VERSION 5.8 ;
BUSBITCHARS "[]" ;
DIVIDERCHAR "/" ;
UNITS
    DATABASE MICRONS 1000 ;
END UNITS

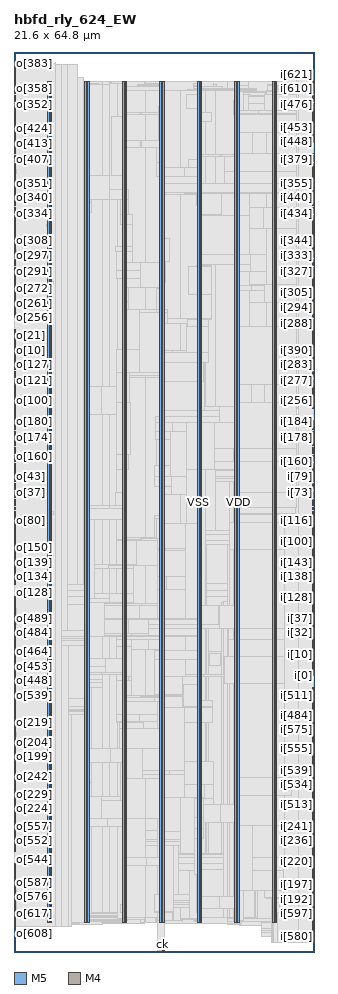
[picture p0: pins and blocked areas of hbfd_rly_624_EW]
MACRO hbfd_rly_624_EW
  FOREIGN hbfd_rly_624_EW 0 0 ;
  CLASS BLOCK ;
  SIZE 21.6 BY 64.8 ;
  PIN ck
    DIRECTION INPUT ;
    USE SIGNAL ;
    PORT
      LAYER M5 ;
        RECT  10.704 0 10.728 0.084 ;
    END
  END ck
  PIN i[0]
    DIRECTION INPUT ;
    USE SIGNAL ;
    PORT
      LAYER M4 ;
        RECT  21.516 19.92 21.6 19.944 ;
    END
  END i[0]
  PIN i[100]
    DIRECTION INPUT ;
    USE SIGNAL ;
    PORT
      LAYER M4 ;
        RECT  21.516 29.52 21.6 29.544 ;
    END
  END i[100]
  PIN i[101]
    DIRECTION INPUT ;
    USE SIGNAL ;
    PORT
      LAYER M4 ;
        RECT  21.516 29.616 21.6 29.64 ;
    END
  END i[101]
  PIN i[102]
    DIRECTION INPUT ;
    USE SIGNAL ;
    PORT
      LAYER M4 ;
        RECT  21.516 29.712 21.6 29.736 ;
    END
  END i[102]
  PIN i[103]
    DIRECTION INPUT ;
    USE SIGNAL ;
    PORT
      LAYER M4 ;
        RECT  21.516 29.808 21.6 29.832 ;
    END
  END i[103]
  PIN i[104]
    DIRECTION INPUT ;
    USE SIGNAL ;
    PORT
      LAYER M4 ;
        RECT  21.516 29.904 21.6 29.928 ;
    END
  END i[104]
  PIN i[105]
    DIRECTION INPUT ;
    USE SIGNAL ;
    PORT
      LAYER M4 ;
        RECT  21.516 30 21.6 30.024 ;
    END
  END i[105]
  PIN i[106]
    DIRECTION INPUT ;
    USE SIGNAL ;
    PORT
      LAYER M4 ;
        RECT  21.516 30.096 21.6 30.12 ;
    END
  END i[106]
  PIN i[107]
    DIRECTION INPUT ;
    USE SIGNAL ;
    PORT
      LAYER M4 ;
        RECT  21.516 30.192 21.6 30.216 ;
    END
  END i[107]
  PIN i[108]
    DIRECTION INPUT ;
    USE SIGNAL ;
    PORT
      LAYER M4 ;
        RECT  21.516 30.288 21.6 30.312 ;
    END
  END i[108]
  PIN i[109]
    DIRECTION INPUT ;
    USE SIGNAL ;
    PORT
      LAYER M4 ;
        RECT  21.516 30.384 21.6 30.408 ;
    END
  END i[109]
  PIN i[10]
    DIRECTION INPUT ;
    USE SIGNAL ;
    PORT
      LAYER M4 ;
        RECT  21.516 20.88 21.6 20.904 ;
    END
  END i[10]
  PIN i[110]
    DIRECTION INPUT ;
    USE SIGNAL ;
    PORT
      LAYER M4 ;
        RECT  21.516 30.48 21.6 30.504 ;
    END
  END i[110]
  PIN i[111]
    DIRECTION INPUT ;
    USE SIGNAL ;
    PORT
      LAYER M4 ;
        RECT  21.516 30.576 21.6 30.6 ;
    END
  END i[111]
  PIN i[112]
    DIRECTION INPUT ;
    USE SIGNAL ;
    PORT
      LAYER M4 ;
        RECT  21.516 30.672 21.6 30.696 ;
    END
  END i[112]
  PIN i[113]
    DIRECTION INPUT ;
    USE SIGNAL ;
    PORT
      LAYER M4 ;
        RECT  21.516 30.768 21.6 30.792 ;
    END
  END i[113]
  PIN i[114]
    DIRECTION INPUT ;
    USE SIGNAL ;
    PORT
      LAYER M4 ;
        RECT  21.516 30.864 21.6 30.888 ;
    END
  END i[114]
  PIN i[115]
    DIRECTION INPUT ;
    USE SIGNAL ;
    PORT
      LAYER M4 ;
        RECT  21.516 30.96 21.6 30.984 ;
    END
  END i[115]
  PIN i[116]
    DIRECTION INPUT ;
    USE SIGNAL ;
    PORT
      LAYER M4 ;
        RECT  21.516 31.056 21.6 31.08 ;
    END
  END i[116]
  PIN i[117]
    DIRECTION INPUT ;
    USE SIGNAL ;
    PORT
      LAYER M4 ;
        RECT  21.516 31.152 21.6 31.176 ;
    END
  END i[117]
  PIN i[118]
    DIRECTION INPUT ;
    USE SIGNAL ;
    PORT
      LAYER M4 ;
        RECT  21.516 31.248 21.6 31.272 ;
    END
  END i[118]
  PIN i[119]
    DIRECTION INPUT ;
    USE SIGNAL ;
    PORT
      LAYER M4 ;
        RECT  21.516 31.344 21.6 31.368 ;
    END
  END i[119]
  PIN i[11]
    DIRECTION INPUT ;
    USE SIGNAL ;
    PORT
      LAYER M4 ;
        RECT  21.516 20.976 21.6 21 ;
    END
  END i[11]
  PIN i[120]
    DIRECTION INPUT ;
    USE SIGNAL ;
    PORT
      LAYER M4 ;
        RECT  21.516 31.44 21.6 31.464 ;
    END
  END i[120]
  PIN i[121]
    DIRECTION INPUT ;
    USE SIGNAL ;
    PORT
      LAYER M4 ;
        RECT  21.516 31.536 21.6 31.56 ;
    END
  END i[121]
  PIN i[122]
    DIRECTION INPUT ;
    USE SIGNAL ;
    PORT
      LAYER M4 ;
        RECT  21.516 31.632 21.6 31.656 ;
    END
  END i[122]
  PIN i[123]
    DIRECTION INPUT ;
    USE SIGNAL ;
    PORT
      LAYER M4 ;
        RECT  21.516 31.728 21.6 31.752 ;
    END
  END i[123]
  PIN i[124]
    DIRECTION INPUT ;
    USE SIGNAL ;
    PORT
      LAYER M4 ;
        RECT  21.516 31.824 21.6 31.848 ;
    END
  END i[124]
  PIN i[125]
    DIRECTION INPUT ;
    USE SIGNAL ;
    PORT
      LAYER M4 ;
        RECT  21.516 31.92 21.6 31.944 ;
    END
  END i[125]
  PIN i[126]
    DIRECTION INPUT ;
    USE SIGNAL ;
    PORT
      LAYER M4 ;
        RECT  21.516 32.016 21.6 32.04 ;
    END
  END i[126]
  PIN i[127]
    DIRECTION INPUT ;
    USE SIGNAL ;
    PORT
      LAYER M4 ;
        RECT  21.516 32.112 21.6 32.136 ;
    END
  END i[127]
  PIN i[128]
    DIRECTION INPUT ;
    USE SIGNAL ;
    PORT
      LAYER M4 ;
        RECT  21.516 26.064 21.6 26.088 ;
    END
  END i[128]
  PIN i[129]
    DIRECTION INPUT ;
    USE SIGNAL ;
    PORT
      LAYER M4 ;
        RECT  21.516 26.16 21.6 26.184 ;
    END
  END i[129]
  PIN i[12]
    DIRECTION INPUT ;
    USE SIGNAL ;
    PORT
      LAYER M4 ;
        RECT  21.516 21.072 21.6 21.096 ;
    END
  END i[12]
  PIN i[130]
    DIRECTION INPUT ;
    USE SIGNAL ;
    PORT
      LAYER M4 ;
        RECT  21.516 26.256 21.6 26.28 ;
    END
  END i[130]
  PIN i[131]
    DIRECTION INPUT ;
    USE SIGNAL ;
    PORT
      LAYER M4 ;
        RECT  21.516 26.352 21.6 26.376 ;
    END
  END i[131]
  PIN i[132]
    DIRECTION INPUT ;
    USE SIGNAL ;
    PORT
      LAYER M4 ;
        RECT  21.516 26.448 21.6 26.472 ;
    END
  END i[132]
  PIN i[133]
    DIRECTION INPUT ;
    USE SIGNAL ;
    PORT
      LAYER M4 ;
        RECT  21.516 26.544 21.6 26.568 ;
    END
  END i[133]
  PIN i[134]
    DIRECTION INPUT ;
    USE SIGNAL ;
    PORT
      LAYER M4 ;
        RECT  21.516 26.64 21.6 26.664 ;
    END
  END i[134]
  PIN i[135]
    DIRECTION INPUT ;
    USE SIGNAL ;
    PORT
      LAYER M4 ;
        RECT  21.516 26.736 21.6 26.76 ;
    END
  END i[135]
  PIN i[136]
    DIRECTION INPUT ;
    USE SIGNAL ;
    PORT
      LAYER M4 ;
        RECT  21.516 26.832 21.6 26.856 ;
    END
  END i[136]
  PIN i[137]
    DIRECTION INPUT ;
    USE SIGNAL ;
    PORT
      LAYER M4 ;
        RECT  21.516 26.928 21.6 26.952 ;
    END
  END i[137]
  PIN i[138]
    DIRECTION INPUT ;
    USE SIGNAL ;
    PORT
      LAYER M4 ;
        RECT  21.516 27.024 21.6 27.048 ;
    END
  END i[138]
  PIN i[139]
    DIRECTION INPUT ;
    USE SIGNAL ;
    PORT
      LAYER M4 ;
        RECT  21.516 27.12 21.6 27.144 ;
    END
  END i[139]
  PIN i[13]
    DIRECTION INPUT ;
    USE SIGNAL ;
    PORT
      LAYER M4 ;
        RECT  21.516 21.168 21.6 21.192 ;
    END
  END i[13]
  PIN i[140]
    DIRECTION INPUT ;
    USE SIGNAL ;
    PORT
      LAYER M4 ;
        RECT  21.516 27.216 21.6 27.24 ;
    END
  END i[140]
  PIN i[141]
    DIRECTION INPUT ;
    USE SIGNAL ;
    PORT
      LAYER M4 ;
        RECT  21.516 27.312 21.6 27.336 ;
    END
  END i[141]
  PIN i[142]
    DIRECTION INPUT ;
    USE SIGNAL ;
    PORT
      LAYER M4 ;
        RECT  21.516 27.408 21.6 27.432 ;
    END
  END i[142]
  PIN i[143]
    DIRECTION INPUT ;
    USE SIGNAL ;
    PORT
      LAYER M4 ;
        RECT  21.516 27.504 21.6 27.528 ;
    END
  END i[143]
  PIN i[144]
    DIRECTION INPUT ;
    USE SIGNAL ;
    PORT
      LAYER M4 ;
        RECT  21.516 27.6 21.6 27.624 ;
    END
  END i[144]
  PIN i[145]
    DIRECTION INPUT ;
    USE SIGNAL ;
    PORT
      LAYER M4 ;
        RECT  21.516 27.696 21.6 27.72 ;
    END
  END i[145]
  PIN i[146]
    DIRECTION INPUT ;
    USE SIGNAL ;
    PORT
      LAYER M4 ;
        RECT  21.516 27.792 21.6 27.816 ;
    END
  END i[146]
  PIN i[147]
    DIRECTION INPUT ;
    USE SIGNAL ;
    PORT
      LAYER M4 ;
        RECT  21.516 27.888 21.6 27.912 ;
    END
  END i[147]
  PIN i[148]
    DIRECTION INPUT ;
    USE SIGNAL ;
    PORT
      LAYER M4 ;
        RECT  21.516 27.984 21.6 28.008 ;
    END
  END i[148]
  PIN i[149]
    DIRECTION INPUT ;
    USE SIGNAL ;
    PORT
      LAYER M4 ;
        RECT  21.516 28.08 21.6 28.104 ;
    END
  END i[149]
  PIN i[14]
    DIRECTION INPUT ;
    USE SIGNAL ;
    PORT
      LAYER M4 ;
        RECT  21.516 21.264 21.6 21.288 ;
    END
  END i[14]
  PIN i[150]
    DIRECTION INPUT ;
    USE SIGNAL ;
    PORT
      LAYER M4 ;
        RECT  21.516 28.176 21.6 28.2 ;
    END
  END i[150]
  PIN i[151]
    DIRECTION INPUT ;
    USE SIGNAL ;
    PORT
      LAYER M4 ;
        RECT  21.516 28.272 21.6 28.296 ;
    END
  END i[151]
  PIN i[152]
    DIRECTION INPUT ;
    USE SIGNAL ;
    PORT
      LAYER M4 ;
        RECT  21.516 28.368 21.6 28.392 ;
    END
  END i[152]
  PIN i[153]
    DIRECTION INPUT ;
    USE SIGNAL ;
    PORT
      LAYER M4 ;
        RECT  21.516 28.464 21.6 28.488 ;
    END
  END i[153]
  PIN i[154]
    DIRECTION INPUT ;
    USE SIGNAL ;
    PORT
      LAYER M4 ;
        RECT  21.516 28.56 21.6 28.584 ;
    END
  END i[154]
  PIN i[155]
    DIRECTION INPUT ;
    USE SIGNAL ;
    PORT
      LAYER M4 ;
        RECT  21.516 28.656 21.6 28.68 ;
    END
  END i[155]
  PIN i[156]
    DIRECTION INPUT ;
    USE SIGNAL ;
    PORT
      LAYER M4 ;
        RECT  21.516 28.752 21.6 28.776 ;
    END
  END i[156]
  PIN i[157]
    DIRECTION INPUT ;
    USE SIGNAL ;
    PORT
      LAYER M4 ;
        RECT  21.516 28.848 21.6 28.872 ;
    END
  END i[157]
  PIN i[158]
    DIRECTION INPUT ;
    USE SIGNAL ;
    PORT
      LAYER M4 ;
        RECT  21.516 28.944 21.6 28.968 ;
    END
  END i[158]
  PIN i[159]
    DIRECTION INPUT ;
    USE SIGNAL ;
    PORT
      LAYER M4 ;
        RECT  21.516 29.04 21.6 29.064 ;
    END
  END i[159]
  PIN i[15]
    DIRECTION INPUT ;
    USE SIGNAL ;
    PORT
      LAYER M4 ;
        RECT  21.516 21.36 21.6 21.384 ;
    END
  END i[15]
  PIN i[160]
    DIRECTION INPUT ;
    USE SIGNAL ;
    PORT
      LAYER M4 ;
        RECT  21.516 35.28 21.6 35.304 ;
    END
  END i[160]
  PIN i[161]
    DIRECTION INPUT ;
    USE SIGNAL ;
    PORT
      LAYER M4 ;
        RECT  21.516 35.376 21.6 35.4 ;
    END
  END i[161]
  PIN i[162]
    DIRECTION INPUT ;
    USE SIGNAL ;
    PORT
      LAYER M4 ;
        RECT  21.516 35.472 21.6 35.496 ;
    END
  END i[162]
  PIN i[163]
    DIRECTION INPUT ;
    USE SIGNAL ;
    PORT
      LAYER M4 ;
        RECT  21.516 35.568 21.6 35.592 ;
    END
  END i[163]
  PIN i[164]
    DIRECTION INPUT ;
    USE SIGNAL ;
    PORT
      LAYER M4 ;
        RECT  21.516 35.664 21.6 35.688 ;
    END
  END i[164]
  PIN i[165]
    DIRECTION INPUT ;
    USE SIGNAL ;
    PORT
      LAYER M4 ;
        RECT  21.516 35.76 21.6 35.784 ;
    END
  END i[165]
  PIN i[166]
    DIRECTION INPUT ;
    USE SIGNAL ;
    PORT
      LAYER M4 ;
        RECT  21.516 35.856 21.6 35.88 ;
    END
  END i[166]
  PIN i[167]
    DIRECTION INPUT ;
    USE SIGNAL ;
    PORT
      LAYER M4 ;
        RECT  21.516 35.952 21.6 35.976 ;
    END
  END i[167]
  PIN i[168]
    DIRECTION INPUT ;
    USE SIGNAL ;
    PORT
      LAYER M4 ;
        RECT  21.516 36.048 21.6 36.072 ;
    END
  END i[168]
  PIN i[169]
    DIRECTION INPUT ;
    USE SIGNAL ;
    PORT
      LAYER M4 ;
        RECT  21.516 36.144 21.6 36.168 ;
    END
  END i[169]
  PIN i[16]
    DIRECTION INPUT ;
    USE SIGNAL ;
    PORT
      LAYER M4 ;
        RECT  21.516 21.456 21.6 21.48 ;
    END
  END i[16]
  PIN i[170]
    DIRECTION INPUT ;
    USE SIGNAL ;
    PORT
      LAYER M4 ;
        RECT  21.516 36.24 21.6 36.264 ;
    END
  END i[170]
  PIN i[171]
    DIRECTION INPUT ;
    USE SIGNAL ;
    PORT
      LAYER M4 ;
        RECT  21.516 36.336 21.6 36.36 ;
    END
  END i[171]
  PIN i[172]
    DIRECTION INPUT ;
    USE SIGNAL ;
    PORT
      LAYER M4 ;
        RECT  21.516 36.432 21.6 36.456 ;
    END
  END i[172]
  PIN i[173]
    DIRECTION INPUT ;
    USE SIGNAL ;
    PORT
      LAYER M4 ;
        RECT  21.516 36.528 21.6 36.552 ;
    END
  END i[173]
  PIN i[174]
    DIRECTION INPUT ;
    USE SIGNAL ;
    PORT
      LAYER M4 ;
        RECT  21.516 36.624 21.6 36.648 ;
    END
  END i[174]
  PIN i[175]
    DIRECTION INPUT ;
    USE SIGNAL ;
    PORT
      LAYER M4 ;
        RECT  21.516 36.72 21.6 36.744 ;
    END
  END i[175]
  PIN i[176]
    DIRECTION INPUT ;
    USE SIGNAL ;
    PORT
      LAYER M4 ;
        RECT  21.516 36.816 21.6 36.84 ;
    END
  END i[176]
  PIN i[177]
    DIRECTION INPUT ;
    USE SIGNAL ;
    PORT
      LAYER M4 ;
        RECT  21.516 36.912 21.6 36.936 ;
    END
  END i[177]
  PIN i[178]
    DIRECTION INPUT ;
    USE SIGNAL ;
    PORT
      LAYER M4 ;
        RECT  21.516 37.008 21.6 37.032 ;
    END
  END i[178]
  PIN i[179]
    DIRECTION INPUT ;
    USE SIGNAL ;
    PORT
      LAYER M4 ;
        RECT  21.516 37.104 21.6 37.128 ;
    END
  END i[179]
  PIN i[17]
    DIRECTION INPUT ;
    USE SIGNAL ;
    PORT
      LAYER M4 ;
        RECT  21.516 21.552 21.6 21.576 ;
    END
  END i[17]
  PIN i[180]
    DIRECTION INPUT ;
    USE SIGNAL ;
    PORT
      LAYER M4 ;
        RECT  21.516 37.2 21.6 37.224 ;
    END
  END i[180]
  PIN i[181]
    DIRECTION INPUT ;
    USE SIGNAL ;
    PORT
      LAYER M4 ;
        RECT  21.516 37.296 21.6 37.32 ;
    END
  END i[181]
  PIN i[182]
    DIRECTION INPUT ;
    USE SIGNAL ;
    PORT
      LAYER M4 ;
        RECT  21.516 37.392 21.6 37.416 ;
    END
  END i[182]
  PIN i[183]
    DIRECTION INPUT ;
    USE SIGNAL ;
    PORT
      LAYER M4 ;
        RECT  21.516 37.488 21.6 37.512 ;
    END
  END i[183]
  PIN i[184]
    DIRECTION INPUT ;
    USE SIGNAL ;
    PORT
      LAYER M4 ;
        RECT  21.516 37.584 21.6 37.608 ;
    END
  END i[184]
  PIN i[185]
    DIRECTION INPUT ;
    USE SIGNAL ;
    PORT
      LAYER M4 ;
        RECT  21.516 37.68 21.6 37.704 ;
    END
  END i[185]
  PIN i[186]
    DIRECTION INPUT ;
    USE SIGNAL ;
    PORT
      LAYER M4 ;
        RECT  21.516 37.776 21.6 37.8 ;
    END
  END i[186]
  PIN i[187]
    DIRECTION INPUT ;
    USE SIGNAL ;
    PORT
      LAYER M4 ;
        RECT  21.516 37.872 21.6 37.896 ;
    END
  END i[187]
  PIN i[188]
    DIRECTION INPUT ;
    USE SIGNAL ;
    PORT
      LAYER M4 ;
        RECT  21.516 37.968 21.6 37.992 ;
    END
  END i[188]
  PIN i[189]
    DIRECTION INPUT ;
    USE SIGNAL ;
    PORT
      LAYER M4 ;
        RECT  21.516 38.064 21.6 38.088 ;
    END
  END i[189]
  PIN i[18]
    DIRECTION INPUT ;
    USE SIGNAL ;
    PORT
      LAYER M4 ;
        RECT  21.516 21.648 21.6 21.672 ;
    END
  END i[18]
  PIN i[190]
    DIRECTION INPUT ;
    USE SIGNAL ;
    PORT
      LAYER M4 ;
        RECT  21.516 38.16 21.6 38.184 ;
    END
  END i[190]
  PIN i[191]
    DIRECTION INPUT ;
    USE SIGNAL ;
    PORT
      LAYER M4 ;
        RECT  21.516 38.256 21.6 38.28 ;
    END
  END i[191]
  PIN i[192]
    DIRECTION INPUT ;
    USE SIGNAL ;
    PORT
      LAYER M4 ;
        RECT  21.516 3.792 21.6 3.816 ;
    END
  END i[192]
  PIN i[193]
    DIRECTION INPUT ;
    USE SIGNAL ;
    PORT
      LAYER M4 ;
        RECT  21.516 3.888 21.6 3.912 ;
    END
  END i[193]
  PIN i[194]
    DIRECTION INPUT ;
    USE SIGNAL ;
    PORT
      LAYER M4 ;
        RECT  21.516 3.984 21.6 4.008 ;
    END
  END i[194]
  PIN i[195]
    DIRECTION INPUT ;
    USE SIGNAL ;
    PORT
      LAYER M4 ;
        RECT  21.516 4.08 21.6 4.104 ;
    END
  END i[195]
  PIN i[196]
    DIRECTION INPUT ;
    USE SIGNAL ;
    PORT
      LAYER M4 ;
        RECT  21.516 4.176 21.6 4.2 ;
    END
  END i[196]
  PIN i[197]
    DIRECTION INPUT ;
    USE SIGNAL ;
    PORT
      LAYER M4 ;
        RECT  21.516 4.272 21.6 4.296 ;
    END
  END i[197]
  PIN i[198]
    DIRECTION INPUT ;
    USE SIGNAL ;
    PORT
      LAYER M4 ;
        RECT  21.516 4.368 21.6 4.392 ;
    END
  END i[198]
  PIN i[199]
    DIRECTION INPUT ;
    USE SIGNAL ;
    PORT
      LAYER M4 ;
        RECT  21.516 4.464 21.6 4.488 ;
    END
  END i[199]
  PIN i[19]
    DIRECTION INPUT ;
    USE SIGNAL ;
    PORT
      LAYER M4 ;
        RECT  21.516 21.744 21.6 21.768 ;
    END
  END i[19]
  PIN i[1]
    DIRECTION INPUT ;
    USE SIGNAL ;
    PORT
      LAYER M4 ;
        RECT  21.516 20.016 21.6 20.04 ;
    END
  END i[1]
  PIN i[200]
    DIRECTION INPUT ;
    USE SIGNAL ;
    PORT
      LAYER M4 ;
        RECT  21.516 4.56 21.6 4.584 ;
    END
  END i[200]
  PIN i[201]
    DIRECTION INPUT ;
    USE SIGNAL ;
    PORT
      LAYER M4 ;
        RECT  21.516 4.656 21.6 4.68 ;
    END
  END i[201]
  PIN i[202]
    DIRECTION INPUT ;
    USE SIGNAL ;
    PORT
      LAYER M4 ;
        RECT  21.516 4.752 21.6 4.776 ;
    END
  END i[202]
  PIN i[203]
    DIRECTION INPUT ;
    USE SIGNAL ;
    PORT
      LAYER M4 ;
        RECT  21.516 4.848 21.6 4.872 ;
    END
  END i[203]
  PIN i[204]
    DIRECTION INPUT ;
    USE SIGNAL ;
    PORT
      LAYER M4 ;
        RECT  21.516 4.944 21.6 4.968 ;
    END
  END i[204]
  PIN i[205]
    DIRECTION INPUT ;
    USE SIGNAL ;
    PORT
      LAYER M4 ;
        RECT  21.516 5.04 21.6 5.064 ;
    END
  END i[205]
  PIN i[206]
    DIRECTION INPUT ;
    USE SIGNAL ;
    PORT
      LAYER M4 ;
        RECT  21.516 5.136 21.6 5.16 ;
    END
  END i[206]
  PIN i[207]
    DIRECTION INPUT ;
    USE SIGNAL ;
    PORT
      LAYER M4 ;
        RECT  21.516 5.232 21.6 5.256 ;
    END
  END i[207]
  PIN i[208]
    DIRECTION INPUT ;
    USE SIGNAL ;
    PORT
      LAYER M4 ;
        RECT  21.516 5.328 21.6 5.352 ;
    END
  END i[208]
  PIN i[209]
    DIRECTION INPUT ;
    USE SIGNAL ;
    PORT
      LAYER M4 ;
        RECT  21.516 5.424 21.6 5.448 ;
    END
  END i[209]
  PIN i[20]
    DIRECTION INPUT ;
    USE SIGNAL ;
    PORT
      LAYER M4 ;
        RECT  21.516 21.84 21.6 21.864 ;
    END
  END i[20]
  PIN i[210]
    DIRECTION INPUT ;
    USE SIGNAL ;
    PORT
      LAYER M4 ;
        RECT  21.516 5.52 21.6 5.544 ;
    END
  END i[210]
  PIN i[211]
    DIRECTION INPUT ;
    USE SIGNAL ;
    PORT
      LAYER M4 ;
        RECT  21.516 5.616 21.6 5.64 ;
    END
  END i[211]
  PIN i[212]
    DIRECTION INPUT ;
    USE SIGNAL ;
    PORT
      LAYER M4 ;
        RECT  21.516 5.712 21.6 5.736 ;
    END
  END i[212]
  PIN i[213]
    DIRECTION INPUT ;
    USE SIGNAL ;
    PORT
      LAYER M4 ;
        RECT  21.516 5.808 21.6 5.832 ;
    END
  END i[213]
  PIN i[214]
    DIRECTION INPUT ;
    USE SIGNAL ;
    PORT
      LAYER M4 ;
        RECT  21.516 5.904 21.6 5.928 ;
    END
  END i[214]
  PIN i[215]
    DIRECTION INPUT ;
    USE SIGNAL ;
    PORT
      LAYER M4 ;
        RECT  21.516 6 21.6 6.024 ;
    END
  END i[215]
  PIN i[216]
    DIRECTION INPUT ;
    USE SIGNAL ;
    PORT
      LAYER M4 ;
        RECT  21.516 6.096 21.6 6.12 ;
    END
  END i[216]
  PIN i[217]
    DIRECTION INPUT ;
    USE SIGNAL ;
    PORT
      LAYER M4 ;
        RECT  21.516 6.192 21.6 6.216 ;
    END
  END i[217]
  PIN i[218]
    DIRECTION INPUT ;
    USE SIGNAL ;
    PORT
      LAYER M4 ;
        RECT  21.516 6.288 21.6 6.312 ;
    END
  END i[218]
  PIN i[219]
    DIRECTION INPUT ;
    USE SIGNAL ;
    PORT
      LAYER M4 ;
        RECT  21.516 6.384 21.6 6.408 ;
    END
  END i[219]
  PIN i[21]
    DIRECTION INPUT ;
    USE SIGNAL ;
    PORT
      LAYER M4 ;
        RECT  21.516 21.936 21.6 21.96 ;
    END
  END i[21]
  PIN i[220]
    DIRECTION INPUT ;
    USE SIGNAL ;
    PORT
      LAYER M4 ;
        RECT  21.516 6.48 21.6 6.504 ;
    END
  END i[220]
  PIN i[221]
    DIRECTION INPUT ;
    USE SIGNAL ;
    PORT
      LAYER M4 ;
        RECT  21.516 6.576 21.6 6.6 ;
    END
  END i[221]
  PIN i[222]
    DIRECTION INPUT ;
    USE SIGNAL ;
    PORT
      LAYER M4 ;
        RECT  21.516 6.672 21.6 6.696 ;
    END
  END i[222]
  PIN i[223]
    DIRECTION INPUT ;
    USE SIGNAL ;
    PORT
      LAYER M4 ;
        RECT  21.516 6.768 21.6 6.792 ;
    END
  END i[223]
  PIN i[224]
    DIRECTION INPUT ;
    USE SIGNAL ;
    PORT
      LAYER M4 ;
        RECT  21.516 6.864 21.6 6.888 ;
    END
  END i[224]
  PIN i[225]
    DIRECTION INPUT ;
    USE SIGNAL ;
    PORT
      LAYER M4 ;
        RECT  21.516 6.96 21.6 6.984 ;
    END
  END i[225]
  PIN i[226]
    DIRECTION INPUT ;
    USE SIGNAL ;
    PORT
      LAYER M4 ;
        RECT  21.516 7.056 21.6 7.08 ;
    END
  END i[226]
  PIN i[227]
    DIRECTION INPUT ;
    USE SIGNAL ;
    PORT
      LAYER M4 ;
        RECT  21.516 7.152 21.6 7.176 ;
    END
  END i[227]
  PIN i[228]
    DIRECTION INPUT ;
    USE SIGNAL ;
    PORT
      LAYER M4 ;
        RECT  21.516 7.248 21.6 7.272 ;
    END
  END i[228]
  PIN i[229]
    DIRECTION INPUT ;
    USE SIGNAL ;
    PORT
      LAYER M4 ;
        RECT  21.516 7.344 21.6 7.368 ;
    END
  END i[229]
  PIN i[22]
    DIRECTION INPUT ;
    USE SIGNAL ;
    PORT
      LAYER M4 ;
        RECT  21.516 22.032 21.6 22.056 ;
    END
  END i[22]
  PIN i[230]
    DIRECTION INPUT ;
    USE SIGNAL ;
    PORT
      LAYER M4 ;
        RECT  21.516 7.44 21.6 7.464 ;
    END
  END i[230]
  PIN i[231]
    DIRECTION INPUT ;
    USE SIGNAL ;
    PORT
      LAYER M4 ;
        RECT  21.516 7.536 21.6 7.56 ;
    END
  END i[231]
  PIN i[232]
    DIRECTION INPUT ;
    USE SIGNAL ;
    PORT
      LAYER M4 ;
        RECT  21.516 7.632 21.6 7.656 ;
    END
  END i[232]
  PIN i[233]
    DIRECTION INPUT ;
    USE SIGNAL ;
    PORT
      LAYER M4 ;
        RECT  21.516 7.728 21.6 7.752 ;
    END
  END i[233]
  PIN i[234]
    DIRECTION INPUT ;
    USE SIGNAL ;
    PORT
      LAYER M4 ;
        RECT  21.516 7.824 21.6 7.848 ;
    END
  END i[234]
  PIN i[235]
    DIRECTION INPUT ;
    USE SIGNAL ;
    PORT
      LAYER M4 ;
        RECT  21.516 7.92 21.6 7.944 ;
    END
  END i[235]
  PIN i[236]
    DIRECTION INPUT ;
    USE SIGNAL ;
    PORT
      LAYER M4 ;
        RECT  21.516 8.016 21.6 8.04 ;
    END
  END i[236]
  PIN i[237]
    DIRECTION INPUT ;
    USE SIGNAL ;
    PORT
      LAYER M4 ;
        RECT  21.516 8.112 21.6 8.136 ;
    END
  END i[237]
  PIN i[238]
    DIRECTION INPUT ;
    USE SIGNAL ;
    PORT
      LAYER M4 ;
        RECT  21.516 8.208 21.6 8.232 ;
    END
  END i[238]
  PIN i[239]
    DIRECTION INPUT ;
    USE SIGNAL ;
    PORT
      LAYER M4 ;
        RECT  21.516 8.304 21.6 8.328 ;
    END
  END i[239]
  PIN i[23]
    DIRECTION INPUT ;
    USE SIGNAL ;
    PORT
      LAYER M4 ;
        RECT  21.516 22.128 21.6 22.152 ;
    END
  END i[23]
  PIN i[240]
    DIRECTION INPUT ;
    USE SIGNAL ;
    PORT
      LAYER M4 ;
        RECT  21.516 8.4 21.6 8.424 ;
    END
  END i[240]
  PIN i[241]
    DIRECTION INPUT ;
    USE SIGNAL ;
    PORT
      LAYER M4 ;
        RECT  21.516 8.496 21.6 8.52 ;
    END
  END i[241]
  PIN i[242]
    DIRECTION INPUT ;
    USE SIGNAL ;
    PORT
      LAYER M4 ;
        RECT  21.516 8.592 21.6 8.616 ;
    END
  END i[242]
  PIN i[243]
    DIRECTION INPUT ;
    USE SIGNAL ;
    PORT
      LAYER M4 ;
        RECT  21.516 8.688 21.6 8.712 ;
    END
  END i[243]
  PIN i[244]
    DIRECTION INPUT ;
    USE SIGNAL ;
    PORT
      LAYER M4 ;
        RECT  21.516 8.784 21.6 8.808 ;
    END
  END i[244]
  PIN i[245]
    DIRECTION INPUT ;
    USE SIGNAL ;
    PORT
      LAYER M4 ;
        RECT  21.516 8.88 21.6 8.904 ;
    END
  END i[245]
  PIN i[246]
    DIRECTION INPUT ;
    USE SIGNAL ;
    PORT
      LAYER M4 ;
        RECT  21.516 8.976 21.6 9 ;
    END
  END i[246]
  PIN i[247]
    DIRECTION INPUT ;
    USE SIGNAL ;
    PORT
      LAYER M4 ;
        RECT  21.516 9.072 21.6 9.096 ;
    END
  END i[247]
  PIN i[248]
    DIRECTION INPUT ;
    USE SIGNAL ;
    PORT
      LAYER M4 ;
        RECT  21.516 9.168 21.6 9.192 ;
    END
  END i[248]
  PIN i[249]
    DIRECTION INPUT ;
    USE SIGNAL ;
    PORT
      LAYER M4 ;
        RECT  21.516 9.264 21.6 9.288 ;
    END
  END i[249]
  PIN i[24]
    DIRECTION INPUT ;
    USE SIGNAL ;
    PORT
      LAYER M4 ;
        RECT  21.516 22.224 21.6 22.248 ;
    END
  END i[24]
  PIN i[250]
    DIRECTION INPUT ;
    USE SIGNAL ;
    PORT
      LAYER M4 ;
        RECT  21.516 9.36 21.6 9.384 ;
    END
  END i[250]
  PIN i[251]
    DIRECTION INPUT ;
    USE SIGNAL ;
    PORT
      LAYER M4 ;
        RECT  21.516 9.456 21.6 9.48 ;
    END
  END i[251]
  PIN i[252]
    DIRECTION INPUT ;
    USE SIGNAL ;
    PORT
      LAYER M4 ;
        RECT  21.516 9.552 21.6 9.576 ;
    END
  END i[252]
  PIN i[253]
    DIRECTION INPUT ;
    USE SIGNAL ;
    PORT
      LAYER M4 ;
        RECT  21.516 9.648 21.6 9.672 ;
    END
  END i[253]
  PIN i[254]
    DIRECTION INPUT ;
    USE SIGNAL ;
    PORT
      LAYER M4 ;
        RECT  21.516 9.744 21.6 9.768 ;
    END
  END i[254]
  PIN i[255]
    DIRECTION INPUT ;
    USE SIGNAL ;
    PORT
      LAYER M4 ;
        RECT  21.516 9.84 21.6 9.864 ;
    END
  END i[255]
  PIN i[256]
    DIRECTION INPUT ;
    USE SIGNAL ;
    PORT
      LAYER M4 ;
        RECT  21.516 39.12 21.6 39.144 ;
    END
  END i[256]
  PIN i[257]
    DIRECTION INPUT ;
    USE SIGNAL ;
    PORT
      LAYER M4 ;
        RECT  21.516 39.216 21.6 39.24 ;
    END
  END i[257]
  PIN i[258]
    DIRECTION INPUT ;
    USE SIGNAL ;
    PORT
      LAYER M4 ;
        RECT  21.516 39.312 21.6 39.336 ;
    END
  END i[258]
  PIN i[259]
    DIRECTION INPUT ;
    USE SIGNAL ;
    PORT
      LAYER M4 ;
        RECT  21.516 39.408 21.6 39.432 ;
    END
  END i[259]
  PIN i[25]
    DIRECTION INPUT ;
    USE SIGNAL ;
    PORT
      LAYER M4 ;
        RECT  21.516 22.32 21.6 22.344 ;
    END
  END i[25]
  PIN i[260]
    DIRECTION INPUT ;
    USE SIGNAL ;
    PORT
      LAYER M4 ;
        RECT  21.516 39.504 21.6 39.528 ;
    END
  END i[260]
  PIN i[261]
    DIRECTION INPUT ;
    USE SIGNAL ;
    PORT
      LAYER M4 ;
        RECT  21.516 39.6 21.6 39.624 ;
    END
  END i[261]
  PIN i[262]
    DIRECTION INPUT ;
    USE SIGNAL ;
    PORT
      LAYER M4 ;
        RECT  21.516 39.696 21.6 39.72 ;
    END
  END i[262]
  PIN i[263]
    DIRECTION INPUT ;
    USE SIGNAL ;
    PORT
      LAYER M4 ;
        RECT  21.516 39.792 21.6 39.816 ;
    END
  END i[263]
  PIN i[264]
    DIRECTION INPUT ;
    USE SIGNAL ;
    PORT
      LAYER M4 ;
        RECT  21.516 39.888 21.6 39.912 ;
    END
  END i[264]
  PIN i[265]
    DIRECTION INPUT ;
    USE SIGNAL ;
    PORT
      LAYER M4 ;
        RECT  21.516 39.984 21.6 40.008 ;
    END
  END i[265]
  PIN i[266]
    DIRECTION INPUT ;
    USE SIGNAL ;
    PORT
      LAYER M4 ;
        RECT  21.516 40.08 21.6 40.104 ;
    END
  END i[266]
  PIN i[267]
    DIRECTION INPUT ;
    USE SIGNAL ;
    PORT
      LAYER M4 ;
        RECT  21.516 40.176 21.6 40.2 ;
    END
  END i[267]
  PIN i[268]
    DIRECTION INPUT ;
    USE SIGNAL ;
    PORT
      LAYER M4 ;
        RECT  21.516 40.272 21.6 40.296 ;
    END
  END i[268]
  PIN i[269]
    DIRECTION INPUT ;
    USE SIGNAL ;
    PORT
      LAYER M4 ;
        RECT  21.516 40.368 21.6 40.392 ;
    END
  END i[269]
  PIN i[26]
    DIRECTION INPUT ;
    USE SIGNAL ;
    PORT
      LAYER M4 ;
        RECT  21.516 22.416 21.6 22.44 ;
    END
  END i[26]
  PIN i[270]
    DIRECTION INPUT ;
    USE SIGNAL ;
    PORT
      LAYER M4 ;
        RECT  21.516 40.464 21.6 40.488 ;
    END
  END i[270]
  PIN i[271]
    DIRECTION INPUT ;
    USE SIGNAL ;
    PORT
      LAYER M4 ;
        RECT  21.516 40.56 21.6 40.584 ;
    END
  END i[271]
  PIN i[272]
    DIRECTION INPUT ;
    USE SIGNAL ;
    PORT
      LAYER M4 ;
        RECT  21.516 40.656 21.6 40.68 ;
    END
  END i[272]
  PIN i[273]
    DIRECTION INPUT ;
    USE SIGNAL ;
    PORT
      LAYER M4 ;
        RECT  21.516 40.752 21.6 40.776 ;
    END
  END i[273]
  PIN i[274]
    DIRECTION INPUT ;
    USE SIGNAL ;
    PORT
      LAYER M4 ;
        RECT  21.516 40.848 21.6 40.872 ;
    END
  END i[274]
  PIN i[275]
    DIRECTION INPUT ;
    USE SIGNAL ;
    PORT
      LAYER M4 ;
        RECT  21.516 40.944 21.6 40.968 ;
    END
  END i[275]
  PIN i[276]
    DIRECTION INPUT ;
    USE SIGNAL ;
    PORT
      LAYER M4 ;
        RECT  21.516 41.04 21.6 41.064 ;
    END
  END i[276]
  PIN i[277]
    DIRECTION INPUT ;
    USE SIGNAL ;
    PORT
      LAYER M4 ;
        RECT  21.516 41.136 21.6 41.16 ;
    END
  END i[277]
  PIN i[278]
    DIRECTION INPUT ;
    USE SIGNAL ;
    PORT
      LAYER M4 ;
        RECT  21.516 41.232 21.6 41.256 ;
    END
  END i[278]
  PIN i[279]
    DIRECTION INPUT ;
    USE SIGNAL ;
    PORT
      LAYER M4 ;
        RECT  21.516 41.328 21.6 41.352 ;
    END
  END i[279]
  PIN i[27]
    DIRECTION INPUT ;
    USE SIGNAL ;
    PORT
      LAYER M4 ;
        RECT  21.516 22.512 21.6 22.536 ;
    END
  END i[27]
  PIN i[280]
    DIRECTION INPUT ;
    USE SIGNAL ;
    PORT
      LAYER M4 ;
        RECT  21.516 41.424 21.6 41.448 ;
    END
  END i[280]
  PIN i[281]
    DIRECTION INPUT ;
    USE SIGNAL ;
    PORT
      LAYER M4 ;
        RECT  21.516 41.52 21.6 41.544 ;
    END
  END i[281]
  PIN i[282]
    DIRECTION INPUT ;
    USE SIGNAL ;
    PORT
      LAYER M4 ;
        RECT  21.516 41.616 21.6 41.64 ;
    END
  END i[282]
  PIN i[283]
    DIRECTION INPUT ;
    USE SIGNAL ;
    PORT
      LAYER M4 ;
        RECT  21.516 41.712 21.6 41.736 ;
    END
  END i[283]
  PIN i[284]
    DIRECTION INPUT ;
    USE SIGNAL ;
    PORT
      LAYER M4 ;
        RECT  21.516 41.808 21.6 41.832 ;
    END
  END i[284]
  PIN i[285]
    DIRECTION INPUT ;
    USE SIGNAL ;
    PORT
      LAYER M4 ;
        RECT  21.516 41.904 21.6 41.928 ;
    END
  END i[285]
  PIN i[286]
    DIRECTION INPUT ;
    USE SIGNAL ;
    PORT
      LAYER M4 ;
        RECT  21.516 42 21.6 42.024 ;
    END
  END i[286]
  PIN i[287]
    DIRECTION INPUT ;
    USE SIGNAL ;
    PORT
      LAYER M4 ;
        RECT  21.516 42.096 21.6 42.12 ;
    END
  END i[287]
  PIN i[288]
    DIRECTION INPUT ;
    USE SIGNAL ;
    PORT
      LAYER M4 ;
        RECT  21.516 45.264 21.6 45.288 ;
    END
  END i[288]
  PIN i[289]
    DIRECTION INPUT ;
    USE SIGNAL ;
    PORT
      LAYER M4 ;
        RECT  21.516 45.36 21.6 45.384 ;
    END
  END i[289]
  PIN i[28]
    DIRECTION INPUT ;
    USE SIGNAL ;
    PORT
      LAYER M4 ;
        RECT  21.516 22.608 21.6 22.632 ;
    END
  END i[28]
  PIN i[290]
    DIRECTION INPUT ;
    USE SIGNAL ;
    PORT
      LAYER M4 ;
        RECT  21.516 45.456 21.6 45.48 ;
    END
  END i[290]
  PIN i[291]
    DIRECTION INPUT ;
    USE SIGNAL ;
    PORT
      LAYER M4 ;
        RECT  21.516 45.552 21.6 45.576 ;
    END
  END i[291]
  PIN i[292]
    DIRECTION INPUT ;
    USE SIGNAL ;
    PORT
      LAYER M4 ;
        RECT  21.516 45.648 21.6 45.672 ;
    END
  END i[292]
  PIN i[293]
    DIRECTION INPUT ;
    USE SIGNAL ;
    PORT
      LAYER M4 ;
        RECT  21.516 45.744 21.6 45.768 ;
    END
  END i[293]
  PIN i[294]
    DIRECTION INPUT ;
    USE SIGNAL ;
    PORT
      LAYER M4 ;
        RECT  21.516 45.84 21.6 45.864 ;
    END
  END i[294]
  PIN i[295]
    DIRECTION INPUT ;
    USE SIGNAL ;
    PORT
      LAYER M4 ;
        RECT  21.516 45.936 21.6 45.96 ;
    END
  END i[295]
  PIN i[296]
    DIRECTION INPUT ;
    USE SIGNAL ;
    PORT
      LAYER M4 ;
        RECT  21.516 46.032 21.6 46.056 ;
    END
  END i[296]
  PIN i[297]
    DIRECTION INPUT ;
    USE SIGNAL ;
    PORT
      LAYER M4 ;
        RECT  21.516 46.128 21.6 46.152 ;
    END
  END i[297]
  PIN i[298]
    DIRECTION INPUT ;
    USE SIGNAL ;
    PORT
      LAYER M4 ;
        RECT  21.516 46.224 21.6 46.248 ;
    END
  END i[298]
  PIN i[299]
    DIRECTION INPUT ;
    USE SIGNAL ;
    PORT
      LAYER M4 ;
        RECT  21.516 46.32 21.6 46.344 ;
    END
  END i[299]
  PIN i[29]
    DIRECTION INPUT ;
    USE SIGNAL ;
    PORT
      LAYER M4 ;
        RECT  21.516 22.704 21.6 22.728 ;
    END
  END i[29]
  PIN i[2]
    DIRECTION INPUT ;
    USE SIGNAL ;
    PORT
      LAYER M4 ;
        RECT  21.516 20.112 21.6 20.136 ;
    END
  END i[2]
  PIN i[300]
    DIRECTION INPUT ;
    USE SIGNAL ;
    PORT
      LAYER M4 ;
        RECT  21.516 46.416 21.6 46.44 ;
    END
  END i[300]
  PIN i[301]
    DIRECTION INPUT ;
    USE SIGNAL ;
    PORT
      LAYER M4 ;
        RECT  21.516 46.512 21.6 46.536 ;
    END
  END i[301]
  PIN i[302]
    DIRECTION INPUT ;
    USE SIGNAL ;
    PORT
      LAYER M4 ;
        RECT  21.516 46.608 21.6 46.632 ;
    END
  END i[302]
  PIN i[303]
    DIRECTION INPUT ;
    USE SIGNAL ;
    PORT
      LAYER M4 ;
        RECT  21.516 46.704 21.6 46.728 ;
    END
  END i[303]
  PIN i[304]
    DIRECTION INPUT ;
    USE SIGNAL ;
    PORT
      LAYER M4 ;
        RECT  21.516 46.8 21.6 46.824 ;
    END
  END i[304]
  PIN i[305]
    DIRECTION INPUT ;
    USE SIGNAL ;
    PORT
      LAYER M4 ;
        RECT  21.516 46.896 21.6 46.92 ;
    END
  END i[305]
  PIN i[306]
    DIRECTION INPUT ;
    USE SIGNAL ;
    PORT
      LAYER M4 ;
        RECT  21.516 46.992 21.6 47.016 ;
    END
  END i[306]
  PIN i[307]
    DIRECTION INPUT ;
    USE SIGNAL ;
    PORT
      LAYER M4 ;
        RECT  21.516 47.088 21.6 47.112 ;
    END
  END i[307]
  PIN i[308]
    DIRECTION INPUT ;
    USE SIGNAL ;
    PORT
      LAYER M4 ;
        RECT  21.516 47.184 21.6 47.208 ;
    END
  END i[308]
  PIN i[309]
    DIRECTION INPUT ;
    USE SIGNAL ;
    PORT
      LAYER M4 ;
        RECT  21.516 47.28 21.6 47.304 ;
    END
  END i[309]
  PIN i[30]
    DIRECTION INPUT ;
    USE SIGNAL ;
    PORT
      LAYER M4 ;
        RECT  21.516 22.8 21.6 22.824 ;
    END
  END i[30]
  PIN i[310]
    DIRECTION INPUT ;
    USE SIGNAL ;
    PORT
      LAYER M4 ;
        RECT  21.516 47.376 21.6 47.4 ;
    END
  END i[310]
  PIN i[311]
    DIRECTION INPUT ;
    USE SIGNAL ;
    PORT
      LAYER M4 ;
        RECT  21.516 47.472 21.6 47.496 ;
    END
  END i[311]
  PIN i[312]
    DIRECTION INPUT ;
    USE SIGNAL ;
    PORT
      LAYER M4 ;
        RECT  21.516 47.568 21.6 47.592 ;
    END
  END i[312]
  PIN i[313]
    DIRECTION INPUT ;
    USE SIGNAL ;
    PORT
      LAYER M4 ;
        RECT  21.516 47.664 21.6 47.688 ;
    END
  END i[313]
  PIN i[314]
    DIRECTION INPUT ;
    USE SIGNAL ;
    PORT
      LAYER M4 ;
        RECT  21.516 47.76 21.6 47.784 ;
    END
  END i[314]
  PIN i[315]
    DIRECTION INPUT ;
    USE SIGNAL ;
    PORT
      LAYER M4 ;
        RECT  21.516 47.856 21.6 47.88 ;
    END
  END i[315]
  PIN i[316]
    DIRECTION INPUT ;
    USE SIGNAL ;
    PORT
      LAYER M4 ;
        RECT  21.516 47.952 21.6 47.976 ;
    END
  END i[316]
  PIN i[317]
    DIRECTION INPUT ;
    USE SIGNAL ;
    PORT
      LAYER M4 ;
        RECT  21.516 48.048 21.6 48.072 ;
    END
  END i[317]
  PIN i[318]
    DIRECTION INPUT ;
    USE SIGNAL ;
    PORT
      LAYER M4 ;
        RECT  21.516 48.144 21.6 48.168 ;
    END
  END i[318]
  PIN i[319]
    DIRECTION INPUT ;
    USE SIGNAL ;
    PORT
      LAYER M4 ;
        RECT  21.516 48.24 21.6 48.264 ;
    END
  END i[319]
  PIN i[31]
    DIRECTION INPUT ;
    USE SIGNAL ;
    PORT
      LAYER M4 ;
        RECT  21.516 22.896 21.6 22.92 ;
    END
  END i[31]
  PIN i[320]
    DIRECTION INPUT ;
    USE SIGNAL ;
    PORT
      LAYER M4 ;
        RECT  21.516 48.336 21.6 48.36 ;
    END
  END i[320]
  PIN i[321]
    DIRECTION INPUT ;
    USE SIGNAL ;
    PORT
      LAYER M4 ;
        RECT  21.516 48.432 21.6 48.456 ;
    END
  END i[321]
  PIN i[322]
    DIRECTION INPUT ;
    USE SIGNAL ;
    PORT
      LAYER M4 ;
        RECT  21.516 48.528 21.6 48.552 ;
    END
  END i[322]
  PIN i[323]
    DIRECTION INPUT ;
    USE SIGNAL ;
    PORT
      LAYER M4 ;
        RECT  21.516 48.624 21.6 48.648 ;
    END
  END i[323]
  PIN i[324]
    DIRECTION INPUT ;
    USE SIGNAL ;
    PORT
      LAYER M4 ;
        RECT  21.516 48.72 21.6 48.744 ;
    END
  END i[324]
  PIN i[325]
    DIRECTION INPUT ;
    USE SIGNAL ;
    PORT
      LAYER M4 ;
        RECT  21.516 48.816 21.6 48.84 ;
    END
  END i[325]
  PIN i[326]
    DIRECTION INPUT ;
    USE SIGNAL ;
    PORT
      LAYER M4 ;
        RECT  21.516 48.912 21.6 48.936 ;
    END
  END i[326]
  PIN i[327]
    DIRECTION INPUT ;
    USE SIGNAL ;
    PORT
      LAYER M4 ;
        RECT  21.516 49.008 21.6 49.032 ;
    END
  END i[327]
  PIN i[328]
    DIRECTION INPUT ;
    USE SIGNAL ;
    PORT
      LAYER M4 ;
        RECT  21.516 49.104 21.6 49.128 ;
    END
  END i[328]
  PIN i[329]
    DIRECTION INPUT ;
    USE SIGNAL ;
    PORT
      LAYER M4 ;
        RECT  21.516 49.2 21.6 49.224 ;
    END
  END i[329]
  PIN i[32]
    DIRECTION INPUT ;
    USE SIGNAL ;
    PORT
      LAYER M4 ;
        RECT  21.516 22.992 21.6 23.016 ;
    END
  END i[32]
  PIN i[330]
    DIRECTION INPUT ;
    USE SIGNAL ;
    PORT
      LAYER M4 ;
        RECT  21.516 49.296 21.6 49.32 ;
    END
  END i[330]
  PIN i[331]
    DIRECTION INPUT ;
    USE SIGNAL ;
    PORT
      LAYER M4 ;
        RECT  21.516 49.392 21.6 49.416 ;
    END
  END i[331]
  PIN i[332]
    DIRECTION INPUT ;
    USE SIGNAL ;
    PORT
      LAYER M4 ;
        RECT  21.516 49.488 21.6 49.512 ;
    END
  END i[332]
  PIN i[333]
    DIRECTION INPUT ;
    USE SIGNAL ;
    PORT
      LAYER M4 ;
        RECT  21.516 49.584 21.6 49.608 ;
    END
  END i[333]
  PIN i[334]
    DIRECTION INPUT ;
    USE SIGNAL ;
    PORT
      LAYER M4 ;
        RECT  21.516 49.68 21.6 49.704 ;
    END
  END i[334]
  PIN i[335]
    DIRECTION INPUT ;
    USE SIGNAL ;
    PORT
      LAYER M4 ;
        RECT  21.516 49.776 21.6 49.8 ;
    END
  END i[335]
  PIN i[336]
    DIRECTION INPUT ;
    USE SIGNAL ;
    PORT
      LAYER M4 ;
        RECT  21.516 49.872 21.6 49.896 ;
    END
  END i[336]
  PIN i[337]
    DIRECTION INPUT ;
    USE SIGNAL ;
    PORT
      LAYER M4 ;
        RECT  21.516 49.968 21.6 49.992 ;
    END
  END i[337]
  PIN i[338]
    DIRECTION INPUT ;
    USE SIGNAL ;
    PORT
      LAYER M4 ;
        RECT  21.516 50.064 21.6 50.088 ;
    END
  END i[338]
  PIN i[339]
    DIRECTION INPUT ;
    USE SIGNAL ;
    PORT
      LAYER M4 ;
        RECT  21.516 50.16 21.6 50.184 ;
    END
  END i[339]
  PIN i[33]
    DIRECTION INPUT ;
    USE SIGNAL ;
    PORT
      LAYER M4 ;
        RECT  21.516 23.088 21.6 23.112 ;
    END
  END i[33]
  PIN i[340]
    DIRECTION INPUT ;
    USE SIGNAL ;
    PORT
      LAYER M4 ;
        RECT  21.516 50.256 21.6 50.28 ;
    END
  END i[340]
  PIN i[341]
    DIRECTION INPUT ;
    USE SIGNAL ;
    PORT
      LAYER M4 ;
        RECT  21.516 50.352 21.6 50.376 ;
    END
  END i[341]
  PIN i[342]
    DIRECTION INPUT ;
    USE SIGNAL ;
    PORT
      LAYER M4 ;
        RECT  21.516 50.448 21.6 50.472 ;
    END
  END i[342]
  PIN i[343]
    DIRECTION INPUT ;
    USE SIGNAL ;
    PORT
      LAYER M4 ;
        RECT  21.516 50.544 21.6 50.568 ;
    END
  END i[343]
  PIN i[344]
    DIRECTION INPUT ;
    USE SIGNAL ;
    PORT
      LAYER M4 ;
        RECT  21.516 50.64 21.6 50.664 ;
    END
  END i[344]
  PIN i[345]
    DIRECTION INPUT ;
    USE SIGNAL ;
    PORT
      LAYER M4 ;
        RECT  21.516 50.736 21.6 50.76 ;
    END
  END i[345]
  PIN i[346]
    DIRECTION INPUT ;
    USE SIGNAL ;
    PORT
      LAYER M4 ;
        RECT  21.516 50.832 21.6 50.856 ;
    END
  END i[346]
  PIN i[347]
    DIRECTION INPUT ;
    USE SIGNAL ;
    PORT
      LAYER M4 ;
        RECT  21.516 50.928 21.6 50.952 ;
    END
  END i[347]
  PIN i[348]
    DIRECTION INPUT ;
    USE SIGNAL ;
    PORT
      LAYER M4 ;
        RECT  21.516 51.024 21.6 51.048 ;
    END
  END i[348]
  PIN i[349]
    DIRECTION INPUT ;
    USE SIGNAL ;
    PORT
      LAYER M4 ;
        RECT  21.516 51.12 21.6 51.144 ;
    END
  END i[349]
  PIN i[34]
    DIRECTION INPUT ;
    USE SIGNAL ;
    PORT
      LAYER M4 ;
        RECT  21.516 23.184 21.6 23.208 ;
    END
  END i[34]
  PIN i[350]
    DIRECTION INPUT ;
    USE SIGNAL ;
    PORT
      LAYER M4 ;
        RECT  21.516 51.216 21.6 51.24 ;
    END
  END i[350]
  PIN i[351]
    DIRECTION INPUT ;
    USE SIGNAL ;
    PORT
      LAYER M4 ;
        RECT  21.516 51.312 21.6 51.336 ;
    END
  END i[351]
  PIN i[352]
    DIRECTION INPUT ;
    USE SIGNAL ;
    PORT
      LAYER M4 ;
        RECT  21.516 54.48 21.6 54.504 ;
    END
  END i[352]
  PIN i[353]
    DIRECTION INPUT ;
    USE SIGNAL ;
    PORT
      LAYER M4 ;
        RECT  21.516 54.576 21.6 54.6 ;
    END
  END i[353]
  PIN i[354]
    DIRECTION INPUT ;
    USE SIGNAL ;
    PORT
      LAYER M4 ;
        RECT  21.516 54.672 21.6 54.696 ;
    END
  END i[354]
  PIN i[355]
    DIRECTION INPUT ;
    USE SIGNAL ;
    PORT
      LAYER M4 ;
        RECT  21.516 54.768 21.6 54.792 ;
    END
  END i[355]
  PIN i[356]
    DIRECTION INPUT ;
    USE SIGNAL ;
    PORT
      LAYER M4 ;
        RECT  21.516 54.864 21.6 54.888 ;
    END
  END i[356]
  PIN i[357]
    DIRECTION INPUT ;
    USE SIGNAL ;
    PORT
      LAYER M4 ;
        RECT  21.516 54.96 21.6 54.984 ;
    END
  END i[357]
  PIN i[358]
    DIRECTION INPUT ;
    USE SIGNAL ;
    PORT
      LAYER M4 ;
        RECT  21.516 55.056 21.6 55.08 ;
    END
  END i[358]
  PIN i[359]
    DIRECTION INPUT ;
    USE SIGNAL ;
    PORT
      LAYER M4 ;
        RECT  21.516 55.152 21.6 55.176 ;
    END
  END i[359]
  PIN i[35]
    DIRECTION INPUT ;
    USE SIGNAL ;
    PORT
      LAYER M4 ;
        RECT  21.516 23.28 21.6 23.304 ;
    END
  END i[35]
  PIN i[360]
    DIRECTION INPUT ;
    USE SIGNAL ;
    PORT
      LAYER M4 ;
        RECT  21.516 55.248 21.6 55.272 ;
    END
  END i[360]
  PIN i[361]
    DIRECTION INPUT ;
    USE SIGNAL ;
    PORT
      LAYER M4 ;
        RECT  21.516 55.344 21.6 55.368 ;
    END
  END i[361]
  PIN i[362]
    DIRECTION INPUT ;
    USE SIGNAL ;
    PORT
      LAYER M4 ;
        RECT  21.516 55.44 21.6 55.464 ;
    END
  END i[362]
  PIN i[363]
    DIRECTION INPUT ;
    USE SIGNAL ;
    PORT
      LAYER M4 ;
        RECT  21.516 55.536 21.6 55.56 ;
    END
  END i[363]
  PIN i[364]
    DIRECTION INPUT ;
    USE SIGNAL ;
    PORT
      LAYER M4 ;
        RECT  21.516 55.632 21.6 55.656 ;
    END
  END i[364]
  PIN i[365]
    DIRECTION INPUT ;
    USE SIGNAL ;
    PORT
      LAYER M4 ;
        RECT  21.516 55.728 21.6 55.752 ;
    END
  END i[365]
  PIN i[366]
    DIRECTION INPUT ;
    USE SIGNAL ;
    PORT
      LAYER M4 ;
        RECT  21.516 55.824 21.6 55.848 ;
    END
  END i[366]
  PIN i[367]
    DIRECTION INPUT ;
    USE SIGNAL ;
    PORT
      LAYER M4 ;
        RECT  21.516 55.92 21.6 55.944 ;
    END
  END i[367]
  PIN i[368]
    DIRECTION INPUT ;
    USE SIGNAL ;
    PORT
      LAYER M4 ;
        RECT  21.516 56.016 21.6 56.04 ;
    END
  END i[368]
  PIN i[369]
    DIRECTION INPUT ;
    USE SIGNAL ;
    PORT
      LAYER M4 ;
        RECT  21.516 56.112 21.6 56.136 ;
    END
  END i[369]
  PIN i[36]
    DIRECTION INPUT ;
    USE SIGNAL ;
    PORT
      LAYER M4 ;
        RECT  21.516 23.376 21.6 23.4 ;
    END
  END i[36]
  PIN i[370]
    DIRECTION INPUT ;
    USE SIGNAL ;
    PORT
      LAYER M4 ;
        RECT  21.516 56.208 21.6 56.232 ;
    END
  END i[370]
  PIN i[371]
    DIRECTION INPUT ;
    USE SIGNAL ;
    PORT
      LAYER M4 ;
        RECT  21.516 56.304 21.6 56.328 ;
    END
  END i[371]
  PIN i[372]
    DIRECTION INPUT ;
    USE SIGNAL ;
    PORT
      LAYER M4 ;
        RECT  21.516 56.4 21.6 56.424 ;
    END
  END i[372]
  PIN i[373]
    DIRECTION INPUT ;
    USE SIGNAL ;
    PORT
      LAYER M4 ;
        RECT  21.516 56.496 21.6 56.52 ;
    END
  END i[373]
  PIN i[374]
    DIRECTION INPUT ;
    USE SIGNAL ;
    PORT
      LAYER M4 ;
        RECT  21.516 56.592 21.6 56.616 ;
    END
  END i[374]
  PIN i[375]
    DIRECTION INPUT ;
    USE SIGNAL ;
    PORT
      LAYER M4 ;
        RECT  21.516 56.688 21.6 56.712 ;
    END
  END i[375]
  PIN i[376]
    DIRECTION INPUT ;
    USE SIGNAL ;
    PORT
      LAYER M4 ;
        RECT  21.516 56.784 21.6 56.808 ;
    END
  END i[376]
  PIN i[377]
    DIRECTION INPUT ;
    USE SIGNAL ;
    PORT
      LAYER M4 ;
        RECT  21.516 56.88 21.6 56.904 ;
    END
  END i[377]
  PIN i[378]
    DIRECTION INPUT ;
    USE SIGNAL ;
    PORT
      LAYER M4 ;
        RECT  21.516 56.976 21.6 57 ;
    END
  END i[378]
  PIN i[379]
    DIRECTION INPUT ;
    USE SIGNAL ;
    PORT
      LAYER M4 ;
        RECT  21.516 57.072 21.6 57.096 ;
    END
  END i[379]
  PIN i[37]
    DIRECTION INPUT ;
    USE SIGNAL ;
    PORT
      LAYER M4 ;
        RECT  21.516 23.472 21.6 23.496 ;
    END
  END i[37]
  PIN i[380]
    DIRECTION INPUT ;
    USE SIGNAL ;
    PORT
      LAYER M4 ;
        RECT  21.516 57.168 21.6 57.192 ;
    END
  END i[380]
  PIN i[381]
    DIRECTION INPUT ;
    USE SIGNAL ;
    PORT
      LAYER M4 ;
        RECT  21.516 57.264 21.6 57.288 ;
    END
  END i[381]
  PIN i[382]
    DIRECTION INPUT ;
    USE SIGNAL ;
    PORT
      LAYER M4 ;
        RECT  21.516 57.36 21.6 57.384 ;
    END
  END i[382]
  PIN i[383]
    DIRECTION INPUT ;
    USE SIGNAL ;
    PORT
      LAYER M4 ;
        RECT  21.516 57.456 21.6 57.48 ;
    END
  END i[383]
  PIN i[384]
    DIRECTION INPUT ;
    USE SIGNAL ;
    PORT
      LAYER M4 ;
        RECT  21.516 42.192 21.6 42.216 ;
    END
  END i[384]
  PIN i[385]
    DIRECTION INPUT ;
    USE SIGNAL ;
    PORT
      LAYER M4 ;
        RECT  21.516 42.288 21.6 42.312 ;
    END
  END i[385]
  PIN i[386]
    DIRECTION INPUT ;
    USE SIGNAL ;
    PORT
      LAYER M4 ;
        RECT  21.516 42.384 21.6 42.408 ;
    END
  END i[386]
  PIN i[387]
    DIRECTION INPUT ;
    USE SIGNAL ;
    PORT
      LAYER M4 ;
        RECT  21.516 42.48 21.6 42.504 ;
    END
  END i[387]
  PIN i[388]
    DIRECTION INPUT ;
    USE SIGNAL ;
    PORT
      LAYER M4 ;
        RECT  21.516 42.576 21.6 42.6 ;
    END
  END i[388]
  PIN i[389]
    DIRECTION INPUT ;
    USE SIGNAL ;
    PORT
      LAYER M4 ;
        RECT  21.516 42.672 21.6 42.696 ;
    END
  END i[389]
  PIN i[38]
    DIRECTION INPUT ;
    USE SIGNAL ;
    PORT
      LAYER M4 ;
        RECT  21.516 23.568 21.6 23.592 ;
    END
  END i[38]
  PIN i[390]
    DIRECTION INPUT ;
    USE SIGNAL ;
    PORT
      LAYER M4 ;
        RECT  21.516 42.768 21.6 42.792 ;
    END
  END i[390]
  PIN i[391]
    DIRECTION INPUT ;
    USE SIGNAL ;
    PORT
      LAYER M4 ;
        RECT  21.516 42.864 21.6 42.888 ;
    END
  END i[391]
  PIN i[392]
    DIRECTION INPUT ;
    USE SIGNAL ;
    PORT
      LAYER M4 ;
        RECT  21.516 42.96 21.6 42.984 ;
    END
  END i[392]
  PIN i[393]
    DIRECTION INPUT ;
    USE SIGNAL ;
    PORT
      LAYER M4 ;
        RECT  21.516 43.056 21.6 43.08 ;
    END
  END i[393]
  PIN i[394]
    DIRECTION INPUT ;
    USE SIGNAL ;
    PORT
      LAYER M4 ;
        RECT  21.516 43.152 21.6 43.176 ;
    END
  END i[394]
  PIN i[395]
    DIRECTION INPUT ;
    USE SIGNAL ;
    PORT
      LAYER M4 ;
        RECT  21.516 43.248 21.6 43.272 ;
    END
  END i[395]
  PIN i[396]
    DIRECTION INPUT ;
    USE SIGNAL ;
    PORT
      LAYER M4 ;
        RECT  21.516 43.344 21.6 43.368 ;
    END
  END i[396]
  PIN i[397]
    DIRECTION INPUT ;
    USE SIGNAL ;
    PORT
      LAYER M4 ;
        RECT  21.516 43.44 21.6 43.464 ;
    END
  END i[397]
  PIN i[398]
    DIRECTION INPUT ;
    USE SIGNAL ;
    PORT
      LAYER M4 ;
        RECT  21.516 43.536 21.6 43.56 ;
    END
  END i[398]
  PIN i[399]
    DIRECTION INPUT ;
    USE SIGNAL ;
    PORT
      LAYER M4 ;
        RECT  21.516 43.632 21.6 43.656 ;
    END
  END i[399]
  PIN i[39]
    DIRECTION INPUT ;
    USE SIGNAL ;
    PORT
      LAYER M4 ;
        RECT  21.516 23.664 21.6 23.688 ;
    END
  END i[39]
  PIN i[3]
    DIRECTION INPUT ;
    USE SIGNAL ;
    PORT
      LAYER M4 ;
        RECT  21.516 20.208 21.6 20.232 ;
    END
  END i[3]
  PIN i[400]
    DIRECTION INPUT ;
    USE SIGNAL ;
    PORT
      LAYER M4 ;
        RECT  21.516 43.728 21.6 43.752 ;
    END
  END i[400]
  PIN i[401]
    DIRECTION INPUT ;
    USE SIGNAL ;
    PORT
      LAYER M4 ;
        RECT  21.516 43.824 21.6 43.848 ;
    END
  END i[401]
  PIN i[402]
    DIRECTION INPUT ;
    USE SIGNAL ;
    PORT
      LAYER M4 ;
        RECT  21.516 43.92 21.6 43.944 ;
    END
  END i[402]
  PIN i[403]
    DIRECTION INPUT ;
    USE SIGNAL ;
    PORT
      LAYER M4 ;
        RECT  21.516 44.016 21.6 44.04 ;
    END
  END i[403]
  PIN i[404]
    DIRECTION INPUT ;
    USE SIGNAL ;
    PORT
      LAYER M4 ;
        RECT  21.516 44.112 21.6 44.136 ;
    END
  END i[404]
  PIN i[405]
    DIRECTION INPUT ;
    USE SIGNAL ;
    PORT
      LAYER M4 ;
        RECT  21.516 44.208 21.6 44.232 ;
    END
  END i[405]
  PIN i[406]
    DIRECTION INPUT ;
    USE SIGNAL ;
    PORT
      LAYER M4 ;
        RECT  21.516 44.304 21.6 44.328 ;
    END
  END i[406]
  PIN i[407]
    DIRECTION INPUT ;
    USE SIGNAL ;
    PORT
      LAYER M4 ;
        RECT  21.516 44.4 21.6 44.424 ;
    END
  END i[407]
  PIN i[408]
    DIRECTION INPUT ;
    USE SIGNAL ;
    PORT
      LAYER M4 ;
        RECT  21.516 44.496 21.6 44.52 ;
    END
  END i[408]
  PIN i[409]
    DIRECTION INPUT ;
    USE SIGNAL ;
    PORT
      LAYER M4 ;
        RECT  21.516 44.592 21.6 44.616 ;
    END
  END i[409]
  PIN i[40]
    DIRECTION INPUT ;
    USE SIGNAL ;
    PORT
      LAYER M4 ;
        RECT  21.516 23.76 21.6 23.784 ;
    END
  END i[40]
  PIN i[410]
    DIRECTION INPUT ;
    USE SIGNAL ;
    PORT
      LAYER M4 ;
        RECT  21.516 44.688 21.6 44.712 ;
    END
  END i[410]
  PIN i[411]
    DIRECTION INPUT ;
    USE SIGNAL ;
    PORT
      LAYER M4 ;
        RECT  21.516 44.784 21.6 44.808 ;
    END
  END i[411]
  PIN i[412]
    DIRECTION INPUT ;
    USE SIGNAL ;
    PORT
      LAYER M4 ;
        RECT  21.516 44.88 21.6 44.904 ;
    END
  END i[412]
  PIN i[413]
    DIRECTION INPUT ;
    USE SIGNAL ;
    PORT
      LAYER M4 ;
        RECT  21.516 44.976 21.6 45 ;
    END
  END i[413]
  PIN i[414]
    DIRECTION INPUT ;
    USE SIGNAL ;
    PORT
      LAYER M4 ;
        RECT  21.516 45.072 21.6 45.096 ;
    END
  END i[414]
  PIN i[415]
    DIRECTION INPUT ;
    USE SIGNAL ;
    PORT
      LAYER M4 ;
        RECT  21.516 45.168 21.6 45.192 ;
    END
  END i[415]
  PIN i[416]
    DIRECTION INPUT ;
    USE SIGNAL ;
    PORT
      LAYER M4 ;
        RECT  21.516 51.408 21.6 51.432 ;
    END
  END i[416]
  PIN i[417]
    DIRECTION INPUT ;
    USE SIGNAL ;
    PORT
      LAYER M4 ;
        RECT  21.516 51.504 21.6 51.528 ;
    END
  END i[417]
  PIN i[418]
    DIRECTION INPUT ;
    USE SIGNAL ;
    PORT
      LAYER M4 ;
        RECT  21.516 51.6 21.6 51.624 ;
    END
  END i[418]
  PIN i[419]
    DIRECTION INPUT ;
    USE SIGNAL ;
    PORT
      LAYER M4 ;
        RECT  21.516 51.696 21.6 51.72 ;
    END
  END i[419]
  PIN i[41]
    DIRECTION INPUT ;
    USE SIGNAL ;
    PORT
      LAYER M4 ;
        RECT  21.516 23.856 21.6 23.88 ;
    END
  END i[41]
  PIN i[420]
    DIRECTION INPUT ;
    USE SIGNAL ;
    PORT
      LAYER M4 ;
        RECT  21.516 51.792 21.6 51.816 ;
    END
  END i[420]
  PIN i[421]
    DIRECTION INPUT ;
    USE SIGNAL ;
    PORT
      LAYER M4 ;
        RECT  21.516 51.888 21.6 51.912 ;
    END
  END i[421]
  PIN i[422]
    DIRECTION INPUT ;
    USE SIGNAL ;
    PORT
      LAYER M4 ;
        RECT  21.516 51.984 21.6 52.008 ;
    END
  END i[422]
  PIN i[423]
    DIRECTION INPUT ;
    USE SIGNAL ;
    PORT
      LAYER M4 ;
        RECT  21.516 52.08 21.6 52.104 ;
    END
  END i[423]
  PIN i[424]
    DIRECTION INPUT ;
    USE SIGNAL ;
    PORT
      LAYER M4 ;
        RECT  21.516 52.176 21.6 52.2 ;
    END
  END i[424]
  PIN i[425]
    DIRECTION INPUT ;
    USE SIGNAL ;
    PORT
      LAYER M4 ;
        RECT  21.516 52.272 21.6 52.296 ;
    END
  END i[425]
  PIN i[426]
    DIRECTION INPUT ;
    USE SIGNAL ;
    PORT
      LAYER M4 ;
        RECT  21.516 52.368 21.6 52.392 ;
    END
  END i[426]
  PIN i[427]
    DIRECTION INPUT ;
    USE SIGNAL ;
    PORT
      LAYER M4 ;
        RECT  21.516 52.464 21.6 52.488 ;
    END
  END i[427]
  PIN i[428]
    DIRECTION INPUT ;
    USE SIGNAL ;
    PORT
      LAYER M4 ;
        RECT  21.516 52.56 21.6 52.584 ;
    END
  END i[428]
  PIN i[429]
    DIRECTION INPUT ;
    USE SIGNAL ;
    PORT
      LAYER M4 ;
        RECT  21.516 52.656 21.6 52.68 ;
    END
  END i[429]
  PIN i[42]
    DIRECTION INPUT ;
    USE SIGNAL ;
    PORT
      LAYER M4 ;
        RECT  21.516 23.952 21.6 23.976 ;
    END
  END i[42]
  PIN i[430]
    DIRECTION INPUT ;
    USE SIGNAL ;
    PORT
      LAYER M4 ;
        RECT  21.516 52.752 21.6 52.776 ;
    END
  END i[430]
  PIN i[431]
    DIRECTION INPUT ;
    USE SIGNAL ;
    PORT
      LAYER M4 ;
        RECT  21.516 52.848 21.6 52.872 ;
    END
  END i[431]
  PIN i[432]
    DIRECTION INPUT ;
    USE SIGNAL ;
    PORT
      LAYER M4 ;
        RECT  21.516 52.944 21.6 52.968 ;
    END
  END i[432]
  PIN i[433]
    DIRECTION INPUT ;
    USE SIGNAL ;
    PORT
      LAYER M4 ;
        RECT  21.516 53.04 21.6 53.064 ;
    END
  END i[433]
  PIN i[434]
    DIRECTION INPUT ;
    USE SIGNAL ;
    PORT
      LAYER M4 ;
        RECT  21.516 53.136 21.6 53.16 ;
    END
  END i[434]
  PIN i[435]
    DIRECTION INPUT ;
    USE SIGNAL ;
    PORT
      LAYER M4 ;
        RECT  21.516 53.232 21.6 53.256 ;
    END
  END i[435]
  PIN i[436]
    DIRECTION INPUT ;
    USE SIGNAL ;
    PORT
      LAYER M4 ;
        RECT  21.516 53.328 21.6 53.352 ;
    END
  END i[436]
  PIN i[437]
    DIRECTION INPUT ;
    USE SIGNAL ;
    PORT
      LAYER M4 ;
        RECT  21.516 53.424 21.6 53.448 ;
    END
  END i[437]
  PIN i[438]
    DIRECTION INPUT ;
    USE SIGNAL ;
    PORT
      LAYER M4 ;
        RECT  21.516 53.52 21.6 53.544 ;
    END
  END i[438]
  PIN i[439]
    DIRECTION INPUT ;
    USE SIGNAL ;
    PORT
      LAYER M4 ;
        RECT  21.516 53.616 21.6 53.64 ;
    END
  END i[439]
  PIN i[43]
    DIRECTION INPUT ;
    USE SIGNAL ;
    PORT
      LAYER M4 ;
        RECT  21.516 24.048 21.6 24.072 ;
    END
  END i[43]
  PIN i[440]
    DIRECTION INPUT ;
    USE SIGNAL ;
    PORT
      LAYER M4 ;
        RECT  21.516 53.712 21.6 53.736 ;
    END
  END i[440]
  PIN i[441]
    DIRECTION INPUT ;
    USE SIGNAL ;
    PORT
      LAYER M4 ;
        RECT  21.516 53.808 21.6 53.832 ;
    END
  END i[441]
  PIN i[442]
    DIRECTION INPUT ;
    USE SIGNAL ;
    PORT
      LAYER M4 ;
        RECT  21.516 53.904 21.6 53.928 ;
    END
  END i[442]
  PIN i[443]
    DIRECTION INPUT ;
    USE SIGNAL ;
    PORT
      LAYER M4 ;
        RECT  21.516 54 21.6 54.024 ;
    END
  END i[443]
  PIN i[444]
    DIRECTION INPUT ;
    USE SIGNAL ;
    PORT
      LAYER M4 ;
        RECT  21.516 54.096 21.6 54.12 ;
    END
  END i[444]
  PIN i[445]
    DIRECTION INPUT ;
    USE SIGNAL ;
    PORT
      LAYER M4 ;
        RECT  21.516 54.192 21.6 54.216 ;
    END
  END i[445]
  PIN i[446]
    DIRECTION INPUT ;
    USE SIGNAL ;
    PORT
      LAYER M4 ;
        RECT  21.516 54.288 21.6 54.312 ;
    END
  END i[446]
  PIN i[447]
    DIRECTION INPUT ;
    USE SIGNAL ;
    PORT
      LAYER M4 ;
        RECT  21.516 54.384 21.6 54.408 ;
    END
  END i[447]
  PIN i[448]
    DIRECTION INPUT ;
    USE SIGNAL ;
    PORT
      LAYER M4 ;
        RECT  21.516 58.32 21.6 58.344 ;
    END
  END i[448]
  PIN i[449]
    DIRECTION INPUT ;
    USE SIGNAL ;
    PORT
      LAYER M4 ;
        RECT  21.516 58.416 21.6 58.44 ;
    END
  END i[449]
  PIN i[44]
    DIRECTION INPUT ;
    USE SIGNAL ;
    PORT
      LAYER M4 ;
        RECT  21.516 24.144 21.6 24.168 ;
    END
  END i[44]
  PIN i[450]
    DIRECTION INPUT ;
    USE SIGNAL ;
    PORT
      LAYER M4 ;
        RECT  21.516 58.512 21.6 58.536 ;
    END
  END i[450]
  PIN i[451]
    DIRECTION INPUT ;
    USE SIGNAL ;
    PORT
      LAYER M4 ;
        RECT  21.516 58.608 21.6 58.632 ;
    END
  END i[451]
  PIN i[452]
    DIRECTION INPUT ;
    USE SIGNAL ;
    PORT
      LAYER M4 ;
        RECT  21.516 58.704 21.6 58.728 ;
    END
  END i[452]
  PIN i[453]
    DIRECTION INPUT ;
    USE SIGNAL ;
    PORT
      LAYER M4 ;
        RECT  21.516 58.8 21.6 58.824 ;
    END
  END i[453]
  PIN i[454]
    DIRECTION INPUT ;
    USE SIGNAL ;
    PORT
      LAYER M4 ;
        RECT  21.516 58.896 21.6 58.92 ;
    END
  END i[454]
  PIN i[455]
    DIRECTION INPUT ;
    USE SIGNAL ;
    PORT
      LAYER M4 ;
        RECT  21.516 58.992 21.6 59.016 ;
    END
  END i[455]
  PIN i[456]
    DIRECTION INPUT ;
    USE SIGNAL ;
    PORT
      LAYER M4 ;
        RECT  21.516 59.088 21.6 59.112 ;
    END
  END i[456]
  PIN i[457]
    DIRECTION INPUT ;
    USE SIGNAL ;
    PORT
      LAYER M4 ;
        RECT  21.516 59.184 21.6 59.208 ;
    END
  END i[457]
  PIN i[458]
    DIRECTION INPUT ;
    USE SIGNAL ;
    PORT
      LAYER M4 ;
        RECT  21.516 59.28 21.6 59.304 ;
    END
  END i[458]
  PIN i[459]
    DIRECTION INPUT ;
    USE SIGNAL ;
    PORT
      LAYER M4 ;
        RECT  21.516 59.376 21.6 59.4 ;
    END
  END i[459]
  PIN i[45]
    DIRECTION INPUT ;
    USE SIGNAL ;
    PORT
      LAYER M4 ;
        RECT  21.516 24.24 21.6 24.264 ;
    END
  END i[45]
  PIN i[460]
    DIRECTION INPUT ;
    USE SIGNAL ;
    PORT
      LAYER M4 ;
        RECT  21.516 59.472 21.6 59.496 ;
    END
  END i[460]
  PIN i[461]
    DIRECTION INPUT ;
    USE SIGNAL ;
    PORT
      LAYER M4 ;
        RECT  21.516 59.568 21.6 59.592 ;
    END
  END i[461]
  PIN i[462]
    DIRECTION INPUT ;
    USE SIGNAL ;
    PORT
      LAYER M4 ;
        RECT  21.516 59.664 21.6 59.688 ;
    END
  END i[462]
  PIN i[463]
    DIRECTION INPUT ;
    USE SIGNAL ;
    PORT
      LAYER M4 ;
        RECT  21.516 59.76 21.6 59.784 ;
    END
  END i[463]
  PIN i[464]
    DIRECTION INPUT ;
    USE SIGNAL ;
    PORT
      LAYER M4 ;
        RECT  21.516 59.856 21.6 59.88 ;
    END
  END i[464]
  PIN i[465]
    DIRECTION INPUT ;
    USE SIGNAL ;
    PORT
      LAYER M4 ;
        RECT  21.516 59.952 21.6 59.976 ;
    END
  END i[465]
  PIN i[466]
    DIRECTION INPUT ;
    USE SIGNAL ;
    PORT
      LAYER M4 ;
        RECT  21.516 60.048 21.6 60.072 ;
    END
  END i[466]
  PIN i[467]
    DIRECTION INPUT ;
    USE SIGNAL ;
    PORT
      LAYER M4 ;
        RECT  21.516 60.144 21.6 60.168 ;
    END
  END i[467]
  PIN i[468]
    DIRECTION INPUT ;
    USE SIGNAL ;
    PORT
      LAYER M4 ;
        RECT  21.516 60.24 21.6 60.264 ;
    END
  END i[468]
  PIN i[469]
    DIRECTION INPUT ;
    USE SIGNAL ;
    PORT
      LAYER M4 ;
        RECT  21.516 60.336 21.6 60.36 ;
    END
  END i[469]
  PIN i[46]
    DIRECTION INPUT ;
    USE SIGNAL ;
    PORT
      LAYER M4 ;
        RECT  21.516 24.336 21.6 24.36 ;
    END
  END i[46]
  PIN i[470]
    DIRECTION INPUT ;
    USE SIGNAL ;
    PORT
      LAYER M4 ;
        RECT  21.516 60.432 21.6 60.456 ;
    END
  END i[470]
  PIN i[471]
    DIRECTION INPUT ;
    USE SIGNAL ;
    PORT
      LAYER M4 ;
        RECT  21.516 60.528 21.6 60.552 ;
    END
  END i[471]
  PIN i[472]
    DIRECTION INPUT ;
    USE SIGNAL ;
    PORT
      LAYER M4 ;
        RECT  21.516 60.624 21.6 60.648 ;
    END
  END i[472]
  PIN i[473]
    DIRECTION INPUT ;
    USE SIGNAL ;
    PORT
      LAYER M4 ;
        RECT  21.516 60.72 21.6 60.744 ;
    END
  END i[473]
  PIN i[474]
    DIRECTION INPUT ;
    USE SIGNAL ;
    PORT
      LAYER M4 ;
        RECT  21.516 60.816 21.6 60.84 ;
    END
  END i[474]
  PIN i[475]
    DIRECTION INPUT ;
    USE SIGNAL ;
    PORT
      LAYER M4 ;
        RECT  21.516 60.912 21.6 60.936 ;
    END
  END i[475]
  PIN i[476]
    DIRECTION INPUT ;
    USE SIGNAL ;
    PORT
      LAYER M4 ;
        RECT  21.516 61.008 21.6 61.032 ;
    END
  END i[476]
  PIN i[477]
    DIRECTION INPUT ;
    USE SIGNAL ;
    PORT
      LAYER M4 ;
        RECT  21.516 61.104 21.6 61.128 ;
    END
  END i[477]
  PIN i[478]
    DIRECTION INPUT ;
    USE SIGNAL ;
    PORT
      LAYER M4 ;
        RECT  21.516 61.2 21.6 61.224 ;
    END
  END i[478]
  PIN i[479]
    DIRECTION INPUT ;
    USE SIGNAL ;
    PORT
      LAYER M4 ;
        RECT  21.516 61.296 21.6 61.32 ;
    END
  END i[479]
  PIN i[47]
    DIRECTION INPUT ;
    USE SIGNAL ;
    PORT
      LAYER M4 ;
        RECT  21.516 24.432 21.6 24.456 ;
    END
  END i[47]
  PIN i[480]
    DIRECTION INPUT ;
    USE SIGNAL ;
    PORT
      LAYER M4 ;
        RECT  21.516 16.08 21.6 16.104 ;
    END
  END i[480]
  PIN i[481]
    DIRECTION INPUT ;
    USE SIGNAL ;
    PORT
      LAYER M4 ;
        RECT  21.516 16.176 21.6 16.2 ;
    END
  END i[481]
  PIN i[482]
    DIRECTION INPUT ;
    USE SIGNAL ;
    PORT
      LAYER M4 ;
        RECT  21.516 16.272 21.6 16.296 ;
    END
  END i[482]
  PIN i[483]
    DIRECTION INPUT ;
    USE SIGNAL ;
    PORT
      LAYER M4 ;
        RECT  21.516 16.368 21.6 16.392 ;
    END
  END i[483]
  PIN i[484]
    DIRECTION INPUT ;
    USE SIGNAL ;
    PORT
      LAYER M4 ;
        RECT  21.516 16.464 21.6 16.488 ;
    END
  END i[484]
  PIN i[485]
    DIRECTION INPUT ;
    USE SIGNAL ;
    PORT
      LAYER M4 ;
        RECT  21.516 16.56 21.6 16.584 ;
    END
  END i[485]
  PIN i[486]
    DIRECTION INPUT ;
    USE SIGNAL ;
    PORT
      LAYER M4 ;
        RECT  21.516 16.656 21.6 16.68 ;
    END
  END i[486]
  PIN i[487]
    DIRECTION INPUT ;
    USE SIGNAL ;
    PORT
      LAYER M4 ;
        RECT  21.516 16.752 21.6 16.776 ;
    END
  END i[487]
  PIN i[488]
    DIRECTION INPUT ;
    USE SIGNAL ;
    PORT
      LAYER M4 ;
        RECT  21.516 16.848 21.6 16.872 ;
    END
  END i[488]
  PIN i[489]
    DIRECTION INPUT ;
    USE SIGNAL ;
    PORT
      LAYER M4 ;
        RECT  21.516 16.944 21.6 16.968 ;
    END
  END i[489]
  PIN i[48]
    DIRECTION INPUT ;
    USE SIGNAL ;
    PORT
      LAYER M4 ;
        RECT  21.516 24.528 21.6 24.552 ;
    END
  END i[48]
  PIN i[490]
    DIRECTION INPUT ;
    USE SIGNAL ;
    PORT
      LAYER M4 ;
        RECT  21.516 17.04 21.6 17.064 ;
    END
  END i[490]
  PIN i[491]
    DIRECTION INPUT ;
    USE SIGNAL ;
    PORT
      LAYER M4 ;
        RECT  21.516 17.136 21.6 17.16 ;
    END
  END i[491]
  PIN i[492]
    DIRECTION INPUT ;
    USE SIGNAL ;
    PORT
      LAYER M4 ;
        RECT  21.516 17.232 21.6 17.256 ;
    END
  END i[492]
  PIN i[493]
    DIRECTION INPUT ;
    USE SIGNAL ;
    PORT
      LAYER M4 ;
        RECT  21.516 17.328 21.6 17.352 ;
    END
  END i[493]
  PIN i[494]
    DIRECTION INPUT ;
    USE SIGNAL ;
    PORT
      LAYER M4 ;
        RECT  21.516 17.424 21.6 17.448 ;
    END
  END i[494]
  PIN i[495]
    DIRECTION INPUT ;
    USE SIGNAL ;
    PORT
      LAYER M4 ;
        RECT  21.516 17.52 21.6 17.544 ;
    END
  END i[495]
  PIN i[496]
    DIRECTION INPUT ;
    USE SIGNAL ;
    PORT
      LAYER M4 ;
        RECT  21.516 17.616 21.6 17.64 ;
    END
  END i[496]
  PIN i[497]
    DIRECTION INPUT ;
    USE SIGNAL ;
    PORT
      LAYER M4 ;
        RECT  21.516 17.712 21.6 17.736 ;
    END
  END i[497]
  PIN i[498]
    DIRECTION INPUT ;
    USE SIGNAL ;
    PORT
      LAYER M4 ;
        RECT  21.516 17.808 21.6 17.832 ;
    END
  END i[498]
  PIN i[499]
    DIRECTION INPUT ;
    USE SIGNAL ;
    PORT
      LAYER M4 ;
        RECT  21.516 17.904 21.6 17.928 ;
    END
  END i[499]
  PIN i[49]
    DIRECTION INPUT ;
    USE SIGNAL ;
    PORT
      LAYER M4 ;
        RECT  21.516 24.624 21.6 24.648 ;
    END
  END i[49]
  PIN i[4]
    DIRECTION INPUT ;
    USE SIGNAL ;
    PORT
      LAYER M4 ;
        RECT  21.516 20.304 21.6 20.328 ;
    END
  END i[4]
  PIN i[500]
    DIRECTION INPUT ;
    USE SIGNAL ;
    PORT
      LAYER M4 ;
        RECT  21.516 18 21.6 18.024 ;
    END
  END i[500]
  PIN i[501]
    DIRECTION INPUT ;
    USE SIGNAL ;
    PORT
      LAYER M4 ;
        RECT  21.516 18.096 21.6 18.12 ;
    END
  END i[501]
  PIN i[502]
    DIRECTION INPUT ;
    USE SIGNAL ;
    PORT
      LAYER M4 ;
        RECT  21.516 18.192 21.6 18.216 ;
    END
  END i[502]
  PIN i[503]
    DIRECTION INPUT ;
    USE SIGNAL ;
    PORT
      LAYER M4 ;
        RECT  21.516 18.288 21.6 18.312 ;
    END
  END i[503]
  PIN i[504]
    DIRECTION INPUT ;
    USE SIGNAL ;
    PORT
      LAYER M4 ;
        RECT  21.516 18.384 21.6 18.408 ;
    END
  END i[504]
  PIN i[505]
    DIRECTION INPUT ;
    USE SIGNAL ;
    PORT
      LAYER M4 ;
        RECT  21.516 18.48 21.6 18.504 ;
    END
  END i[505]
  PIN i[506]
    DIRECTION INPUT ;
    USE SIGNAL ;
    PORT
      LAYER M4 ;
        RECT  21.516 18.576 21.6 18.6 ;
    END
  END i[506]
  PIN i[507]
    DIRECTION INPUT ;
    USE SIGNAL ;
    PORT
      LAYER M4 ;
        RECT  21.516 18.672 21.6 18.696 ;
    END
  END i[507]
  PIN i[508]
    DIRECTION INPUT ;
    USE SIGNAL ;
    PORT
      LAYER M4 ;
        RECT  21.516 18.768 21.6 18.792 ;
    END
  END i[508]
  PIN i[509]
    DIRECTION INPUT ;
    USE SIGNAL ;
    PORT
      LAYER M4 ;
        RECT  21.516 18.864 21.6 18.888 ;
    END
  END i[509]
  PIN i[50]
    DIRECTION INPUT ;
    USE SIGNAL ;
    PORT
      LAYER M4 ;
        RECT  21.516 24.72 21.6 24.744 ;
    END
  END i[50]
  PIN i[510]
    DIRECTION INPUT ;
    USE SIGNAL ;
    PORT
      LAYER M4 ;
        RECT  21.516 18.96 21.6 18.984 ;
    END
  END i[510]
  PIN i[511]
    DIRECTION INPUT ;
    USE SIGNAL ;
    PORT
      LAYER M4 ;
        RECT  21.516 19.056 21.6 19.08 ;
    END
  END i[511]
  PIN i[512]
    DIRECTION INPUT ;
    USE SIGNAL ;
    PORT
      LAYER M4 ;
        RECT  21.516 9.936 21.6 9.96 ;
    END
  END i[512]
  PIN i[513]
    DIRECTION INPUT ;
    USE SIGNAL ;
    PORT
      LAYER M4 ;
        RECT  21.516 10.032 21.6 10.056 ;
    END
  END i[513]
  PIN i[514]
    DIRECTION INPUT ;
    USE SIGNAL ;
    PORT
      LAYER M4 ;
        RECT  21.516 10.128 21.6 10.152 ;
    END
  END i[514]
  PIN i[515]
    DIRECTION INPUT ;
    USE SIGNAL ;
    PORT
      LAYER M4 ;
        RECT  21.516 10.224 21.6 10.248 ;
    END
  END i[515]
  PIN i[516]
    DIRECTION INPUT ;
    USE SIGNAL ;
    PORT
      LAYER M4 ;
        RECT  21.516 10.32 21.6 10.344 ;
    END
  END i[516]
  PIN i[517]
    DIRECTION INPUT ;
    USE SIGNAL ;
    PORT
      LAYER M4 ;
        RECT  21.516 10.416 21.6 10.44 ;
    END
  END i[517]
  PIN i[518]
    DIRECTION INPUT ;
    USE SIGNAL ;
    PORT
      LAYER M4 ;
        RECT  21.516 10.512 21.6 10.536 ;
    END
  END i[518]
  PIN i[519]
    DIRECTION INPUT ;
    USE SIGNAL ;
    PORT
      LAYER M4 ;
        RECT  21.516 10.608 21.6 10.632 ;
    END
  END i[519]
  PIN i[51]
    DIRECTION INPUT ;
    USE SIGNAL ;
    PORT
      LAYER M4 ;
        RECT  21.516 24.816 21.6 24.84 ;
    END
  END i[51]
  PIN i[520]
    DIRECTION INPUT ;
    USE SIGNAL ;
    PORT
      LAYER M4 ;
        RECT  21.516 10.704 21.6 10.728 ;
    END
  END i[520]
  PIN i[521]
    DIRECTION INPUT ;
    USE SIGNAL ;
    PORT
      LAYER M4 ;
        RECT  21.516 10.8 21.6 10.824 ;
    END
  END i[521]
  PIN i[522]
    DIRECTION INPUT ;
    USE SIGNAL ;
    PORT
      LAYER M4 ;
        RECT  21.516 10.896 21.6 10.92 ;
    END
  END i[522]
  PIN i[523]
    DIRECTION INPUT ;
    USE SIGNAL ;
    PORT
      LAYER M4 ;
        RECT  21.516 10.992 21.6 11.016 ;
    END
  END i[523]
  PIN i[524]
    DIRECTION INPUT ;
    USE SIGNAL ;
    PORT
      LAYER M4 ;
        RECT  21.516 11.088 21.6 11.112 ;
    END
  END i[524]
  PIN i[525]
    DIRECTION INPUT ;
    USE SIGNAL ;
    PORT
      LAYER M4 ;
        RECT  21.516 11.184 21.6 11.208 ;
    END
  END i[525]
  PIN i[526]
    DIRECTION INPUT ;
    USE SIGNAL ;
    PORT
      LAYER M4 ;
        RECT  21.516 11.28 21.6 11.304 ;
    END
  END i[526]
  PIN i[527]
    DIRECTION INPUT ;
    USE SIGNAL ;
    PORT
      LAYER M4 ;
        RECT  21.516 11.376 21.6 11.4 ;
    END
  END i[527]
  PIN i[528]
    DIRECTION INPUT ;
    USE SIGNAL ;
    PORT
      LAYER M4 ;
        RECT  21.516 11.472 21.6 11.496 ;
    END
  END i[528]
  PIN i[529]
    DIRECTION INPUT ;
    USE SIGNAL ;
    PORT
      LAYER M4 ;
        RECT  21.516 11.568 21.6 11.592 ;
    END
  END i[529]
  PIN i[52]
    DIRECTION INPUT ;
    USE SIGNAL ;
    PORT
      LAYER M4 ;
        RECT  21.516 24.912 21.6 24.936 ;
    END
  END i[52]
  PIN i[530]
    DIRECTION INPUT ;
    USE SIGNAL ;
    PORT
      LAYER M4 ;
        RECT  21.516 11.664 21.6 11.688 ;
    END
  END i[530]
  PIN i[531]
    DIRECTION INPUT ;
    USE SIGNAL ;
    PORT
      LAYER M4 ;
        RECT  21.516 11.76 21.6 11.784 ;
    END
  END i[531]
  PIN i[532]
    DIRECTION INPUT ;
    USE SIGNAL ;
    PORT
      LAYER M4 ;
        RECT  21.516 11.856 21.6 11.88 ;
    END
  END i[532]
  PIN i[533]
    DIRECTION INPUT ;
    USE SIGNAL ;
    PORT
      LAYER M4 ;
        RECT  21.516 11.952 21.6 11.976 ;
    END
  END i[533]
  PIN i[534]
    DIRECTION INPUT ;
    USE SIGNAL ;
    PORT
      LAYER M4 ;
        RECT  21.516 12.048 21.6 12.072 ;
    END
  END i[534]
  PIN i[535]
    DIRECTION INPUT ;
    USE SIGNAL ;
    PORT
      LAYER M4 ;
        RECT  21.516 12.144 21.6 12.168 ;
    END
  END i[535]
  PIN i[536]
    DIRECTION INPUT ;
    USE SIGNAL ;
    PORT
      LAYER M4 ;
        RECT  21.516 12.24 21.6 12.264 ;
    END
  END i[536]
  PIN i[537]
    DIRECTION INPUT ;
    USE SIGNAL ;
    PORT
      LAYER M4 ;
        RECT  21.516 12.336 21.6 12.36 ;
    END
  END i[537]
  PIN i[538]
    DIRECTION INPUT ;
    USE SIGNAL ;
    PORT
      LAYER M4 ;
        RECT  21.516 12.432 21.6 12.456 ;
    END
  END i[538]
  PIN i[539]
    DIRECTION INPUT ;
    USE SIGNAL ;
    PORT
      LAYER M4 ;
        RECT  21.516 12.528 21.6 12.552 ;
    END
  END i[539]
  PIN i[53]
    DIRECTION INPUT ;
    USE SIGNAL ;
    PORT
      LAYER M4 ;
        RECT  21.516 25.008 21.6 25.032 ;
    END
  END i[53]
  PIN i[540]
    DIRECTION INPUT ;
    USE SIGNAL ;
    PORT
      LAYER M4 ;
        RECT  21.516 12.624 21.6 12.648 ;
    END
  END i[540]
  PIN i[541]
    DIRECTION INPUT ;
    USE SIGNAL ;
    PORT
      LAYER M4 ;
        RECT  21.516 12.72 21.6 12.744 ;
    END
  END i[541]
  PIN i[542]
    DIRECTION INPUT ;
    USE SIGNAL ;
    PORT
      LAYER M4 ;
        RECT  21.516 12.816 21.6 12.84 ;
    END
  END i[542]
  PIN i[543]
    DIRECTION INPUT ;
    USE SIGNAL ;
    PORT
      LAYER M4 ;
        RECT  21.516 12.912 21.6 12.936 ;
    END
  END i[543]
  PIN i[544]
    DIRECTION INPUT ;
    USE SIGNAL ;
    PORT
      LAYER M4 ;
        RECT  21.516 13.008 21.6 13.032 ;
    END
  END i[544]
  PIN i[545]
    DIRECTION INPUT ;
    USE SIGNAL ;
    PORT
      LAYER M4 ;
        RECT  21.516 13.104 21.6 13.128 ;
    END
  END i[545]
  PIN i[546]
    DIRECTION INPUT ;
    USE SIGNAL ;
    PORT
      LAYER M4 ;
        RECT  21.516 13.2 21.6 13.224 ;
    END
  END i[546]
  PIN i[547]
    DIRECTION INPUT ;
    USE SIGNAL ;
    PORT
      LAYER M4 ;
        RECT  21.516 13.296 21.6 13.32 ;
    END
  END i[547]
  PIN i[548]
    DIRECTION INPUT ;
    USE SIGNAL ;
    PORT
      LAYER M4 ;
        RECT  21.516 13.392 21.6 13.416 ;
    END
  END i[548]
  PIN i[549]
    DIRECTION INPUT ;
    USE SIGNAL ;
    PORT
      LAYER M4 ;
        RECT  21.516 13.488 21.6 13.512 ;
    END
  END i[549]
  PIN i[54]
    DIRECTION INPUT ;
    USE SIGNAL ;
    PORT
      LAYER M4 ;
        RECT  21.516 25.104 21.6 25.128 ;
    END
  END i[54]
  PIN i[550]
    DIRECTION INPUT ;
    USE SIGNAL ;
    PORT
      LAYER M4 ;
        RECT  21.516 13.584 21.6 13.608 ;
    END
  END i[550]
  PIN i[551]
    DIRECTION INPUT ;
    USE SIGNAL ;
    PORT
      LAYER M4 ;
        RECT  21.516 13.68 21.6 13.704 ;
    END
  END i[551]
  PIN i[552]
    DIRECTION INPUT ;
    USE SIGNAL ;
    PORT
      LAYER M4 ;
        RECT  21.516 13.776 21.6 13.8 ;
    END
  END i[552]
  PIN i[553]
    DIRECTION INPUT ;
    USE SIGNAL ;
    PORT
      LAYER M4 ;
        RECT  21.516 13.872 21.6 13.896 ;
    END
  END i[553]
  PIN i[554]
    DIRECTION INPUT ;
    USE SIGNAL ;
    PORT
      LAYER M4 ;
        RECT  21.516 13.968 21.6 13.992 ;
    END
  END i[554]
  PIN i[555]
    DIRECTION INPUT ;
    USE SIGNAL ;
    PORT
      LAYER M4 ;
        RECT  21.516 14.064 21.6 14.088 ;
    END
  END i[555]
  PIN i[556]
    DIRECTION INPUT ;
    USE SIGNAL ;
    PORT
      LAYER M4 ;
        RECT  21.516 14.16 21.6 14.184 ;
    END
  END i[556]
  PIN i[557]
    DIRECTION INPUT ;
    USE SIGNAL ;
    PORT
      LAYER M4 ;
        RECT  21.516 14.256 21.6 14.28 ;
    END
  END i[557]
  PIN i[558]
    DIRECTION INPUT ;
    USE SIGNAL ;
    PORT
      LAYER M4 ;
        RECT  21.516 14.352 21.6 14.376 ;
    END
  END i[558]
  PIN i[559]
    DIRECTION INPUT ;
    USE SIGNAL ;
    PORT
      LAYER M4 ;
        RECT  21.516 14.448 21.6 14.472 ;
    END
  END i[559]
  PIN i[55]
    DIRECTION INPUT ;
    USE SIGNAL ;
    PORT
      LAYER M4 ;
        RECT  21.516 25.2 21.6 25.224 ;
    END
  END i[55]
  PIN i[560]
    DIRECTION INPUT ;
    USE SIGNAL ;
    PORT
      LAYER M4 ;
        RECT  21.516 14.544 21.6 14.568 ;
    END
  END i[560]
  PIN i[561]
    DIRECTION INPUT ;
    USE SIGNAL ;
    PORT
      LAYER M4 ;
        RECT  21.516 14.64 21.6 14.664 ;
    END
  END i[561]
  PIN i[562]
    DIRECTION INPUT ;
    USE SIGNAL ;
    PORT
      LAYER M4 ;
        RECT  21.516 14.736 21.6 14.76 ;
    END
  END i[562]
  PIN i[563]
    DIRECTION INPUT ;
    USE SIGNAL ;
    PORT
      LAYER M4 ;
        RECT  21.516 14.832 21.6 14.856 ;
    END
  END i[563]
  PIN i[564]
    DIRECTION INPUT ;
    USE SIGNAL ;
    PORT
      LAYER M4 ;
        RECT  21.516 14.928 21.6 14.952 ;
    END
  END i[564]
  PIN i[565]
    DIRECTION INPUT ;
    USE SIGNAL ;
    PORT
      LAYER M4 ;
        RECT  21.516 15.024 21.6 15.048 ;
    END
  END i[565]
  PIN i[566]
    DIRECTION INPUT ;
    USE SIGNAL ;
    PORT
      LAYER M4 ;
        RECT  21.516 15.12 21.6 15.144 ;
    END
  END i[566]
  PIN i[567]
    DIRECTION INPUT ;
    USE SIGNAL ;
    PORT
      LAYER M4 ;
        RECT  21.516 15.216 21.6 15.24 ;
    END
  END i[567]
  PIN i[568]
    DIRECTION INPUT ;
    USE SIGNAL ;
    PORT
      LAYER M4 ;
        RECT  21.516 15.312 21.6 15.336 ;
    END
  END i[568]
  PIN i[569]
    DIRECTION INPUT ;
    USE SIGNAL ;
    PORT
      LAYER M4 ;
        RECT  21.516 15.408 21.6 15.432 ;
    END
  END i[569]
  PIN i[56]
    DIRECTION INPUT ;
    USE SIGNAL ;
    PORT
      LAYER M4 ;
        RECT  21.516 25.296 21.6 25.32 ;
    END
  END i[56]
  PIN i[570]
    DIRECTION INPUT ;
    USE SIGNAL ;
    PORT
      LAYER M4 ;
        RECT  21.516 15.504 21.6 15.528 ;
    END
  END i[570]
  PIN i[571]
    DIRECTION INPUT ;
    USE SIGNAL ;
    PORT
      LAYER M4 ;
        RECT  21.516 15.6 21.6 15.624 ;
    END
  END i[571]
  PIN i[572]
    DIRECTION INPUT ;
    USE SIGNAL ;
    PORT
      LAYER M4 ;
        RECT  21.516 15.696 21.6 15.72 ;
    END
  END i[572]
  PIN i[573]
    DIRECTION INPUT ;
    USE SIGNAL ;
    PORT
      LAYER M4 ;
        RECT  21.516 15.792 21.6 15.816 ;
    END
  END i[573]
  PIN i[574]
    DIRECTION INPUT ;
    USE SIGNAL ;
    PORT
      LAYER M4 ;
        RECT  21.516 15.888 21.6 15.912 ;
    END
  END i[574]
  PIN i[575]
    DIRECTION INPUT ;
    USE SIGNAL ;
    PORT
      LAYER M4 ;
        RECT  21.516 15.984 21.6 16.008 ;
    END
  END i[575]
  PIN i[576]
    DIRECTION INPUT ;
    USE SIGNAL ;
    PORT
      LAYER M4 ;
        RECT  21.516 0.72 21.6 0.744 ;
    END
  END i[576]
  PIN i[577]
    DIRECTION INPUT ;
    USE SIGNAL ;
    PORT
      LAYER M4 ;
        RECT  21.516 0.816 21.6 0.84 ;
    END
  END i[577]
  PIN i[578]
    DIRECTION INPUT ;
    USE SIGNAL ;
    PORT
      LAYER M4 ;
        RECT  21.516 0.912 21.6 0.936 ;
    END
  END i[578]
  PIN i[579]
    DIRECTION INPUT ;
    USE SIGNAL ;
    PORT
      LAYER M4 ;
        RECT  21.516 1.008 21.6 1.032 ;
    END
  END i[579]
  PIN i[57]
    DIRECTION INPUT ;
    USE SIGNAL ;
    PORT
      LAYER M4 ;
        RECT  21.516 25.392 21.6 25.416 ;
    END
  END i[57]
  PIN i[580]
    DIRECTION INPUT ;
    USE SIGNAL ;
    PORT
      LAYER M4 ;
        RECT  21.516 1.104 21.6 1.128 ;
    END
  END i[580]
  PIN i[581]
    DIRECTION INPUT ;
    USE SIGNAL ;
    PORT
      LAYER M4 ;
        RECT  21.516 1.2 21.6 1.224 ;
    END
  END i[581]
  PIN i[582]
    DIRECTION INPUT ;
    USE SIGNAL ;
    PORT
      LAYER M4 ;
        RECT  21.516 1.296 21.6 1.32 ;
    END
  END i[582]
  PIN i[583]
    DIRECTION INPUT ;
    USE SIGNAL ;
    PORT
      LAYER M4 ;
        RECT  21.516 1.392 21.6 1.416 ;
    END
  END i[583]
  PIN i[584]
    DIRECTION INPUT ;
    USE SIGNAL ;
    PORT
      LAYER M4 ;
        RECT  21.516 1.488 21.6 1.512 ;
    END
  END i[584]
  PIN i[585]
    DIRECTION INPUT ;
    USE SIGNAL ;
    PORT
      LAYER M4 ;
        RECT  21.516 1.584 21.6 1.608 ;
    END
  END i[585]
  PIN i[586]
    DIRECTION INPUT ;
    USE SIGNAL ;
    PORT
      LAYER M4 ;
        RECT  21.516 1.68 21.6 1.704 ;
    END
  END i[586]
  PIN i[587]
    DIRECTION INPUT ;
    USE SIGNAL ;
    PORT
      LAYER M4 ;
        RECT  21.516 1.776 21.6 1.8 ;
    END
  END i[587]
  PIN i[588]
    DIRECTION INPUT ;
    USE SIGNAL ;
    PORT
      LAYER M4 ;
        RECT  21.516 1.872 21.6 1.896 ;
    END
  END i[588]
  PIN i[589]
    DIRECTION INPUT ;
    USE SIGNAL ;
    PORT
      LAYER M4 ;
        RECT  21.516 1.968 21.6 1.992 ;
    END
  END i[589]
  PIN i[58]
    DIRECTION INPUT ;
    USE SIGNAL ;
    PORT
      LAYER M4 ;
        RECT  21.516 25.488 21.6 25.512 ;
    END
  END i[58]
  PIN i[590]
    DIRECTION INPUT ;
    USE SIGNAL ;
    PORT
      LAYER M4 ;
        RECT  21.516 2.064 21.6 2.088 ;
    END
  END i[590]
  PIN i[591]
    DIRECTION INPUT ;
    USE SIGNAL ;
    PORT
      LAYER M4 ;
        RECT  21.516 2.16 21.6 2.184 ;
    END
  END i[591]
  PIN i[592]
    DIRECTION INPUT ;
    USE SIGNAL ;
    PORT
      LAYER M4 ;
        RECT  21.516 2.256 21.6 2.28 ;
    END
  END i[592]
  PIN i[593]
    DIRECTION INPUT ;
    USE SIGNAL ;
    PORT
      LAYER M4 ;
        RECT  21.516 2.352 21.6 2.376 ;
    END
  END i[593]
  PIN i[594]
    DIRECTION INPUT ;
    USE SIGNAL ;
    PORT
      LAYER M4 ;
        RECT  21.516 2.448 21.6 2.472 ;
    END
  END i[594]
  PIN i[595]
    DIRECTION INPUT ;
    USE SIGNAL ;
    PORT
      LAYER M4 ;
        RECT  21.516 2.544 21.6 2.568 ;
    END
  END i[595]
  PIN i[596]
    DIRECTION INPUT ;
    USE SIGNAL ;
    PORT
      LAYER M4 ;
        RECT  21.516 2.64 21.6 2.664 ;
    END
  END i[596]
  PIN i[597]
    DIRECTION INPUT ;
    USE SIGNAL ;
    PORT
      LAYER M4 ;
        RECT  21.516 2.736 21.6 2.76 ;
    END
  END i[597]
  PIN i[598]
    DIRECTION INPUT ;
    USE SIGNAL ;
    PORT
      LAYER M4 ;
        RECT  21.516 2.832 21.6 2.856 ;
    END
  END i[598]
  PIN i[599]
    DIRECTION INPUT ;
    USE SIGNAL ;
    PORT
      LAYER M4 ;
        RECT  21.516 2.928 21.6 2.952 ;
    END
  END i[599]
  PIN i[59]
    DIRECTION INPUT ;
    USE SIGNAL ;
    PORT
      LAYER M4 ;
        RECT  21.516 25.584 21.6 25.608 ;
    END
  END i[59]
  PIN i[5]
    DIRECTION INPUT ;
    USE SIGNAL ;
    PORT
      LAYER M4 ;
        RECT  21.516 20.4 21.6 20.424 ;
    END
  END i[5]
  PIN i[600]
    DIRECTION INPUT ;
    USE SIGNAL ;
    PORT
      LAYER M4 ;
        RECT  21.516 3.024 21.6 3.048 ;
    END
  END i[600]
  PIN i[601]
    DIRECTION INPUT ;
    USE SIGNAL ;
    PORT
      LAYER M4 ;
        RECT  21.516 3.12 21.6 3.144 ;
    END
  END i[601]
  PIN i[602]
    DIRECTION INPUT ;
    USE SIGNAL ;
    PORT
      LAYER M4 ;
        RECT  21.516 3.216 21.6 3.24 ;
    END
  END i[602]
  PIN i[603]
    DIRECTION INPUT ;
    USE SIGNAL ;
    PORT
      LAYER M4 ;
        RECT  21.516 3.312 21.6 3.336 ;
    END
  END i[603]
  PIN i[604]
    DIRECTION INPUT ;
    USE SIGNAL ;
    PORT
      LAYER M4 ;
        RECT  21.516 3.408 21.6 3.432 ;
    END
  END i[604]
  PIN i[605]
    DIRECTION INPUT ;
    USE SIGNAL ;
    PORT
      LAYER M4 ;
        RECT  21.516 3.504 21.6 3.528 ;
    END
  END i[605]
  PIN i[606]
    DIRECTION INPUT ;
    USE SIGNAL ;
    PORT
      LAYER M4 ;
        RECT  21.516 3.6 21.6 3.624 ;
    END
  END i[606]
  PIN i[607]
    DIRECTION INPUT ;
    USE SIGNAL ;
    PORT
      LAYER M4 ;
        RECT  21.516 3.696 21.6 3.72 ;
    END
  END i[607]
  PIN i[608]
    DIRECTION INPUT ;
    USE SIGNAL ;
    PORT
      LAYER M4 ;
        RECT  21.516 61.392 21.6 61.416 ;
    END
  END i[608]
  PIN i[609]
    DIRECTION INPUT ;
    USE SIGNAL ;
    PORT
      LAYER M4 ;
        RECT  21.516 61.488 21.6 61.512 ;
    END
  END i[609]
  PIN i[60]
    DIRECTION INPUT ;
    USE SIGNAL ;
    PORT
      LAYER M4 ;
        RECT  21.516 25.68 21.6 25.704 ;
    END
  END i[60]
  PIN i[610]
    DIRECTION INPUT ;
    USE SIGNAL ;
    PORT
      LAYER M4 ;
        RECT  21.516 61.584 21.6 61.608 ;
    END
  END i[610]
  PIN i[611]
    DIRECTION INPUT ;
    USE SIGNAL ;
    PORT
      LAYER M4 ;
        RECT  21.516 61.68 21.6 61.704 ;
    END
  END i[611]
  PIN i[612]
    DIRECTION INPUT ;
    USE SIGNAL ;
    PORT
      LAYER M4 ;
        RECT  21.516 61.776 21.6 61.8 ;
    END
  END i[612]
  PIN i[613]
    DIRECTION INPUT ;
    USE SIGNAL ;
    PORT
      LAYER M4 ;
        RECT  21.516 61.872 21.6 61.896 ;
    END
  END i[613]
  PIN i[614]
    DIRECTION INPUT ;
    USE SIGNAL ;
    PORT
      LAYER M4 ;
        RECT  21.516 61.968 21.6 61.992 ;
    END
  END i[614]
  PIN i[615]
    DIRECTION INPUT ;
    USE SIGNAL ;
    PORT
      LAYER M4 ;
        RECT  21.516 62.064 21.6 62.088 ;
    END
  END i[615]
  PIN i[616]
    DIRECTION INPUT ;
    USE SIGNAL ;
    PORT
      LAYER M4 ;
        RECT  21.516 62.16 21.6 62.184 ;
    END
  END i[616]
  PIN i[617]
    DIRECTION INPUT ;
    USE SIGNAL ;
    PORT
      LAYER M4 ;
        RECT  21.516 62.256 21.6 62.28 ;
    END
  END i[617]
  PIN i[618]
    DIRECTION INPUT ;
    USE SIGNAL ;
    PORT
      LAYER M4 ;
        RECT  21.516 62.352 21.6 62.376 ;
    END
  END i[618]
  PIN i[619]
    DIRECTION INPUT ;
    USE SIGNAL ;
    PORT
      LAYER M4 ;
        RECT  21.516 62.448 21.6 62.472 ;
    END
  END i[619]
  PIN i[61]
    DIRECTION INPUT ;
    USE SIGNAL ;
    PORT
      LAYER M4 ;
        RECT  21.516 25.776 21.6 25.8 ;
    END
  END i[61]
  PIN i[620]
    DIRECTION INPUT ;
    USE SIGNAL ;
    PORT
      LAYER M4 ;
        RECT  21.516 62.544 21.6 62.568 ;
    END
  END i[620]
  PIN i[621]
    DIRECTION INPUT ;
    USE SIGNAL ;
    PORT
      LAYER M4 ;
        RECT  21.516 62.64 21.6 62.664 ;
    END
  END i[621]
  PIN i[622]
    DIRECTION INPUT ;
    USE SIGNAL ;
    PORT
      LAYER M4 ;
        RECT  21.516 62.736 21.6 62.76 ;
    END
  END i[622]
  PIN i[623]
    DIRECTION INPUT ;
    USE SIGNAL ;
    PORT
      LAYER M4 ;
        RECT  21.516 62.832 21.6 62.856 ;
    END
  END i[623]
  PIN i[62]
    DIRECTION INPUT ;
    USE SIGNAL ;
    PORT
      LAYER M4 ;
        RECT  21.516 25.872 21.6 25.896 ;
    END
  END i[62]
  PIN i[63]
    DIRECTION INPUT ;
    USE SIGNAL ;
    PORT
      LAYER M4 ;
        RECT  21.516 25.968 21.6 25.992 ;
    END
  END i[63]
  PIN i[64]
    DIRECTION INPUT ;
    USE SIGNAL ;
    PORT
      LAYER M4 ;
        RECT  21.516 32.208 21.6 32.232 ;
    END
  END i[64]
  PIN i[65]
    DIRECTION INPUT ;
    USE SIGNAL ;
    PORT
      LAYER M4 ;
        RECT  21.516 32.304 21.6 32.328 ;
    END
  END i[65]
  PIN i[66]
    DIRECTION INPUT ;
    USE SIGNAL ;
    PORT
      LAYER M4 ;
        RECT  21.516 32.4 21.6 32.424 ;
    END
  END i[66]
  PIN i[67]
    DIRECTION INPUT ;
    USE SIGNAL ;
    PORT
      LAYER M4 ;
        RECT  21.516 32.496 21.6 32.52 ;
    END
  END i[67]
  PIN i[68]
    DIRECTION INPUT ;
    USE SIGNAL ;
    PORT
      LAYER M4 ;
        RECT  21.516 32.592 21.6 32.616 ;
    END
  END i[68]
  PIN i[69]
    DIRECTION INPUT ;
    USE SIGNAL ;
    PORT
      LAYER M4 ;
        RECT  21.516 32.688 21.6 32.712 ;
    END
  END i[69]
  PIN i[6]
    DIRECTION INPUT ;
    USE SIGNAL ;
    PORT
      LAYER M4 ;
        RECT  21.516 20.496 21.6 20.52 ;
    END
  END i[6]
  PIN i[70]
    DIRECTION INPUT ;
    USE SIGNAL ;
    PORT
      LAYER M4 ;
        RECT  21.516 32.784 21.6 32.808 ;
    END
  END i[70]
  PIN i[71]
    DIRECTION INPUT ;
    USE SIGNAL ;
    PORT
      LAYER M4 ;
        RECT  21.516 32.88 21.6 32.904 ;
    END
  END i[71]
  PIN i[72]
    DIRECTION INPUT ;
    USE SIGNAL ;
    PORT
      LAYER M4 ;
        RECT  21.516 32.976 21.6 33 ;
    END
  END i[72]
  PIN i[73]
    DIRECTION INPUT ;
    USE SIGNAL ;
    PORT
      LAYER M4 ;
        RECT  21.516 33.072 21.6 33.096 ;
    END
  END i[73]
  PIN i[74]
    DIRECTION INPUT ;
    USE SIGNAL ;
    PORT
      LAYER M4 ;
        RECT  21.516 33.168 21.6 33.192 ;
    END
  END i[74]
  PIN i[75]
    DIRECTION INPUT ;
    USE SIGNAL ;
    PORT
      LAYER M4 ;
        RECT  21.516 33.264 21.6 33.288 ;
    END
  END i[75]
  PIN i[76]
    DIRECTION INPUT ;
    USE SIGNAL ;
    PORT
      LAYER M4 ;
        RECT  21.516 33.36 21.6 33.384 ;
    END
  END i[76]
  PIN i[77]
    DIRECTION INPUT ;
    USE SIGNAL ;
    PORT
      LAYER M4 ;
        RECT  21.516 33.456 21.6 33.48 ;
    END
  END i[77]
  PIN i[78]
    DIRECTION INPUT ;
    USE SIGNAL ;
    PORT
      LAYER M4 ;
        RECT  21.516 33.552 21.6 33.576 ;
    END
  END i[78]
  PIN i[79]
    DIRECTION INPUT ;
    USE SIGNAL ;
    PORT
      LAYER M4 ;
        RECT  21.516 33.648 21.6 33.672 ;
    END
  END i[79]
  PIN i[7]
    DIRECTION INPUT ;
    USE SIGNAL ;
    PORT
      LAYER M4 ;
        RECT  21.516 20.592 21.6 20.616 ;
    END
  END i[7]
  PIN i[80]
    DIRECTION INPUT ;
    USE SIGNAL ;
    PORT
      LAYER M4 ;
        RECT  21.516 33.744 21.6 33.768 ;
    END
  END i[80]
  PIN i[81]
    DIRECTION INPUT ;
    USE SIGNAL ;
    PORT
      LAYER M4 ;
        RECT  21.516 33.84 21.6 33.864 ;
    END
  END i[81]
  PIN i[82]
    DIRECTION INPUT ;
    USE SIGNAL ;
    PORT
      LAYER M4 ;
        RECT  21.516 33.936 21.6 33.96 ;
    END
  END i[82]
  PIN i[83]
    DIRECTION INPUT ;
    USE SIGNAL ;
    PORT
      LAYER M4 ;
        RECT  21.516 34.032 21.6 34.056 ;
    END
  END i[83]
  PIN i[84]
    DIRECTION INPUT ;
    USE SIGNAL ;
    PORT
      LAYER M4 ;
        RECT  21.516 34.128 21.6 34.152 ;
    END
  END i[84]
  PIN i[85]
    DIRECTION INPUT ;
    USE SIGNAL ;
    PORT
      LAYER M4 ;
        RECT  21.516 34.224 21.6 34.248 ;
    END
  END i[85]
  PIN i[86]
    DIRECTION INPUT ;
    USE SIGNAL ;
    PORT
      LAYER M4 ;
        RECT  21.516 34.32 21.6 34.344 ;
    END
  END i[86]
  PIN i[87]
    DIRECTION INPUT ;
    USE SIGNAL ;
    PORT
      LAYER M4 ;
        RECT  21.516 34.416 21.6 34.44 ;
    END
  END i[87]
  PIN i[88]
    DIRECTION INPUT ;
    USE SIGNAL ;
    PORT
      LAYER M4 ;
        RECT  21.516 34.512 21.6 34.536 ;
    END
  END i[88]
  PIN i[89]
    DIRECTION INPUT ;
    USE SIGNAL ;
    PORT
      LAYER M4 ;
        RECT  21.516 34.608 21.6 34.632 ;
    END
  END i[89]
  PIN i[8]
    DIRECTION INPUT ;
    USE SIGNAL ;
    PORT
      LAYER M4 ;
        RECT  21.516 20.688 21.6 20.712 ;
    END
  END i[8]
  PIN i[90]
    DIRECTION INPUT ;
    USE SIGNAL ;
    PORT
      LAYER M4 ;
        RECT  21.516 34.704 21.6 34.728 ;
    END
  END i[90]
  PIN i[91]
    DIRECTION INPUT ;
    USE SIGNAL ;
    PORT
      LAYER M4 ;
        RECT  21.516 34.8 21.6 34.824 ;
    END
  END i[91]
  PIN i[92]
    DIRECTION INPUT ;
    USE SIGNAL ;
    PORT
      LAYER M4 ;
        RECT  21.516 34.896 21.6 34.92 ;
    END
  END i[92]
  PIN i[93]
    DIRECTION INPUT ;
    USE SIGNAL ;
    PORT
      LAYER M4 ;
        RECT  21.516 34.992 21.6 35.016 ;
    END
  END i[93]
  PIN i[94]
    DIRECTION INPUT ;
    USE SIGNAL ;
    PORT
      LAYER M4 ;
        RECT  21.516 35.088 21.6 35.112 ;
    END
  END i[94]
  PIN i[95]
    DIRECTION INPUT ;
    USE SIGNAL ;
    PORT
      LAYER M4 ;
        RECT  21.516 35.184 21.6 35.208 ;
    END
  END i[95]
  PIN i[96]
    DIRECTION INPUT ;
    USE SIGNAL ;
    PORT
      LAYER M4 ;
        RECT  21.516 29.136 21.6 29.16 ;
    END
  END i[96]
  PIN i[97]
    DIRECTION INPUT ;
    USE SIGNAL ;
    PORT
      LAYER M4 ;
        RECT  21.516 29.232 21.6 29.256 ;
    END
  END i[97]
  PIN i[98]
    DIRECTION INPUT ;
    USE SIGNAL ;
    PORT
      LAYER M4 ;
        RECT  21.516 29.328 21.6 29.352 ;
    END
  END i[98]
  PIN i[99]
    DIRECTION INPUT ;
    USE SIGNAL ;
    PORT
      LAYER M4 ;
        RECT  21.516 29.424 21.6 29.448 ;
    END
  END i[99]
  PIN i[9]
    DIRECTION INPUT ;
    USE SIGNAL ;
    PORT
      LAYER M4 ;
        RECT  21.516 20.784 21.6 20.808 ;
    END
  END i[9]
  PIN o[0]
    DIRECTION OUTPUT ;
    USE SIGNAL ;
    PORT
      LAYER M4 ;
        RECT  0 41.808 0.084 41.832 ;
    END
  END o[0]
  PIN o[100]
    DIRECTION OUTPUT ;
    USE SIGNAL ;
    PORT
      LAYER M4 ;
        RECT  0 39.12 0.084 39.144 ;
    END
  END o[100]
  PIN o[101]
    DIRECTION OUTPUT ;
    USE SIGNAL ;
    PORT
      LAYER M4 ;
        RECT  0 39.216 0.084 39.24 ;
    END
  END o[101]
  PIN o[102]
    DIRECTION OUTPUT ;
    USE SIGNAL ;
    PORT
      LAYER M4 ;
        RECT  0 39.312 0.084 39.336 ;
    END
  END o[102]
  PIN o[103]
    DIRECTION OUTPUT ;
    USE SIGNAL ;
    PORT
      LAYER M4 ;
        RECT  0 39.408 0.084 39.432 ;
    END
  END o[103]
  PIN o[104]
    DIRECTION OUTPUT ;
    USE SIGNAL ;
    PORT
      LAYER M4 ;
        RECT  0 39.504 0.084 39.528 ;
    END
  END o[104]
  PIN o[105]
    DIRECTION OUTPUT ;
    USE SIGNAL ;
    PORT
      LAYER M4 ;
        RECT  0 39.6 0.084 39.624 ;
    END
  END o[105]
  PIN o[106]
    DIRECTION OUTPUT ;
    USE SIGNAL ;
    PORT
      LAYER M4 ;
        RECT  0 39.696 0.084 39.72 ;
    END
  END o[106]
  PIN o[107]
    DIRECTION OUTPUT ;
    USE SIGNAL ;
    PORT
      LAYER M4 ;
        RECT  0 39.792 0.084 39.816 ;
    END
  END o[107]
  PIN o[108]
    DIRECTION OUTPUT ;
    USE SIGNAL ;
    PORT
      LAYER M4 ;
        RECT  0 39.888 0.084 39.912 ;
    END
  END o[108]
  PIN o[109]
    DIRECTION OUTPUT ;
    USE SIGNAL ;
    PORT
      LAYER M4 ;
        RECT  0 39.984 0.084 40.008 ;
    END
  END o[109]
  PIN o[10]
    DIRECTION OUTPUT ;
    USE SIGNAL ;
    PORT
      LAYER M4 ;
        RECT  0 42.768 0.084 42.792 ;
    END
  END o[10]
  PIN o[110]
    DIRECTION OUTPUT ;
    USE SIGNAL ;
    PORT
      LAYER M4 ;
        RECT  0 40.08 0.084 40.104 ;
    END
  END o[110]
  PIN o[111]
    DIRECTION OUTPUT ;
    USE SIGNAL ;
    PORT
      LAYER M4 ;
        RECT  0 40.176 0.084 40.2 ;
    END
  END o[111]
  PIN o[112]
    DIRECTION OUTPUT ;
    USE SIGNAL ;
    PORT
      LAYER M4 ;
        RECT  0 40.272 0.084 40.296 ;
    END
  END o[112]
  PIN o[113]
    DIRECTION OUTPUT ;
    USE SIGNAL ;
    PORT
      LAYER M4 ;
        RECT  0 40.368 0.084 40.392 ;
    END
  END o[113]
  PIN o[114]
    DIRECTION OUTPUT ;
    USE SIGNAL ;
    PORT
      LAYER M4 ;
        RECT  0 40.464 0.084 40.488 ;
    END
  END o[114]
  PIN o[115]
    DIRECTION OUTPUT ;
    USE SIGNAL ;
    PORT
      LAYER M4 ;
        RECT  0 40.56 0.084 40.584 ;
    END
  END o[115]
  PIN o[116]
    DIRECTION OUTPUT ;
    USE SIGNAL ;
    PORT
      LAYER M4 ;
        RECT  0 40.656 0.084 40.68 ;
    END
  END o[116]
  PIN o[117]
    DIRECTION OUTPUT ;
    USE SIGNAL ;
    PORT
      LAYER M4 ;
        RECT  0 40.752 0.084 40.776 ;
    END
  END o[117]
  PIN o[118]
    DIRECTION OUTPUT ;
    USE SIGNAL ;
    PORT
      LAYER M4 ;
        RECT  0 40.848 0.084 40.872 ;
    END
  END o[118]
  PIN o[119]
    DIRECTION OUTPUT ;
    USE SIGNAL ;
    PORT
      LAYER M4 ;
        RECT  0 40.944 0.084 40.968 ;
    END
  END o[119]
  PIN o[11]
    DIRECTION OUTPUT ;
    USE SIGNAL ;
    PORT
      LAYER M4 ;
        RECT  0 42.864 0.084 42.888 ;
    END
  END o[11]
  PIN o[120]
    DIRECTION OUTPUT ;
    USE SIGNAL ;
    PORT
      LAYER M4 ;
        RECT  0 41.04 0.084 41.064 ;
    END
  END o[120]
  PIN o[121]
    DIRECTION OUTPUT ;
    USE SIGNAL ;
    PORT
      LAYER M4 ;
        RECT  0 41.136 0.084 41.16 ;
    END
  END o[121]
  PIN o[122]
    DIRECTION OUTPUT ;
    USE SIGNAL ;
    PORT
      LAYER M4 ;
        RECT  0 41.232 0.084 41.256 ;
    END
  END o[122]
  PIN o[123]
    DIRECTION OUTPUT ;
    USE SIGNAL ;
    PORT
      LAYER M4 ;
        RECT  0 41.328 0.084 41.352 ;
    END
  END o[123]
  PIN o[124]
    DIRECTION OUTPUT ;
    USE SIGNAL ;
    PORT
      LAYER M4 ;
        RECT  0 41.424 0.084 41.448 ;
    END
  END o[124]
  PIN o[125]
    DIRECTION OUTPUT ;
    USE SIGNAL ;
    PORT
      LAYER M4 ;
        RECT  0 41.52 0.084 41.544 ;
    END
  END o[125]
  PIN o[126]
    DIRECTION OUTPUT ;
    USE SIGNAL ;
    PORT
      LAYER M4 ;
        RECT  0 41.616 0.084 41.64 ;
    END
  END o[126]
  PIN o[127]
    DIRECTION OUTPUT ;
    USE SIGNAL ;
    PORT
      LAYER M4 ;
        RECT  0 41.712 0.084 41.736 ;
    END
  END o[127]
  PIN o[128]
    DIRECTION OUTPUT ;
    USE SIGNAL ;
    PORT
      LAYER M4 ;
        RECT  0 26.448 0.084 26.472 ;
    END
  END o[128]
  PIN o[129]
    DIRECTION OUTPUT ;
    USE SIGNAL ;
    PORT
      LAYER M4 ;
        RECT  0 26.544 0.084 26.568 ;
    END
  END o[129]
  PIN o[12]
    DIRECTION OUTPUT ;
    USE SIGNAL ;
    PORT
      LAYER M4 ;
        RECT  0 42.96 0.084 42.984 ;
    END
  END o[12]
  PIN o[130]
    DIRECTION OUTPUT ;
    USE SIGNAL ;
    PORT
      LAYER M4 ;
        RECT  0 26.64 0.084 26.664 ;
    END
  END o[130]
  PIN o[131]
    DIRECTION OUTPUT ;
    USE SIGNAL ;
    PORT
      LAYER M4 ;
        RECT  0 26.736 0.084 26.76 ;
    END
  END o[131]
  PIN o[132]
    DIRECTION OUTPUT ;
    USE SIGNAL ;
    PORT
      LAYER M4 ;
        RECT  0 26.832 0.084 26.856 ;
    END
  END o[132]
  PIN o[133]
    DIRECTION OUTPUT ;
    USE SIGNAL ;
    PORT
      LAYER M4 ;
        RECT  0 26.928 0.084 26.952 ;
    END
  END o[133]
  PIN o[134]
    DIRECTION OUTPUT ;
    USE SIGNAL ;
    PORT
      LAYER M4 ;
        RECT  0 27.024 0.084 27.048 ;
    END
  END o[134]
  PIN o[135]
    DIRECTION OUTPUT ;
    USE SIGNAL ;
    PORT
      LAYER M4 ;
        RECT  0 27.12 0.084 27.144 ;
    END
  END o[135]
  PIN o[136]
    DIRECTION OUTPUT ;
    USE SIGNAL ;
    PORT
      LAYER M4 ;
        RECT  0 27.216 0.084 27.24 ;
    END
  END o[136]
  PIN o[137]
    DIRECTION OUTPUT ;
    USE SIGNAL ;
    PORT
      LAYER M4 ;
        RECT  0 27.312 0.084 27.336 ;
    END
  END o[137]
  PIN o[138]
    DIRECTION OUTPUT ;
    USE SIGNAL ;
    PORT
      LAYER M4 ;
        RECT  0 27.408 0.084 27.432 ;
    END
  END o[138]
  PIN o[139]
    DIRECTION OUTPUT ;
    USE SIGNAL ;
    PORT
      LAYER M4 ;
        RECT  0 27.504 0.084 27.528 ;
    END
  END o[139]
  PIN o[13]
    DIRECTION OUTPUT ;
    USE SIGNAL ;
    PORT
      LAYER M4 ;
        RECT  0 43.056 0.084 43.08 ;
    END
  END o[13]
  PIN o[140]
    DIRECTION OUTPUT ;
    USE SIGNAL ;
    PORT
      LAYER M4 ;
        RECT  0 27.6 0.084 27.624 ;
    END
  END o[140]
  PIN o[141]
    DIRECTION OUTPUT ;
    USE SIGNAL ;
    PORT
      LAYER M4 ;
        RECT  0 27.696 0.084 27.72 ;
    END
  END o[141]
  PIN o[142]
    DIRECTION OUTPUT ;
    USE SIGNAL ;
    PORT
      LAYER M4 ;
        RECT  0 27.792 0.084 27.816 ;
    END
  END o[142]
  PIN o[143]
    DIRECTION OUTPUT ;
    USE SIGNAL ;
    PORT
      LAYER M4 ;
        RECT  0 27.888 0.084 27.912 ;
    END
  END o[143]
  PIN o[144]
    DIRECTION OUTPUT ;
    USE SIGNAL ;
    PORT
      LAYER M4 ;
        RECT  0 27.984 0.084 28.008 ;
    END
  END o[144]
  PIN o[145]
    DIRECTION OUTPUT ;
    USE SIGNAL ;
    PORT
      LAYER M4 ;
        RECT  0 28.08 0.084 28.104 ;
    END
  END o[145]
  PIN o[146]
    DIRECTION OUTPUT ;
    USE SIGNAL ;
    PORT
      LAYER M4 ;
        RECT  0 28.176 0.084 28.2 ;
    END
  END o[146]
  PIN o[147]
    DIRECTION OUTPUT ;
    USE SIGNAL ;
    PORT
      LAYER M4 ;
        RECT  0 28.272 0.084 28.296 ;
    END
  END o[147]
  PIN o[148]
    DIRECTION OUTPUT ;
    USE SIGNAL ;
    PORT
      LAYER M4 ;
        RECT  0 28.368 0.084 28.392 ;
    END
  END o[148]
  PIN o[149]
    DIRECTION OUTPUT ;
    USE SIGNAL ;
    PORT
      LAYER M4 ;
        RECT  0 28.464 0.084 28.488 ;
    END
  END o[149]
  PIN o[14]
    DIRECTION OUTPUT ;
    USE SIGNAL ;
    PORT
      LAYER M4 ;
        RECT  0 43.152 0.084 43.176 ;
    END
  END o[14]
  PIN o[150]
    DIRECTION OUTPUT ;
    USE SIGNAL ;
    PORT
      LAYER M4 ;
        RECT  0 28.56 0.084 28.584 ;
    END
  END o[150]
  PIN o[151]
    DIRECTION OUTPUT ;
    USE SIGNAL ;
    PORT
      LAYER M4 ;
        RECT  0 28.656 0.084 28.68 ;
    END
  END o[151]
  PIN o[152]
    DIRECTION OUTPUT ;
    USE SIGNAL ;
    PORT
      LAYER M4 ;
        RECT  0 28.752 0.084 28.776 ;
    END
  END o[152]
  PIN o[153]
    DIRECTION OUTPUT ;
    USE SIGNAL ;
    PORT
      LAYER M4 ;
        RECT  0 28.848 0.084 28.872 ;
    END
  END o[153]
  PIN o[154]
    DIRECTION OUTPUT ;
    USE SIGNAL ;
    PORT
      LAYER M4 ;
        RECT  0 28.944 0.084 28.968 ;
    END
  END o[154]
  PIN o[155]
    DIRECTION OUTPUT ;
    USE SIGNAL ;
    PORT
      LAYER M4 ;
        RECT  0 29.04 0.084 29.064 ;
    END
  END o[155]
  PIN o[156]
    DIRECTION OUTPUT ;
    USE SIGNAL ;
    PORT
      LAYER M4 ;
        RECT  0 29.136 0.084 29.16 ;
    END
  END o[156]
  PIN o[157]
    DIRECTION OUTPUT ;
    USE SIGNAL ;
    PORT
      LAYER M4 ;
        RECT  0 29.232 0.084 29.256 ;
    END
  END o[157]
  PIN o[158]
    DIRECTION OUTPUT ;
    USE SIGNAL ;
    PORT
      LAYER M4 ;
        RECT  0 29.328 0.084 29.352 ;
    END
  END o[158]
  PIN o[159]
    DIRECTION OUTPUT ;
    USE SIGNAL ;
    PORT
      LAYER M4 ;
        RECT  0 29.424 0.084 29.448 ;
    END
  END o[159]
  PIN o[15]
    DIRECTION OUTPUT ;
    USE SIGNAL ;
    PORT
      LAYER M4 ;
        RECT  0 43.248 0.084 43.272 ;
    END
  END o[15]
  PIN o[160]
    DIRECTION OUTPUT ;
    USE SIGNAL ;
    PORT
      LAYER M4 ;
        RECT  0 35.664 0.084 35.688 ;
    END
  END o[160]
  PIN o[161]
    DIRECTION OUTPUT ;
    USE SIGNAL ;
    PORT
      LAYER M4 ;
        RECT  0 35.76 0.084 35.784 ;
    END
  END o[161]
  PIN o[162]
    DIRECTION OUTPUT ;
    USE SIGNAL ;
    PORT
      LAYER M4 ;
        RECT  0 35.856 0.084 35.88 ;
    END
  END o[162]
  PIN o[163]
    DIRECTION OUTPUT ;
    USE SIGNAL ;
    PORT
      LAYER M4 ;
        RECT  0 35.952 0.084 35.976 ;
    END
  END o[163]
  PIN o[164]
    DIRECTION OUTPUT ;
    USE SIGNAL ;
    PORT
      LAYER M4 ;
        RECT  0 36.048 0.084 36.072 ;
    END
  END o[164]
  PIN o[165]
    DIRECTION OUTPUT ;
    USE SIGNAL ;
    PORT
      LAYER M4 ;
        RECT  0 36.144 0.084 36.168 ;
    END
  END o[165]
  PIN o[166]
    DIRECTION OUTPUT ;
    USE SIGNAL ;
    PORT
      LAYER M4 ;
        RECT  0 36.24 0.084 36.264 ;
    END
  END o[166]
  PIN o[167]
    DIRECTION OUTPUT ;
    USE SIGNAL ;
    PORT
      LAYER M4 ;
        RECT  0 36.336 0.084 36.36 ;
    END
  END o[167]
  PIN o[168]
    DIRECTION OUTPUT ;
    USE SIGNAL ;
    PORT
      LAYER M4 ;
        RECT  0 36.432 0.084 36.456 ;
    END
  END o[168]
  PIN o[169]
    DIRECTION OUTPUT ;
    USE SIGNAL ;
    PORT
      LAYER M4 ;
        RECT  0 36.528 0.084 36.552 ;
    END
  END o[169]
  PIN o[16]
    DIRECTION OUTPUT ;
    USE SIGNAL ;
    PORT
      LAYER M4 ;
        RECT  0 43.344 0.084 43.368 ;
    END
  END o[16]
  PIN o[170]
    DIRECTION OUTPUT ;
    USE SIGNAL ;
    PORT
      LAYER M4 ;
        RECT  0 36.624 0.084 36.648 ;
    END
  END o[170]
  PIN o[171]
    DIRECTION OUTPUT ;
    USE SIGNAL ;
    PORT
      LAYER M4 ;
        RECT  0 36.72 0.084 36.744 ;
    END
  END o[171]
  PIN o[172]
    DIRECTION OUTPUT ;
    USE SIGNAL ;
    PORT
      LAYER M4 ;
        RECT  0 36.816 0.084 36.84 ;
    END
  END o[172]
  PIN o[173]
    DIRECTION OUTPUT ;
    USE SIGNAL ;
    PORT
      LAYER M4 ;
        RECT  0 36.912 0.084 36.936 ;
    END
  END o[173]
  PIN o[174]
    DIRECTION OUTPUT ;
    USE SIGNAL ;
    PORT
      LAYER M4 ;
        RECT  0 37.008 0.084 37.032 ;
    END
  END o[174]
  PIN o[175]
    DIRECTION OUTPUT ;
    USE SIGNAL ;
    PORT
      LAYER M4 ;
        RECT  0 37.104 0.084 37.128 ;
    END
  END o[175]
  PIN o[176]
    DIRECTION OUTPUT ;
    USE SIGNAL ;
    PORT
      LAYER M4 ;
        RECT  0 37.2 0.084 37.224 ;
    END
  END o[176]
  PIN o[177]
    DIRECTION OUTPUT ;
    USE SIGNAL ;
    PORT
      LAYER M4 ;
        RECT  0 37.296 0.084 37.32 ;
    END
  END o[177]
  PIN o[178]
    DIRECTION OUTPUT ;
    USE SIGNAL ;
    PORT
      LAYER M4 ;
        RECT  0 37.392 0.084 37.416 ;
    END
  END o[178]
  PIN o[179]
    DIRECTION OUTPUT ;
    USE SIGNAL ;
    PORT
      LAYER M4 ;
        RECT  0 37.488 0.084 37.512 ;
    END
  END o[179]
  PIN o[17]
    DIRECTION OUTPUT ;
    USE SIGNAL ;
    PORT
      LAYER M4 ;
        RECT  0 43.44 0.084 43.464 ;
    END
  END o[17]
  PIN o[180]
    DIRECTION OUTPUT ;
    USE SIGNAL ;
    PORT
      LAYER M4 ;
        RECT  0 37.584 0.084 37.608 ;
    END
  END o[180]
  PIN o[181]
    DIRECTION OUTPUT ;
    USE SIGNAL ;
    PORT
      LAYER M4 ;
        RECT  0 37.68 0.084 37.704 ;
    END
  END o[181]
  PIN o[182]
    DIRECTION OUTPUT ;
    USE SIGNAL ;
    PORT
      LAYER M4 ;
        RECT  0 37.776 0.084 37.8 ;
    END
  END o[182]
  PIN o[183]
    DIRECTION OUTPUT ;
    USE SIGNAL ;
    PORT
      LAYER M4 ;
        RECT  0 37.872 0.084 37.896 ;
    END
  END o[183]
  PIN o[184]
    DIRECTION OUTPUT ;
    USE SIGNAL ;
    PORT
      LAYER M4 ;
        RECT  0 37.968 0.084 37.992 ;
    END
  END o[184]
  PIN o[185]
    DIRECTION OUTPUT ;
    USE SIGNAL ;
    PORT
      LAYER M4 ;
        RECT  0 38.064 0.084 38.088 ;
    END
  END o[185]
  PIN o[186]
    DIRECTION OUTPUT ;
    USE SIGNAL ;
    PORT
      LAYER M4 ;
        RECT  0 38.16 0.084 38.184 ;
    END
  END o[186]
  PIN o[187]
    DIRECTION OUTPUT ;
    USE SIGNAL ;
    PORT
      LAYER M4 ;
        RECT  0 38.256 0.084 38.28 ;
    END
  END o[187]
  PIN o[188]
    DIRECTION OUTPUT ;
    USE SIGNAL ;
    PORT
      LAYER M4 ;
        RECT  0 38.352 0.084 38.376 ;
    END
  END o[188]
  PIN o[189]
    DIRECTION OUTPUT ;
    USE SIGNAL ;
    PORT
      LAYER M4 ;
        RECT  0 38.448 0.084 38.472 ;
    END
  END o[189]
  PIN o[18]
    DIRECTION OUTPUT ;
    USE SIGNAL ;
    PORT
      LAYER M4 ;
        RECT  0 43.536 0.084 43.56 ;
    END
  END o[18]
  PIN o[190]
    DIRECTION OUTPUT ;
    USE SIGNAL ;
    PORT
      LAYER M4 ;
        RECT  0 38.544 0.084 38.568 ;
    END
  END o[190]
  PIN o[191]
    DIRECTION OUTPUT ;
    USE SIGNAL ;
    PORT
      LAYER M4 ;
        RECT  0 38.64 0.084 38.664 ;
    END
  END o[191]
  PIN o[192]
    DIRECTION OUTPUT ;
    USE SIGNAL ;
    PORT
      LAYER M4 ;
        RECT  0 13.392 0.084 13.416 ;
    END
  END o[192]
  PIN o[193]
    DIRECTION OUTPUT ;
    USE SIGNAL ;
    PORT
      LAYER M4 ;
        RECT  0 13.488 0.084 13.512 ;
    END
  END o[193]
  PIN o[194]
    DIRECTION OUTPUT ;
    USE SIGNAL ;
    PORT
      LAYER M4 ;
        RECT  0 13.584 0.084 13.608 ;
    END
  END o[194]
  PIN o[195]
    DIRECTION OUTPUT ;
    USE SIGNAL ;
    PORT
      LAYER M4 ;
        RECT  0 13.68 0.084 13.704 ;
    END
  END o[195]
  PIN o[196]
    DIRECTION OUTPUT ;
    USE SIGNAL ;
    PORT
      LAYER M4 ;
        RECT  0 13.776 0.084 13.8 ;
    END
  END o[196]
  PIN o[197]
    DIRECTION OUTPUT ;
    USE SIGNAL ;
    PORT
      LAYER M4 ;
        RECT  0 13.872 0.084 13.896 ;
    END
  END o[197]
  PIN o[198]
    DIRECTION OUTPUT ;
    USE SIGNAL ;
    PORT
      LAYER M4 ;
        RECT  0 13.968 0.084 13.992 ;
    END
  END o[198]
  PIN o[199]
    DIRECTION OUTPUT ;
    USE SIGNAL ;
    PORT
      LAYER M4 ;
        RECT  0 14.064 0.084 14.088 ;
    END
  END o[199]
  PIN o[19]
    DIRECTION OUTPUT ;
    USE SIGNAL ;
    PORT
      LAYER M4 ;
        RECT  0 43.632 0.084 43.656 ;
    END
  END o[19]
  PIN o[1]
    DIRECTION OUTPUT ;
    USE SIGNAL ;
    PORT
      LAYER M4 ;
        RECT  0 41.904 0.084 41.928 ;
    END
  END o[1]
  PIN o[200]
    DIRECTION OUTPUT ;
    USE SIGNAL ;
    PORT
      LAYER M4 ;
        RECT  0 14.16 0.084 14.184 ;
    END
  END o[200]
  PIN o[201]
    DIRECTION OUTPUT ;
    USE SIGNAL ;
    PORT
      LAYER M4 ;
        RECT  0 14.256 0.084 14.28 ;
    END
  END o[201]
  PIN o[202]
    DIRECTION OUTPUT ;
    USE SIGNAL ;
    PORT
      LAYER M4 ;
        RECT  0 14.352 0.084 14.376 ;
    END
  END o[202]
  PIN o[203]
    DIRECTION OUTPUT ;
    USE SIGNAL ;
    PORT
      LAYER M4 ;
        RECT  0 14.448 0.084 14.472 ;
    END
  END o[203]
  PIN o[204]
    DIRECTION OUTPUT ;
    USE SIGNAL ;
    PORT
      LAYER M4 ;
        RECT  0 14.544 0.084 14.568 ;
    END
  END o[204]
  PIN o[205]
    DIRECTION OUTPUT ;
    USE SIGNAL ;
    PORT
      LAYER M4 ;
        RECT  0 14.64 0.084 14.664 ;
    END
  END o[205]
  PIN o[206]
    DIRECTION OUTPUT ;
    USE SIGNAL ;
    PORT
      LAYER M4 ;
        RECT  0 14.736 0.084 14.76 ;
    END
  END o[206]
  PIN o[207]
    DIRECTION OUTPUT ;
    USE SIGNAL ;
    PORT
      LAYER M4 ;
        RECT  0 14.832 0.084 14.856 ;
    END
  END o[207]
  PIN o[208]
    DIRECTION OUTPUT ;
    USE SIGNAL ;
    PORT
      LAYER M4 ;
        RECT  0 14.928 0.084 14.952 ;
    END
  END o[208]
  PIN o[209]
    DIRECTION OUTPUT ;
    USE SIGNAL ;
    PORT
      LAYER M4 ;
        RECT  0 15.024 0.084 15.048 ;
    END
  END o[209]
  PIN o[20]
    DIRECTION OUTPUT ;
    USE SIGNAL ;
    PORT
      LAYER M4 ;
        RECT  0 43.728 0.084 43.752 ;
    END
  END o[20]
  PIN o[210]
    DIRECTION OUTPUT ;
    USE SIGNAL ;
    PORT
      LAYER M4 ;
        RECT  0 15.12 0.084 15.144 ;
    END
  END o[210]
  PIN o[211]
    DIRECTION OUTPUT ;
    USE SIGNAL ;
    PORT
      LAYER M4 ;
        RECT  0 15.216 0.084 15.24 ;
    END
  END o[211]
  PIN o[212]
    DIRECTION OUTPUT ;
    USE SIGNAL ;
    PORT
      LAYER M4 ;
        RECT  0 15.312 0.084 15.336 ;
    END
  END o[212]
  PIN o[213]
    DIRECTION OUTPUT ;
    USE SIGNAL ;
    PORT
      LAYER M4 ;
        RECT  0 15.408 0.084 15.432 ;
    END
  END o[213]
  PIN o[214]
    DIRECTION OUTPUT ;
    USE SIGNAL ;
    PORT
      LAYER M4 ;
        RECT  0 15.504 0.084 15.528 ;
    END
  END o[214]
  PIN o[215]
    DIRECTION OUTPUT ;
    USE SIGNAL ;
    PORT
      LAYER M4 ;
        RECT  0 15.6 0.084 15.624 ;
    END
  END o[215]
  PIN o[216]
    DIRECTION OUTPUT ;
    USE SIGNAL ;
    PORT
      LAYER M4 ;
        RECT  0 15.696 0.084 15.72 ;
    END
  END o[216]
  PIN o[217]
    DIRECTION OUTPUT ;
    USE SIGNAL ;
    PORT
      LAYER M4 ;
        RECT  0 15.792 0.084 15.816 ;
    END
  END o[217]
  PIN o[218]
    DIRECTION OUTPUT ;
    USE SIGNAL ;
    PORT
      LAYER M4 ;
        RECT  0 15.888 0.084 15.912 ;
    END
  END o[218]
  PIN o[219]
    DIRECTION OUTPUT ;
    USE SIGNAL ;
    PORT
      LAYER M4 ;
        RECT  0 15.984 0.084 16.008 ;
    END
  END o[219]
  PIN o[21]
    DIRECTION OUTPUT ;
    USE SIGNAL ;
    PORT
      LAYER M4 ;
        RECT  0 43.824 0.084 43.848 ;
    END
  END o[21]
  PIN o[220]
    DIRECTION OUTPUT ;
    USE SIGNAL ;
    PORT
      LAYER M4 ;
        RECT  0 16.08 0.084 16.104 ;
    END
  END o[220]
  PIN o[221]
    DIRECTION OUTPUT ;
    USE SIGNAL ;
    PORT
      LAYER M4 ;
        RECT  0 16.176 0.084 16.2 ;
    END
  END o[221]
  PIN o[222]
    DIRECTION OUTPUT ;
    USE SIGNAL ;
    PORT
      LAYER M4 ;
        RECT  0 16.272 0.084 16.296 ;
    END
  END o[222]
  PIN o[223]
    DIRECTION OUTPUT ;
    USE SIGNAL ;
    PORT
      LAYER M4 ;
        RECT  0 16.368 0.084 16.392 ;
    END
  END o[223]
  PIN o[224]
    DIRECTION OUTPUT ;
    USE SIGNAL ;
    PORT
      LAYER M4 ;
        RECT  0 10.32 0.084 10.344 ;
    END
  END o[224]
  PIN o[225]
    DIRECTION OUTPUT ;
    USE SIGNAL ;
    PORT
      LAYER M4 ;
        RECT  0 10.416 0.084 10.44 ;
    END
  END o[225]
  PIN o[226]
    DIRECTION OUTPUT ;
    USE SIGNAL ;
    PORT
      LAYER M4 ;
        RECT  0 10.512 0.084 10.536 ;
    END
  END o[226]
  PIN o[227]
    DIRECTION OUTPUT ;
    USE SIGNAL ;
    PORT
      LAYER M4 ;
        RECT  0 10.608 0.084 10.632 ;
    END
  END o[227]
  PIN o[228]
    DIRECTION OUTPUT ;
    USE SIGNAL ;
    PORT
      LAYER M4 ;
        RECT  0 10.704 0.084 10.728 ;
    END
  END o[228]
  PIN o[229]
    DIRECTION OUTPUT ;
    USE SIGNAL ;
    PORT
      LAYER M4 ;
        RECT  0 10.8 0.084 10.824 ;
    END
  END o[229]
  PIN o[22]
    DIRECTION OUTPUT ;
    USE SIGNAL ;
    PORT
      LAYER M4 ;
        RECT  0 43.92 0.084 43.944 ;
    END
  END o[22]
  PIN o[230]
    DIRECTION OUTPUT ;
    USE SIGNAL ;
    PORT
      LAYER M4 ;
        RECT  0 10.896 0.084 10.92 ;
    END
  END o[230]
  PIN o[231]
    DIRECTION OUTPUT ;
    USE SIGNAL ;
    PORT
      LAYER M4 ;
        RECT  0 10.992 0.084 11.016 ;
    END
  END o[231]
  PIN o[232]
    DIRECTION OUTPUT ;
    USE SIGNAL ;
    PORT
      LAYER M4 ;
        RECT  0 11.088 0.084 11.112 ;
    END
  END o[232]
  PIN o[233]
    DIRECTION OUTPUT ;
    USE SIGNAL ;
    PORT
      LAYER M4 ;
        RECT  0 11.184 0.084 11.208 ;
    END
  END o[233]
  PIN o[234]
    DIRECTION OUTPUT ;
    USE SIGNAL ;
    PORT
      LAYER M4 ;
        RECT  0 11.28 0.084 11.304 ;
    END
  END o[234]
  PIN o[235]
    DIRECTION OUTPUT ;
    USE SIGNAL ;
    PORT
      LAYER M4 ;
        RECT  0 11.376 0.084 11.4 ;
    END
  END o[235]
  PIN o[236]
    DIRECTION OUTPUT ;
    USE SIGNAL ;
    PORT
      LAYER M4 ;
        RECT  0 11.472 0.084 11.496 ;
    END
  END o[236]
  PIN o[237]
    DIRECTION OUTPUT ;
    USE SIGNAL ;
    PORT
      LAYER M4 ;
        RECT  0 11.568 0.084 11.592 ;
    END
  END o[237]
  PIN o[238]
    DIRECTION OUTPUT ;
    USE SIGNAL ;
    PORT
      LAYER M4 ;
        RECT  0 11.664 0.084 11.688 ;
    END
  END o[238]
  PIN o[239]
    DIRECTION OUTPUT ;
    USE SIGNAL ;
    PORT
      LAYER M4 ;
        RECT  0 11.76 0.084 11.784 ;
    END
  END o[239]
  PIN o[23]
    DIRECTION OUTPUT ;
    USE SIGNAL ;
    PORT
      LAYER M4 ;
        RECT  0 44.016 0.084 44.04 ;
    END
  END o[23]
  PIN o[240]
    DIRECTION OUTPUT ;
    USE SIGNAL ;
    PORT
      LAYER M4 ;
        RECT  0 11.856 0.084 11.88 ;
    END
  END o[240]
  PIN o[241]
    DIRECTION OUTPUT ;
    USE SIGNAL ;
    PORT
      LAYER M4 ;
        RECT  0 11.952 0.084 11.976 ;
    END
  END o[241]
  PIN o[242]
    DIRECTION OUTPUT ;
    USE SIGNAL ;
    PORT
      LAYER M4 ;
        RECT  0 12.048 0.084 12.072 ;
    END
  END o[242]
  PIN o[243]
    DIRECTION OUTPUT ;
    USE SIGNAL ;
    PORT
      LAYER M4 ;
        RECT  0 12.144 0.084 12.168 ;
    END
  END o[243]
  PIN o[244]
    DIRECTION OUTPUT ;
    USE SIGNAL ;
    PORT
      LAYER M4 ;
        RECT  0 12.24 0.084 12.264 ;
    END
  END o[244]
  PIN o[245]
    DIRECTION OUTPUT ;
    USE SIGNAL ;
    PORT
      LAYER M4 ;
        RECT  0 12.336 0.084 12.36 ;
    END
  END o[245]
  PIN o[246]
    DIRECTION OUTPUT ;
    USE SIGNAL ;
    PORT
      LAYER M4 ;
        RECT  0 12.432 0.084 12.456 ;
    END
  END o[246]
  PIN o[247]
    DIRECTION OUTPUT ;
    USE SIGNAL ;
    PORT
      LAYER M4 ;
        RECT  0 12.528 0.084 12.552 ;
    END
  END o[247]
  PIN o[248]
    DIRECTION OUTPUT ;
    USE SIGNAL ;
    PORT
      LAYER M4 ;
        RECT  0 12.624 0.084 12.648 ;
    END
  END o[248]
  PIN o[249]
    DIRECTION OUTPUT ;
    USE SIGNAL ;
    PORT
      LAYER M4 ;
        RECT  0 12.72 0.084 12.744 ;
    END
  END o[249]
  PIN o[24]
    DIRECTION OUTPUT ;
    USE SIGNAL ;
    PORT
      LAYER M4 ;
        RECT  0 44.112 0.084 44.136 ;
    END
  END o[24]
  PIN o[250]
    DIRECTION OUTPUT ;
    USE SIGNAL ;
    PORT
      LAYER M4 ;
        RECT  0 12.816 0.084 12.84 ;
    END
  END o[250]
  PIN o[251]
    DIRECTION OUTPUT ;
    USE SIGNAL ;
    PORT
      LAYER M4 ;
        RECT  0 12.912 0.084 12.936 ;
    END
  END o[251]
  PIN o[252]
    DIRECTION OUTPUT ;
    USE SIGNAL ;
    PORT
      LAYER M4 ;
        RECT  0 13.008 0.084 13.032 ;
    END
  END o[252]
  PIN o[253]
    DIRECTION OUTPUT ;
    USE SIGNAL ;
    PORT
      LAYER M4 ;
        RECT  0 13.104 0.084 13.128 ;
    END
  END o[253]
  PIN o[254]
    DIRECTION OUTPUT ;
    USE SIGNAL ;
    PORT
      LAYER M4 ;
        RECT  0 13.2 0.084 13.224 ;
    END
  END o[254]
  PIN o[255]
    DIRECTION OUTPUT ;
    USE SIGNAL ;
    PORT
      LAYER M4 ;
        RECT  0 13.296 0.084 13.32 ;
    END
  END o[255]
  PIN o[256]
    DIRECTION OUTPUT ;
    USE SIGNAL ;
    PORT
      LAYER M4 ;
        RECT  0 45.648 0.084 45.672 ;
    END
  END o[256]
  PIN o[257]
    DIRECTION OUTPUT ;
    USE SIGNAL ;
    PORT
      LAYER M4 ;
        RECT  0 45.744 0.084 45.768 ;
    END
  END o[257]
  PIN o[258]
    DIRECTION OUTPUT ;
    USE SIGNAL ;
    PORT
      LAYER M4 ;
        RECT  0 45.84 0.084 45.864 ;
    END
  END o[258]
  PIN o[259]
    DIRECTION OUTPUT ;
    USE SIGNAL ;
    PORT
      LAYER M4 ;
        RECT  0 45.936 0.084 45.96 ;
    END
  END o[259]
  PIN o[25]
    DIRECTION OUTPUT ;
    USE SIGNAL ;
    PORT
      LAYER M4 ;
        RECT  0 44.208 0.084 44.232 ;
    END
  END o[25]
  PIN o[260]
    DIRECTION OUTPUT ;
    USE SIGNAL ;
    PORT
      LAYER M4 ;
        RECT  0 46.032 0.084 46.056 ;
    END
  END o[260]
  PIN o[261]
    DIRECTION OUTPUT ;
    USE SIGNAL ;
    PORT
      LAYER M4 ;
        RECT  0 46.128 0.084 46.152 ;
    END
  END o[261]
  PIN o[262]
    DIRECTION OUTPUT ;
    USE SIGNAL ;
    PORT
      LAYER M4 ;
        RECT  0 46.224 0.084 46.248 ;
    END
  END o[262]
  PIN o[263]
    DIRECTION OUTPUT ;
    USE SIGNAL ;
    PORT
      LAYER M4 ;
        RECT  0 46.32 0.084 46.344 ;
    END
  END o[263]
  PIN o[264]
    DIRECTION OUTPUT ;
    USE SIGNAL ;
    PORT
      LAYER M4 ;
        RECT  0 46.416 0.084 46.44 ;
    END
  END o[264]
  PIN o[265]
    DIRECTION OUTPUT ;
    USE SIGNAL ;
    PORT
      LAYER M4 ;
        RECT  0 46.512 0.084 46.536 ;
    END
  END o[265]
  PIN o[266]
    DIRECTION OUTPUT ;
    USE SIGNAL ;
    PORT
      LAYER M4 ;
        RECT  0 46.608 0.084 46.632 ;
    END
  END o[266]
  PIN o[267]
    DIRECTION OUTPUT ;
    USE SIGNAL ;
    PORT
      LAYER M4 ;
        RECT  0 46.704 0.084 46.728 ;
    END
  END o[267]
  PIN o[268]
    DIRECTION OUTPUT ;
    USE SIGNAL ;
    PORT
      LAYER M4 ;
        RECT  0 46.8 0.084 46.824 ;
    END
  END o[268]
  PIN o[269]
    DIRECTION OUTPUT ;
    USE SIGNAL ;
    PORT
      LAYER M4 ;
        RECT  0 46.896 0.084 46.92 ;
    END
  END o[269]
  PIN o[26]
    DIRECTION OUTPUT ;
    USE SIGNAL ;
    PORT
      LAYER M4 ;
        RECT  0 44.304 0.084 44.328 ;
    END
  END o[26]
  PIN o[270]
    DIRECTION OUTPUT ;
    USE SIGNAL ;
    PORT
      LAYER M4 ;
        RECT  0 46.992 0.084 47.016 ;
    END
  END o[270]
  PIN o[271]
    DIRECTION OUTPUT ;
    USE SIGNAL ;
    PORT
      LAYER M4 ;
        RECT  0 47.088 0.084 47.112 ;
    END
  END o[271]
  PIN o[272]
    DIRECTION OUTPUT ;
    USE SIGNAL ;
    PORT
      LAYER M4 ;
        RECT  0 47.184 0.084 47.208 ;
    END
  END o[272]
  PIN o[273]
    DIRECTION OUTPUT ;
    USE SIGNAL ;
    PORT
      LAYER M4 ;
        RECT  0 47.28 0.084 47.304 ;
    END
  END o[273]
  PIN o[274]
    DIRECTION OUTPUT ;
    USE SIGNAL ;
    PORT
      LAYER M4 ;
        RECT  0 47.376 0.084 47.4 ;
    END
  END o[274]
  PIN o[275]
    DIRECTION OUTPUT ;
    USE SIGNAL ;
    PORT
      LAYER M4 ;
        RECT  0 47.472 0.084 47.496 ;
    END
  END o[275]
  PIN o[276]
    DIRECTION OUTPUT ;
    USE SIGNAL ;
    PORT
      LAYER M4 ;
        RECT  0 47.568 0.084 47.592 ;
    END
  END o[276]
  PIN o[277]
    DIRECTION OUTPUT ;
    USE SIGNAL ;
    PORT
      LAYER M4 ;
        RECT  0 47.664 0.084 47.688 ;
    END
  END o[277]
  PIN o[278]
    DIRECTION OUTPUT ;
    USE SIGNAL ;
    PORT
      LAYER M4 ;
        RECT  0 47.76 0.084 47.784 ;
    END
  END o[278]
  PIN o[279]
    DIRECTION OUTPUT ;
    USE SIGNAL ;
    PORT
      LAYER M4 ;
        RECT  0 47.856 0.084 47.88 ;
    END
  END o[279]
  PIN o[27]
    DIRECTION OUTPUT ;
    USE SIGNAL ;
    PORT
      LAYER M4 ;
        RECT  0 44.4 0.084 44.424 ;
    END
  END o[27]
  PIN o[280]
    DIRECTION OUTPUT ;
    USE SIGNAL ;
    PORT
      LAYER M4 ;
        RECT  0 47.952 0.084 47.976 ;
    END
  END o[280]
  PIN o[281]
    DIRECTION OUTPUT ;
    USE SIGNAL ;
    PORT
      LAYER M4 ;
        RECT  0 48.048 0.084 48.072 ;
    END
  END o[281]
  PIN o[282]
    DIRECTION OUTPUT ;
    USE SIGNAL ;
    PORT
      LAYER M4 ;
        RECT  0 48.144 0.084 48.168 ;
    END
  END o[282]
  PIN o[283]
    DIRECTION OUTPUT ;
    USE SIGNAL ;
    PORT
      LAYER M4 ;
        RECT  0 48.24 0.084 48.264 ;
    END
  END o[283]
  PIN o[284]
    DIRECTION OUTPUT ;
    USE SIGNAL ;
    PORT
      LAYER M4 ;
        RECT  0 48.336 0.084 48.36 ;
    END
  END o[284]
  PIN o[285]
    DIRECTION OUTPUT ;
    USE SIGNAL ;
    PORT
      LAYER M4 ;
        RECT  0 48.432 0.084 48.456 ;
    END
  END o[285]
  PIN o[286]
    DIRECTION OUTPUT ;
    USE SIGNAL ;
    PORT
      LAYER M4 ;
        RECT  0 48.528 0.084 48.552 ;
    END
  END o[286]
  PIN o[287]
    DIRECTION OUTPUT ;
    USE SIGNAL ;
    PORT
      LAYER M4 ;
        RECT  0 48.624 0.084 48.648 ;
    END
  END o[287]
  PIN o[288]
    DIRECTION OUTPUT ;
    USE SIGNAL ;
    PORT
      LAYER M4 ;
        RECT  0 48.72 0.084 48.744 ;
    END
  END o[288]
  PIN o[289]
    DIRECTION OUTPUT ;
    USE SIGNAL ;
    PORT
      LAYER M4 ;
        RECT  0 48.816 0.084 48.84 ;
    END
  END o[289]
  PIN o[28]
    DIRECTION OUTPUT ;
    USE SIGNAL ;
    PORT
      LAYER M4 ;
        RECT  0 44.496 0.084 44.52 ;
    END
  END o[28]
  PIN o[290]
    DIRECTION OUTPUT ;
    USE SIGNAL ;
    PORT
      LAYER M4 ;
        RECT  0 48.912 0.084 48.936 ;
    END
  END o[290]
  PIN o[291]
    DIRECTION OUTPUT ;
    USE SIGNAL ;
    PORT
      LAYER M4 ;
        RECT  0 49.008 0.084 49.032 ;
    END
  END o[291]
  PIN o[292]
    DIRECTION OUTPUT ;
    USE SIGNAL ;
    PORT
      LAYER M4 ;
        RECT  0 49.104 0.084 49.128 ;
    END
  END o[292]
  PIN o[293]
    DIRECTION OUTPUT ;
    USE SIGNAL ;
    PORT
      LAYER M4 ;
        RECT  0 49.2 0.084 49.224 ;
    END
  END o[293]
  PIN o[294]
    DIRECTION OUTPUT ;
    USE SIGNAL ;
    PORT
      LAYER M4 ;
        RECT  0 49.296 0.084 49.32 ;
    END
  END o[294]
  PIN o[295]
    DIRECTION OUTPUT ;
    USE SIGNAL ;
    PORT
      LAYER M4 ;
        RECT  0 49.392 0.084 49.416 ;
    END
  END o[295]
  PIN o[296]
    DIRECTION OUTPUT ;
    USE SIGNAL ;
    PORT
      LAYER M4 ;
        RECT  0 49.488 0.084 49.512 ;
    END
  END o[296]
  PIN o[297]
    DIRECTION OUTPUT ;
    USE SIGNAL ;
    PORT
      LAYER M4 ;
        RECT  0 49.584 0.084 49.608 ;
    END
  END o[297]
  PIN o[298]
    DIRECTION OUTPUT ;
    USE SIGNAL ;
    PORT
      LAYER M4 ;
        RECT  0 49.68 0.084 49.704 ;
    END
  END o[298]
  PIN o[299]
    DIRECTION OUTPUT ;
    USE SIGNAL ;
    PORT
      LAYER M4 ;
        RECT  0 49.776 0.084 49.8 ;
    END
  END o[299]
  PIN o[29]
    DIRECTION OUTPUT ;
    USE SIGNAL ;
    PORT
      LAYER M4 ;
        RECT  0 44.592 0.084 44.616 ;
    END
  END o[29]
  PIN o[2]
    DIRECTION OUTPUT ;
    USE SIGNAL ;
    PORT
      LAYER M4 ;
        RECT  0 42 0.084 42.024 ;
    END
  END o[2]
  PIN o[300]
    DIRECTION OUTPUT ;
    USE SIGNAL ;
    PORT
      LAYER M4 ;
        RECT  0 49.872 0.084 49.896 ;
    END
  END o[300]
  PIN o[301]
    DIRECTION OUTPUT ;
    USE SIGNAL ;
    PORT
      LAYER M4 ;
        RECT  0 49.968 0.084 49.992 ;
    END
  END o[301]
  PIN o[302]
    DIRECTION OUTPUT ;
    USE SIGNAL ;
    PORT
      LAYER M4 ;
        RECT  0 50.064 0.084 50.088 ;
    END
  END o[302]
  PIN o[303]
    DIRECTION OUTPUT ;
    USE SIGNAL ;
    PORT
      LAYER M4 ;
        RECT  0 50.16 0.084 50.184 ;
    END
  END o[303]
  PIN o[304]
    DIRECTION OUTPUT ;
    USE SIGNAL ;
    PORT
      LAYER M4 ;
        RECT  0 50.256 0.084 50.28 ;
    END
  END o[304]
  PIN o[305]
    DIRECTION OUTPUT ;
    USE SIGNAL ;
    PORT
      LAYER M4 ;
        RECT  0 50.352 0.084 50.376 ;
    END
  END o[305]
  PIN o[306]
    DIRECTION OUTPUT ;
    USE SIGNAL ;
    PORT
      LAYER M4 ;
        RECT  0 50.448 0.084 50.472 ;
    END
  END o[306]
  PIN o[307]
    DIRECTION OUTPUT ;
    USE SIGNAL ;
    PORT
      LAYER M4 ;
        RECT  0 50.544 0.084 50.568 ;
    END
  END o[307]
  PIN o[308]
    DIRECTION OUTPUT ;
    USE SIGNAL ;
    PORT
      LAYER M4 ;
        RECT  0 50.64 0.084 50.664 ;
    END
  END o[308]
  PIN o[309]
    DIRECTION OUTPUT ;
    USE SIGNAL ;
    PORT
      LAYER M4 ;
        RECT  0 50.736 0.084 50.76 ;
    END
  END o[309]
  PIN o[30]
    DIRECTION OUTPUT ;
    USE SIGNAL ;
    PORT
      LAYER M4 ;
        RECT  0 44.688 0.084 44.712 ;
    END
  END o[30]
  PIN o[310]
    DIRECTION OUTPUT ;
    USE SIGNAL ;
    PORT
      LAYER M4 ;
        RECT  0 50.832 0.084 50.856 ;
    END
  END o[310]
  PIN o[311]
    DIRECTION OUTPUT ;
    USE SIGNAL ;
    PORT
      LAYER M4 ;
        RECT  0 50.928 0.084 50.952 ;
    END
  END o[311]
  PIN o[312]
    DIRECTION OUTPUT ;
    USE SIGNAL ;
    PORT
      LAYER M4 ;
        RECT  0 51.024 0.084 51.048 ;
    END
  END o[312]
  PIN o[313]
    DIRECTION OUTPUT ;
    USE SIGNAL ;
    PORT
      LAYER M4 ;
        RECT  0 51.12 0.084 51.144 ;
    END
  END o[313]
  PIN o[314]
    DIRECTION OUTPUT ;
    USE SIGNAL ;
    PORT
      LAYER M4 ;
        RECT  0 51.216 0.084 51.24 ;
    END
  END o[314]
  PIN o[315]
    DIRECTION OUTPUT ;
    USE SIGNAL ;
    PORT
      LAYER M4 ;
        RECT  0 51.312 0.084 51.336 ;
    END
  END o[315]
  PIN o[316]
    DIRECTION OUTPUT ;
    USE SIGNAL ;
    PORT
      LAYER M4 ;
        RECT  0 51.408 0.084 51.432 ;
    END
  END o[316]
  PIN o[317]
    DIRECTION OUTPUT ;
    USE SIGNAL ;
    PORT
      LAYER M4 ;
        RECT  0 51.504 0.084 51.528 ;
    END
  END o[317]
  PIN o[318]
    DIRECTION OUTPUT ;
    USE SIGNAL ;
    PORT
      LAYER M4 ;
        RECT  0 51.6 0.084 51.624 ;
    END
  END o[318]
  PIN o[319]
    DIRECTION OUTPUT ;
    USE SIGNAL ;
    PORT
      LAYER M4 ;
        RECT  0 51.696 0.084 51.72 ;
    END
  END o[319]
  PIN o[31]
    DIRECTION OUTPUT ;
    USE SIGNAL ;
    PORT
      LAYER M4 ;
        RECT  0 44.784 0.084 44.808 ;
    END
  END o[31]
  PIN o[320]
    DIRECTION OUTPUT ;
    USE SIGNAL ;
    PORT
      LAYER M4 ;
        RECT  0 51.792 0.084 51.816 ;
    END
  END o[320]
  PIN o[321]
    DIRECTION OUTPUT ;
    USE SIGNAL ;
    PORT
      LAYER M4 ;
        RECT  0 51.888 0.084 51.912 ;
    END
  END o[321]
  PIN o[322]
    DIRECTION OUTPUT ;
    USE SIGNAL ;
    PORT
      LAYER M4 ;
        RECT  0 51.984 0.084 52.008 ;
    END
  END o[322]
  PIN o[323]
    DIRECTION OUTPUT ;
    USE SIGNAL ;
    PORT
      LAYER M4 ;
        RECT  0 52.08 0.084 52.104 ;
    END
  END o[323]
  PIN o[324]
    DIRECTION OUTPUT ;
    USE SIGNAL ;
    PORT
      LAYER M4 ;
        RECT  0 52.176 0.084 52.2 ;
    END
  END o[324]
  PIN o[325]
    DIRECTION OUTPUT ;
    USE SIGNAL ;
    PORT
      LAYER M4 ;
        RECT  0 52.272 0.084 52.296 ;
    END
  END o[325]
  PIN o[326]
    DIRECTION OUTPUT ;
    USE SIGNAL ;
    PORT
      LAYER M4 ;
        RECT  0 52.368 0.084 52.392 ;
    END
  END o[326]
  PIN o[327]
    DIRECTION OUTPUT ;
    USE SIGNAL ;
    PORT
      LAYER M4 ;
        RECT  0 52.464 0.084 52.488 ;
    END
  END o[327]
  PIN o[328]
    DIRECTION OUTPUT ;
    USE SIGNAL ;
    PORT
      LAYER M4 ;
        RECT  0 52.56 0.084 52.584 ;
    END
  END o[328]
  PIN o[329]
    DIRECTION OUTPUT ;
    USE SIGNAL ;
    PORT
      LAYER M4 ;
        RECT  0 52.656 0.084 52.68 ;
    END
  END o[329]
  PIN o[32]
    DIRECTION OUTPUT ;
    USE SIGNAL ;
    PORT
      LAYER M4 ;
        RECT  0 32.592 0.084 32.616 ;
    END
  END o[32]
  PIN o[330]
    DIRECTION OUTPUT ;
    USE SIGNAL ;
    PORT
      LAYER M4 ;
        RECT  0 52.752 0.084 52.776 ;
    END
  END o[330]
  PIN o[331]
    DIRECTION OUTPUT ;
    USE SIGNAL ;
    PORT
      LAYER M4 ;
        RECT  0 52.848 0.084 52.872 ;
    END
  END o[331]
  PIN o[332]
    DIRECTION OUTPUT ;
    USE SIGNAL ;
    PORT
      LAYER M4 ;
        RECT  0 52.944 0.084 52.968 ;
    END
  END o[332]
  PIN o[333]
    DIRECTION OUTPUT ;
    USE SIGNAL ;
    PORT
      LAYER M4 ;
        RECT  0 53.04 0.084 53.064 ;
    END
  END o[333]
  PIN o[334]
    DIRECTION OUTPUT ;
    USE SIGNAL ;
    PORT
      LAYER M4 ;
        RECT  0 53.136 0.084 53.16 ;
    END
  END o[334]
  PIN o[335]
    DIRECTION OUTPUT ;
    USE SIGNAL ;
    PORT
      LAYER M4 ;
        RECT  0 53.232 0.084 53.256 ;
    END
  END o[335]
  PIN o[336]
    DIRECTION OUTPUT ;
    USE SIGNAL ;
    PORT
      LAYER M4 ;
        RECT  0 53.328 0.084 53.352 ;
    END
  END o[336]
  PIN o[337]
    DIRECTION OUTPUT ;
    USE SIGNAL ;
    PORT
      LAYER M4 ;
        RECT  0 53.424 0.084 53.448 ;
    END
  END o[337]
  PIN o[338]
    DIRECTION OUTPUT ;
    USE SIGNAL ;
    PORT
      LAYER M4 ;
        RECT  0 53.52 0.084 53.544 ;
    END
  END o[338]
  PIN o[339]
    DIRECTION OUTPUT ;
    USE SIGNAL ;
    PORT
      LAYER M4 ;
        RECT  0 53.616 0.084 53.64 ;
    END
  END o[339]
  PIN o[33]
    DIRECTION OUTPUT ;
    USE SIGNAL ;
    PORT
      LAYER M4 ;
        RECT  0 32.688 0.084 32.712 ;
    END
  END o[33]
  PIN o[340]
    DIRECTION OUTPUT ;
    USE SIGNAL ;
    PORT
      LAYER M4 ;
        RECT  0 53.712 0.084 53.736 ;
    END
  END o[340]
  PIN o[341]
    DIRECTION OUTPUT ;
    USE SIGNAL ;
    PORT
      LAYER M4 ;
        RECT  0 53.808 0.084 53.832 ;
    END
  END o[341]
  PIN o[342]
    DIRECTION OUTPUT ;
    USE SIGNAL ;
    PORT
      LAYER M4 ;
        RECT  0 53.904 0.084 53.928 ;
    END
  END o[342]
  PIN o[343]
    DIRECTION OUTPUT ;
    USE SIGNAL ;
    PORT
      LAYER M4 ;
        RECT  0 54 0.084 54.024 ;
    END
  END o[343]
  PIN o[344]
    DIRECTION OUTPUT ;
    USE SIGNAL ;
    PORT
      LAYER M4 ;
        RECT  0 54.096 0.084 54.12 ;
    END
  END o[344]
  PIN o[345]
    DIRECTION OUTPUT ;
    USE SIGNAL ;
    PORT
      LAYER M4 ;
        RECT  0 54.192 0.084 54.216 ;
    END
  END o[345]
  PIN o[346]
    DIRECTION OUTPUT ;
    USE SIGNAL ;
    PORT
      LAYER M4 ;
        RECT  0 54.288 0.084 54.312 ;
    END
  END o[346]
  PIN o[347]
    DIRECTION OUTPUT ;
    USE SIGNAL ;
    PORT
      LAYER M4 ;
        RECT  0 54.384 0.084 54.408 ;
    END
  END o[347]
  PIN o[348]
    DIRECTION OUTPUT ;
    USE SIGNAL ;
    PORT
      LAYER M4 ;
        RECT  0 54.48 0.084 54.504 ;
    END
  END o[348]
  PIN o[349]
    DIRECTION OUTPUT ;
    USE SIGNAL ;
    PORT
      LAYER M4 ;
        RECT  0 54.576 0.084 54.6 ;
    END
  END o[349]
  PIN o[34]
    DIRECTION OUTPUT ;
    USE SIGNAL ;
    PORT
      LAYER M4 ;
        RECT  0 32.784 0.084 32.808 ;
    END
  END o[34]
  PIN o[350]
    DIRECTION OUTPUT ;
    USE SIGNAL ;
    PORT
      LAYER M4 ;
        RECT  0 54.672 0.084 54.696 ;
    END
  END o[350]
  PIN o[351]
    DIRECTION OUTPUT ;
    USE SIGNAL ;
    PORT
      LAYER M4 ;
        RECT  0 54.768 0.084 54.792 ;
    END
  END o[351]
  PIN o[352]
    DIRECTION OUTPUT ;
    USE SIGNAL ;
    PORT
      LAYER M4 ;
        RECT  0 61.008 0.084 61.032 ;
    END
  END o[352]
  PIN o[353]
    DIRECTION OUTPUT ;
    USE SIGNAL ;
    PORT
      LAYER M4 ;
        RECT  0 61.104 0.084 61.128 ;
    END
  END o[353]
  PIN o[354]
    DIRECTION OUTPUT ;
    USE SIGNAL ;
    PORT
      LAYER M4 ;
        RECT  0 61.2 0.084 61.224 ;
    END
  END o[354]
  PIN o[355]
    DIRECTION OUTPUT ;
    USE SIGNAL ;
    PORT
      LAYER M4 ;
        RECT  0 61.296 0.084 61.32 ;
    END
  END o[355]
  PIN o[356]
    DIRECTION OUTPUT ;
    USE SIGNAL ;
    PORT
      LAYER M4 ;
        RECT  0 61.392 0.084 61.416 ;
    END
  END o[356]
  PIN o[357]
    DIRECTION OUTPUT ;
    USE SIGNAL ;
    PORT
      LAYER M4 ;
        RECT  0 61.488 0.084 61.512 ;
    END
  END o[357]
  PIN o[358]
    DIRECTION OUTPUT ;
    USE SIGNAL ;
    PORT
      LAYER M4 ;
        RECT  0 61.584 0.084 61.608 ;
    END
  END o[358]
  PIN o[359]
    DIRECTION OUTPUT ;
    USE SIGNAL ;
    PORT
      LAYER M4 ;
        RECT  0 61.68 0.084 61.704 ;
    END
  END o[359]
  PIN o[35]
    DIRECTION OUTPUT ;
    USE SIGNAL ;
    PORT
      LAYER M4 ;
        RECT  0 32.88 0.084 32.904 ;
    END
  END o[35]
  PIN o[360]
    DIRECTION OUTPUT ;
    USE SIGNAL ;
    PORT
      LAYER M4 ;
        RECT  0 61.776 0.084 61.8 ;
    END
  END o[360]
  PIN o[361]
    DIRECTION OUTPUT ;
    USE SIGNAL ;
    PORT
      LAYER M4 ;
        RECT  0 61.872 0.084 61.896 ;
    END
  END o[361]
  PIN o[362]
    DIRECTION OUTPUT ;
    USE SIGNAL ;
    PORT
      LAYER M4 ;
        RECT  0 61.968 0.084 61.992 ;
    END
  END o[362]
  PIN o[363]
    DIRECTION OUTPUT ;
    USE SIGNAL ;
    PORT
      LAYER M4 ;
        RECT  0 62.064 0.084 62.088 ;
    END
  END o[363]
  PIN o[364]
    DIRECTION OUTPUT ;
    USE SIGNAL ;
    PORT
      LAYER M4 ;
        RECT  0 62.16 0.084 62.184 ;
    END
  END o[364]
  PIN o[365]
    DIRECTION OUTPUT ;
    USE SIGNAL ;
    PORT
      LAYER M4 ;
        RECT  0 62.256 0.084 62.28 ;
    END
  END o[365]
  PIN o[366]
    DIRECTION OUTPUT ;
    USE SIGNAL ;
    PORT
      LAYER M4 ;
        RECT  0 62.352 0.084 62.376 ;
    END
  END o[366]
  PIN o[367]
    DIRECTION OUTPUT ;
    USE SIGNAL ;
    PORT
      LAYER M4 ;
        RECT  0 62.448 0.084 62.472 ;
    END
  END o[367]
  PIN o[368]
    DIRECTION OUTPUT ;
    USE SIGNAL ;
    PORT
      LAYER M4 ;
        RECT  0 62.544 0.084 62.568 ;
    END
  END o[368]
  PIN o[369]
    DIRECTION OUTPUT ;
    USE SIGNAL ;
    PORT
      LAYER M4 ;
        RECT  0 62.64 0.084 62.664 ;
    END
  END o[369]
  PIN o[36]
    DIRECTION OUTPUT ;
    USE SIGNAL ;
    PORT
      LAYER M4 ;
        RECT  0 32.976 0.084 33 ;
    END
  END o[36]
  PIN o[370]
    DIRECTION OUTPUT ;
    USE SIGNAL ;
    PORT
      LAYER M4 ;
        RECT  0 62.736 0.084 62.76 ;
    END
  END o[370]
  PIN o[371]
    DIRECTION OUTPUT ;
    USE SIGNAL ;
    PORT
      LAYER M4 ;
        RECT  0 62.832 0.084 62.856 ;
    END
  END o[371]
  PIN o[372]
    DIRECTION OUTPUT ;
    USE SIGNAL ;
    PORT
      LAYER M4 ;
        RECT  0 62.928 0.084 62.952 ;
    END
  END o[372]
  PIN o[373]
    DIRECTION OUTPUT ;
    USE SIGNAL ;
    PORT
      LAYER M4 ;
        RECT  0 63.024 0.084 63.048 ;
    END
  END o[373]
  PIN o[374]
    DIRECTION OUTPUT ;
    USE SIGNAL ;
    PORT
      LAYER M4 ;
        RECT  0 63.12 0.084 63.144 ;
    END
  END o[374]
  PIN o[375]
    DIRECTION OUTPUT ;
    USE SIGNAL ;
    PORT
      LAYER M4 ;
        RECT  0 63.216 0.084 63.24 ;
    END
  END o[375]
  PIN o[376]
    DIRECTION OUTPUT ;
    USE SIGNAL ;
    PORT
      LAYER M4 ;
        RECT  0 63.312 0.084 63.336 ;
    END
  END o[376]
  PIN o[377]
    DIRECTION OUTPUT ;
    USE SIGNAL ;
    PORT
      LAYER M4 ;
        RECT  0 63.408 0.084 63.432 ;
    END
  END o[377]
  PIN o[378]
    DIRECTION OUTPUT ;
    USE SIGNAL ;
    PORT
      LAYER M4 ;
        RECT  0 63.504 0.084 63.528 ;
    END
  END o[378]
  PIN o[379]
    DIRECTION OUTPUT ;
    USE SIGNAL ;
    PORT
      LAYER M4 ;
        RECT  0 63.6 0.084 63.624 ;
    END
  END o[379]
  PIN o[37]
    DIRECTION OUTPUT ;
    USE SIGNAL ;
    PORT
      LAYER M4 ;
        RECT  0 33.072 0.084 33.096 ;
    END
  END o[37]
  PIN o[380]
    DIRECTION OUTPUT ;
    USE SIGNAL ;
    PORT
      LAYER M4 ;
        RECT  0 63.696 0.084 63.72 ;
    END
  END o[380]
  PIN o[381]
    DIRECTION OUTPUT ;
    USE SIGNAL ;
    PORT
      LAYER M4 ;
        RECT  0 63.792 0.084 63.816 ;
    END
  END o[381]
  PIN o[382]
    DIRECTION OUTPUT ;
    USE SIGNAL ;
    PORT
      LAYER M4 ;
        RECT  0 63.888 0.084 63.912 ;
    END
  END o[382]
  PIN o[383]
    DIRECTION OUTPUT ;
    USE SIGNAL ;
    PORT
      LAYER M4 ;
        RECT  0 63.984 0.084 64.008 ;
    END
  END o[383]
  PIN o[384]
    DIRECTION OUTPUT ;
    USE SIGNAL ;
    PORT
      LAYER M4 ;
        RECT  0 54.864 0.084 54.888 ;
    END
  END o[384]
  PIN o[385]
    DIRECTION OUTPUT ;
    USE SIGNAL ;
    PORT
      LAYER M4 ;
        RECT  0 54.96 0.084 54.984 ;
    END
  END o[385]
  PIN o[386]
    DIRECTION OUTPUT ;
    USE SIGNAL ;
    PORT
      LAYER M4 ;
        RECT  0 55.056 0.084 55.08 ;
    END
  END o[386]
  PIN o[387]
    DIRECTION OUTPUT ;
    USE SIGNAL ;
    PORT
      LAYER M4 ;
        RECT  0 55.152 0.084 55.176 ;
    END
  END o[387]
  PIN o[388]
    DIRECTION OUTPUT ;
    USE SIGNAL ;
    PORT
      LAYER M4 ;
        RECT  0 55.248 0.084 55.272 ;
    END
  END o[388]
  PIN o[389]
    DIRECTION OUTPUT ;
    USE SIGNAL ;
    PORT
      LAYER M4 ;
        RECT  0 55.344 0.084 55.368 ;
    END
  END o[389]
  PIN o[38]
    DIRECTION OUTPUT ;
    USE SIGNAL ;
    PORT
      LAYER M4 ;
        RECT  0 33.168 0.084 33.192 ;
    END
  END o[38]
  PIN o[390]
    DIRECTION OUTPUT ;
    USE SIGNAL ;
    PORT
      LAYER M4 ;
        RECT  0 55.44 0.084 55.464 ;
    END
  END o[390]
  PIN o[391]
    DIRECTION OUTPUT ;
    USE SIGNAL ;
    PORT
      LAYER M4 ;
        RECT  0 55.536 0.084 55.56 ;
    END
  END o[391]
  PIN o[392]
    DIRECTION OUTPUT ;
    USE SIGNAL ;
    PORT
      LAYER M4 ;
        RECT  0 55.632 0.084 55.656 ;
    END
  END o[392]
  PIN o[393]
    DIRECTION OUTPUT ;
    USE SIGNAL ;
    PORT
      LAYER M4 ;
        RECT  0 55.728 0.084 55.752 ;
    END
  END o[393]
  PIN o[394]
    DIRECTION OUTPUT ;
    USE SIGNAL ;
    PORT
      LAYER M4 ;
        RECT  0 55.824 0.084 55.848 ;
    END
  END o[394]
  PIN o[395]
    DIRECTION OUTPUT ;
    USE SIGNAL ;
    PORT
      LAYER M4 ;
        RECT  0 55.92 0.084 55.944 ;
    END
  END o[395]
  PIN o[396]
    DIRECTION OUTPUT ;
    USE SIGNAL ;
    PORT
      LAYER M4 ;
        RECT  0 56.016 0.084 56.04 ;
    END
  END o[396]
  PIN o[397]
    DIRECTION OUTPUT ;
    USE SIGNAL ;
    PORT
      LAYER M4 ;
        RECT  0 56.112 0.084 56.136 ;
    END
  END o[397]
  PIN o[398]
    DIRECTION OUTPUT ;
    USE SIGNAL ;
    PORT
      LAYER M4 ;
        RECT  0 56.208 0.084 56.232 ;
    END
  END o[398]
  PIN o[399]
    DIRECTION OUTPUT ;
    USE SIGNAL ;
    PORT
      LAYER M4 ;
        RECT  0 56.304 0.084 56.328 ;
    END
  END o[399]
  PIN o[39]
    DIRECTION OUTPUT ;
    USE SIGNAL ;
    PORT
      LAYER M4 ;
        RECT  0 33.264 0.084 33.288 ;
    END
  END o[39]
  PIN o[3]
    DIRECTION OUTPUT ;
    USE SIGNAL ;
    PORT
      LAYER M4 ;
        RECT  0 42.096 0.084 42.12 ;
    END
  END o[3]
  PIN o[400]
    DIRECTION OUTPUT ;
    USE SIGNAL ;
    PORT
      LAYER M4 ;
        RECT  0 56.4 0.084 56.424 ;
    END
  END o[400]
  PIN o[401]
    DIRECTION OUTPUT ;
    USE SIGNAL ;
    PORT
      LAYER M4 ;
        RECT  0 56.496 0.084 56.52 ;
    END
  END o[401]
  PIN o[402]
    DIRECTION OUTPUT ;
    USE SIGNAL ;
    PORT
      LAYER M4 ;
        RECT  0 56.592 0.084 56.616 ;
    END
  END o[402]
  PIN o[403]
    DIRECTION OUTPUT ;
    USE SIGNAL ;
    PORT
      LAYER M4 ;
        RECT  0 56.688 0.084 56.712 ;
    END
  END o[403]
  PIN o[404]
    DIRECTION OUTPUT ;
    USE SIGNAL ;
    PORT
      LAYER M4 ;
        RECT  0 56.784 0.084 56.808 ;
    END
  END o[404]
  PIN o[405]
    DIRECTION OUTPUT ;
    USE SIGNAL ;
    PORT
      LAYER M4 ;
        RECT  0 56.88 0.084 56.904 ;
    END
  END o[405]
  PIN o[406]
    DIRECTION OUTPUT ;
    USE SIGNAL ;
    PORT
      LAYER M4 ;
        RECT  0 56.976 0.084 57 ;
    END
  END o[406]
  PIN o[407]
    DIRECTION OUTPUT ;
    USE SIGNAL ;
    PORT
      LAYER M4 ;
        RECT  0 57.072 0.084 57.096 ;
    END
  END o[407]
  PIN o[408]
    DIRECTION OUTPUT ;
    USE SIGNAL ;
    PORT
      LAYER M4 ;
        RECT  0 57.168 0.084 57.192 ;
    END
  END o[408]
  PIN o[409]
    DIRECTION OUTPUT ;
    USE SIGNAL ;
    PORT
      LAYER M4 ;
        RECT  0 57.264 0.084 57.288 ;
    END
  END o[409]
  PIN o[40]
    DIRECTION OUTPUT ;
    USE SIGNAL ;
    PORT
      LAYER M4 ;
        RECT  0 33.36 0.084 33.384 ;
    END
  END o[40]
  PIN o[410]
    DIRECTION OUTPUT ;
    USE SIGNAL ;
    PORT
      LAYER M4 ;
        RECT  0 57.36 0.084 57.384 ;
    END
  END o[410]
  PIN o[411]
    DIRECTION OUTPUT ;
    USE SIGNAL ;
    PORT
      LAYER M4 ;
        RECT  0 57.456 0.084 57.48 ;
    END
  END o[411]
  PIN o[412]
    DIRECTION OUTPUT ;
    USE SIGNAL ;
    PORT
      LAYER M4 ;
        RECT  0 57.552 0.084 57.576 ;
    END
  END o[412]
  PIN o[413]
    DIRECTION OUTPUT ;
    USE SIGNAL ;
    PORT
      LAYER M4 ;
        RECT  0 57.648 0.084 57.672 ;
    END
  END o[413]
  PIN o[414]
    DIRECTION OUTPUT ;
    USE SIGNAL ;
    PORT
      LAYER M4 ;
        RECT  0 57.744 0.084 57.768 ;
    END
  END o[414]
  PIN o[415]
    DIRECTION OUTPUT ;
    USE SIGNAL ;
    PORT
      LAYER M4 ;
        RECT  0 57.84 0.084 57.864 ;
    END
  END o[415]
  PIN o[416]
    DIRECTION OUTPUT ;
    USE SIGNAL ;
    PORT
      LAYER M4 ;
        RECT  0 57.936 0.084 57.96 ;
    END
  END o[416]
  PIN o[417]
    DIRECTION OUTPUT ;
    USE SIGNAL ;
    PORT
      LAYER M4 ;
        RECT  0 58.032 0.084 58.056 ;
    END
  END o[417]
  PIN o[418]
    DIRECTION OUTPUT ;
    USE SIGNAL ;
    PORT
      LAYER M4 ;
        RECT  0 58.128 0.084 58.152 ;
    END
  END o[418]
  PIN o[419]
    DIRECTION OUTPUT ;
    USE SIGNAL ;
    PORT
      LAYER M4 ;
        RECT  0 58.224 0.084 58.248 ;
    END
  END o[419]
  PIN o[41]
    DIRECTION OUTPUT ;
    USE SIGNAL ;
    PORT
      LAYER M4 ;
        RECT  0 33.456 0.084 33.48 ;
    END
  END o[41]
  PIN o[420]
    DIRECTION OUTPUT ;
    USE SIGNAL ;
    PORT
      LAYER M4 ;
        RECT  0 58.32 0.084 58.344 ;
    END
  END o[420]
  PIN o[421]
    DIRECTION OUTPUT ;
    USE SIGNAL ;
    PORT
      LAYER M4 ;
        RECT  0 58.416 0.084 58.44 ;
    END
  END o[421]
  PIN o[422]
    DIRECTION OUTPUT ;
    USE SIGNAL ;
    PORT
      LAYER M4 ;
        RECT  0 58.512 0.084 58.536 ;
    END
  END o[422]
  PIN o[423]
    DIRECTION OUTPUT ;
    USE SIGNAL ;
    PORT
      LAYER M4 ;
        RECT  0 58.608 0.084 58.632 ;
    END
  END o[423]
  PIN o[424]
    DIRECTION OUTPUT ;
    USE SIGNAL ;
    PORT
      LAYER M4 ;
        RECT  0 58.704 0.084 58.728 ;
    END
  END o[424]
  PIN o[425]
    DIRECTION OUTPUT ;
    USE SIGNAL ;
    PORT
      LAYER M4 ;
        RECT  0 58.8 0.084 58.824 ;
    END
  END o[425]
  PIN o[426]
    DIRECTION OUTPUT ;
    USE SIGNAL ;
    PORT
      LAYER M4 ;
        RECT  0 58.896 0.084 58.92 ;
    END
  END o[426]
  PIN o[427]
    DIRECTION OUTPUT ;
    USE SIGNAL ;
    PORT
      LAYER M4 ;
        RECT  0 58.992 0.084 59.016 ;
    END
  END o[427]
  PIN o[428]
    DIRECTION OUTPUT ;
    USE SIGNAL ;
    PORT
      LAYER M4 ;
        RECT  0 59.088 0.084 59.112 ;
    END
  END o[428]
  PIN o[429]
    DIRECTION OUTPUT ;
    USE SIGNAL ;
    PORT
      LAYER M4 ;
        RECT  0 59.184 0.084 59.208 ;
    END
  END o[429]
  PIN o[42]
    DIRECTION OUTPUT ;
    USE SIGNAL ;
    PORT
      LAYER M4 ;
        RECT  0 33.552 0.084 33.576 ;
    END
  END o[42]
  PIN o[430]
    DIRECTION OUTPUT ;
    USE SIGNAL ;
    PORT
      LAYER M4 ;
        RECT  0 59.28 0.084 59.304 ;
    END
  END o[430]
  PIN o[431]
    DIRECTION OUTPUT ;
    USE SIGNAL ;
    PORT
      LAYER M4 ;
        RECT  0 59.376 0.084 59.4 ;
    END
  END o[431]
  PIN o[432]
    DIRECTION OUTPUT ;
    USE SIGNAL ;
    PORT
      LAYER M4 ;
        RECT  0 59.472 0.084 59.496 ;
    END
  END o[432]
  PIN o[433]
    DIRECTION OUTPUT ;
    USE SIGNAL ;
    PORT
      LAYER M4 ;
        RECT  0 59.568 0.084 59.592 ;
    END
  END o[433]
  PIN o[434]
    DIRECTION OUTPUT ;
    USE SIGNAL ;
    PORT
      LAYER M4 ;
        RECT  0 59.664 0.084 59.688 ;
    END
  END o[434]
  PIN o[435]
    DIRECTION OUTPUT ;
    USE SIGNAL ;
    PORT
      LAYER M4 ;
        RECT  0 59.76 0.084 59.784 ;
    END
  END o[435]
  PIN o[436]
    DIRECTION OUTPUT ;
    USE SIGNAL ;
    PORT
      LAYER M4 ;
        RECT  0 59.856 0.084 59.88 ;
    END
  END o[436]
  PIN o[437]
    DIRECTION OUTPUT ;
    USE SIGNAL ;
    PORT
      LAYER M4 ;
        RECT  0 59.952 0.084 59.976 ;
    END
  END o[437]
  PIN o[438]
    DIRECTION OUTPUT ;
    USE SIGNAL ;
    PORT
      LAYER M4 ;
        RECT  0 60.048 0.084 60.072 ;
    END
  END o[438]
  PIN o[439]
    DIRECTION OUTPUT ;
    USE SIGNAL ;
    PORT
      LAYER M4 ;
        RECT  0 60.144 0.084 60.168 ;
    END
  END o[439]
  PIN o[43]
    DIRECTION OUTPUT ;
    USE SIGNAL ;
    PORT
      LAYER M4 ;
        RECT  0 33.648 0.084 33.672 ;
    END
  END o[43]
  PIN o[440]
    DIRECTION OUTPUT ;
    USE SIGNAL ;
    PORT
      LAYER M4 ;
        RECT  0 60.24 0.084 60.264 ;
    END
  END o[440]
  PIN o[441]
    DIRECTION OUTPUT ;
    USE SIGNAL ;
    PORT
      LAYER M4 ;
        RECT  0 60.336 0.084 60.36 ;
    END
  END o[441]
  PIN o[442]
    DIRECTION OUTPUT ;
    USE SIGNAL ;
    PORT
      LAYER M4 ;
        RECT  0 60.432 0.084 60.456 ;
    END
  END o[442]
  PIN o[443]
    DIRECTION OUTPUT ;
    USE SIGNAL ;
    PORT
      LAYER M4 ;
        RECT  0 60.528 0.084 60.552 ;
    END
  END o[443]
  PIN o[444]
    DIRECTION OUTPUT ;
    USE SIGNAL ;
    PORT
      LAYER M4 ;
        RECT  0 60.624 0.084 60.648 ;
    END
  END o[444]
  PIN o[445]
    DIRECTION OUTPUT ;
    USE SIGNAL ;
    PORT
      LAYER M4 ;
        RECT  0 60.72 0.084 60.744 ;
    END
  END o[445]
  PIN o[446]
    DIRECTION OUTPUT ;
    USE SIGNAL ;
    PORT
      LAYER M4 ;
        RECT  0 60.816 0.084 60.84 ;
    END
  END o[446]
  PIN o[447]
    DIRECTION OUTPUT ;
    USE SIGNAL ;
    PORT
      LAYER M4 ;
        RECT  0 60.912 0.084 60.936 ;
    END
  END o[447]
  PIN o[448]
    DIRECTION OUTPUT ;
    USE SIGNAL ;
    PORT
      LAYER M4 ;
        RECT  0 19.536 0.084 19.56 ;
    END
  END o[448]
  PIN o[449]
    DIRECTION OUTPUT ;
    USE SIGNAL ;
    PORT
      LAYER M4 ;
        RECT  0 19.632 0.084 19.656 ;
    END
  END o[449]
  PIN o[44]
    DIRECTION OUTPUT ;
    USE SIGNAL ;
    PORT
      LAYER M4 ;
        RECT  0 33.744 0.084 33.768 ;
    END
  END o[44]
  PIN o[450]
    DIRECTION OUTPUT ;
    USE SIGNAL ;
    PORT
      LAYER M4 ;
        RECT  0 19.728 0.084 19.752 ;
    END
  END o[450]
  PIN o[451]
    DIRECTION OUTPUT ;
    USE SIGNAL ;
    PORT
      LAYER M4 ;
        RECT  0 19.824 0.084 19.848 ;
    END
  END o[451]
  PIN o[452]
    DIRECTION OUTPUT ;
    USE SIGNAL ;
    PORT
      LAYER M4 ;
        RECT  0 19.92 0.084 19.944 ;
    END
  END o[452]
  PIN o[453]
    DIRECTION OUTPUT ;
    USE SIGNAL ;
    PORT
      LAYER M4 ;
        RECT  0 20.016 0.084 20.04 ;
    END
  END o[453]
  PIN o[454]
    DIRECTION OUTPUT ;
    USE SIGNAL ;
    PORT
      LAYER M4 ;
        RECT  0 20.112 0.084 20.136 ;
    END
  END o[454]
  PIN o[455]
    DIRECTION OUTPUT ;
    USE SIGNAL ;
    PORT
      LAYER M4 ;
        RECT  0 20.208 0.084 20.232 ;
    END
  END o[455]
  PIN o[456]
    DIRECTION OUTPUT ;
    USE SIGNAL ;
    PORT
      LAYER M4 ;
        RECT  0 20.304 0.084 20.328 ;
    END
  END o[456]
  PIN o[457]
    DIRECTION OUTPUT ;
    USE SIGNAL ;
    PORT
      LAYER M4 ;
        RECT  0 20.4 0.084 20.424 ;
    END
  END o[457]
  PIN o[458]
    DIRECTION OUTPUT ;
    USE SIGNAL ;
    PORT
      LAYER M4 ;
        RECT  0 20.496 0.084 20.52 ;
    END
  END o[458]
  PIN o[459]
    DIRECTION OUTPUT ;
    USE SIGNAL ;
    PORT
      LAYER M4 ;
        RECT  0 20.592 0.084 20.616 ;
    END
  END o[459]
  PIN o[45]
    DIRECTION OUTPUT ;
    USE SIGNAL ;
    PORT
      LAYER M4 ;
        RECT  0 33.84 0.084 33.864 ;
    END
  END o[45]
  PIN o[460]
    DIRECTION OUTPUT ;
    USE SIGNAL ;
    PORT
      LAYER M4 ;
        RECT  0 20.688 0.084 20.712 ;
    END
  END o[460]
  PIN o[461]
    DIRECTION OUTPUT ;
    USE SIGNAL ;
    PORT
      LAYER M4 ;
        RECT  0 20.784 0.084 20.808 ;
    END
  END o[461]
  PIN o[462]
    DIRECTION OUTPUT ;
    USE SIGNAL ;
    PORT
      LAYER M4 ;
        RECT  0 20.88 0.084 20.904 ;
    END
  END o[462]
  PIN o[463]
    DIRECTION OUTPUT ;
    USE SIGNAL ;
    PORT
      LAYER M4 ;
        RECT  0 20.976 0.084 21 ;
    END
  END o[463]
  PIN o[464]
    DIRECTION OUTPUT ;
    USE SIGNAL ;
    PORT
      LAYER M4 ;
        RECT  0 21.072 0.084 21.096 ;
    END
  END o[464]
  PIN o[465]
    DIRECTION OUTPUT ;
    USE SIGNAL ;
    PORT
      LAYER M4 ;
        RECT  0 21.168 0.084 21.192 ;
    END
  END o[465]
  PIN o[466]
    DIRECTION OUTPUT ;
    USE SIGNAL ;
    PORT
      LAYER M4 ;
        RECT  0 21.264 0.084 21.288 ;
    END
  END o[466]
  PIN o[467]
    DIRECTION OUTPUT ;
    USE SIGNAL ;
    PORT
      LAYER M4 ;
        RECT  0 21.36 0.084 21.384 ;
    END
  END o[467]
  PIN o[468]
    DIRECTION OUTPUT ;
    USE SIGNAL ;
    PORT
      LAYER M4 ;
        RECT  0 21.456 0.084 21.48 ;
    END
  END o[468]
  PIN o[469]
    DIRECTION OUTPUT ;
    USE SIGNAL ;
    PORT
      LAYER M4 ;
        RECT  0 21.552 0.084 21.576 ;
    END
  END o[469]
  PIN o[46]
    DIRECTION OUTPUT ;
    USE SIGNAL ;
    PORT
      LAYER M4 ;
        RECT  0 33.936 0.084 33.96 ;
    END
  END o[46]
  PIN o[470]
    DIRECTION OUTPUT ;
    USE SIGNAL ;
    PORT
      LAYER M4 ;
        RECT  0 21.648 0.084 21.672 ;
    END
  END o[470]
  PIN o[471]
    DIRECTION OUTPUT ;
    USE SIGNAL ;
    PORT
      LAYER M4 ;
        RECT  0 21.744 0.084 21.768 ;
    END
  END o[471]
  PIN o[472]
    DIRECTION OUTPUT ;
    USE SIGNAL ;
    PORT
      LAYER M4 ;
        RECT  0 21.84 0.084 21.864 ;
    END
  END o[472]
  PIN o[473]
    DIRECTION OUTPUT ;
    USE SIGNAL ;
    PORT
      LAYER M4 ;
        RECT  0 21.936 0.084 21.96 ;
    END
  END o[473]
  PIN o[474]
    DIRECTION OUTPUT ;
    USE SIGNAL ;
    PORT
      LAYER M4 ;
        RECT  0 22.032 0.084 22.056 ;
    END
  END o[474]
  PIN o[475]
    DIRECTION OUTPUT ;
    USE SIGNAL ;
    PORT
      LAYER M4 ;
        RECT  0 22.128 0.084 22.152 ;
    END
  END o[475]
  PIN o[476]
    DIRECTION OUTPUT ;
    USE SIGNAL ;
    PORT
      LAYER M4 ;
        RECT  0 22.224 0.084 22.248 ;
    END
  END o[476]
  PIN o[477]
    DIRECTION OUTPUT ;
    USE SIGNAL ;
    PORT
      LAYER M4 ;
        RECT  0 22.32 0.084 22.344 ;
    END
  END o[477]
  PIN o[478]
    DIRECTION OUTPUT ;
    USE SIGNAL ;
    PORT
      LAYER M4 ;
        RECT  0 22.416 0.084 22.44 ;
    END
  END o[478]
  PIN o[479]
    DIRECTION OUTPUT ;
    USE SIGNAL ;
    PORT
      LAYER M4 ;
        RECT  0 22.512 0.084 22.536 ;
    END
  END o[479]
  PIN o[47]
    DIRECTION OUTPUT ;
    USE SIGNAL ;
    PORT
      LAYER M4 ;
        RECT  0 34.032 0.084 34.056 ;
    END
  END o[47]
  PIN o[480]
    DIRECTION OUTPUT ;
    USE SIGNAL ;
    PORT
      LAYER M4 ;
        RECT  0 22.608 0.084 22.632 ;
    END
  END o[480]
  PIN o[481]
    DIRECTION OUTPUT ;
    USE SIGNAL ;
    PORT
      LAYER M4 ;
        RECT  0 22.704 0.084 22.728 ;
    END
  END o[481]
  PIN o[482]
    DIRECTION OUTPUT ;
    USE SIGNAL ;
    PORT
      LAYER M4 ;
        RECT  0 22.8 0.084 22.824 ;
    END
  END o[482]
  PIN o[483]
    DIRECTION OUTPUT ;
    USE SIGNAL ;
    PORT
      LAYER M4 ;
        RECT  0 22.896 0.084 22.92 ;
    END
  END o[483]
  PIN o[484]
    DIRECTION OUTPUT ;
    USE SIGNAL ;
    PORT
      LAYER M4 ;
        RECT  0 22.992 0.084 23.016 ;
    END
  END o[484]
  PIN o[485]
    DIRECTION OUTPUT ;
    USE SIGNAL ;
    PORT
      LAYER M4 ;
        RECT  0 23.088 0.084 23.112 ;
    END
  END o[485]
  PIN o[486]
    DIRECTION OUTPUT ;
    USE SIGNAL ;
    PORT
      LAYER M4 ;
        RECT  0 23.184 0.084 23.208 ;
    END
  END o[486]
  PIN o[487]
    DIRECTION OUTPUT ;
    USE SIGNAL ;
    PORT
      LAYER M4 ;
        RECT  0 23.28 0.084 23.304 ;
    END
  END o[487]
  PIN o[488]
    DIRECTION OUTPUT ;
    USE SIGNAL ;
    PORT
      LAYER M4 ;
        RECT  0 23.376 0.084 23.4 ;
    END
  END o[488]
  PIN o[489]
    DIRECTION OUTPUT ;
    USE SIGNAL ;
    PORT
      LAYER M4 ;
        RECT  0 23.472 0.084 23.496 ;
    END
  END o[489]
  PIN o[48]
    DIRECTION OUTPUT ;
    USE SIGNAL ;
    PORT
      LAYER M4 ;
        RECT  0 34.128 0.084 34.152 ;
    END
  END o[48]
  PIN o[490]
    DIRECTION OUTPUT ;
    USE SIGNAL ;
    PORT
      LAYER M4 ;
        RECT  0 23.568 0.084 23.592 ;
    END
  END o[490]
  PIN o[491]
    DIRECTION OUTPUT ;
    USE SIGNAL ;
    PORT
      LAYER M4 ;
        RECT  0 23.664 0.084 23.688 ;
    END
  END o[491]
  PIN o[492]
    DIRECTION OUTPUT ;
    USE SIGNAL ;
    PORT
      LAYER M4 ;
        RECT  0 23.76 0.084 23.784 ;
    END
  END o[492]
  PIN o[493]
    DIRECTION OUTPUT ;
    USE SIGNAL ;
    PORT
      LAYER M4 ;
        RECT  0 23.856 0.084 23.88 ;
    END
  END o[493]
  PIN o[494]
    DIRECTION OUTPUT ;
    USE SIGNAL ;
    PORT
      LAYER M4 ;
        RECT  0 23.952 0.084 23.976 ;
    END
  END o[494]
  PIN o[495]
    DIRECTION OUTPUT ;
    USE SIGNAL ;
    PORT
      LAYER M4 ;
        RECT  0 24.048 0.084 24.072 ;
    END
  END o[495]
  PIN o[496]
    DIRECTION OUTPUT ;
    USE SIGNAL ;
    PORT
      LAYER M4 ;
        RECT  0 24.144 0.084 24.168 ;
    END
  END o[496]
  PIN o[497]
    DIRECTION OUTPUT ;
    USE SIGNAL ;
    PORT
      LAYER M4 ;
        RECT  0 24.24 0.084 24.264 ;
    END
  END o[497]
  PIN o[498]
    DIRECTION OUTPUT ;
    USE SIGNAL ;
    PORT
      LAYER M4 ;
        RECT  0 24.336 0.084 24.36 ;
    END
  END o[498]
  PIN o[499]
    DIRECTION OUTPUT ;
    USE SIGNAL ;
    PORT
      LAYER M4 ;
        RECT  0 24.432 0.084 24.456 ;
    END
  END o[499]
  PIN o[49]
    DIRECTION OUTPUT ;
    USE SIGNAL ;
    PORT
      LAYER M4 ;
        RECT  0 34.224 0.084 34.248 ;
    END
  END o[49]
  PIN o[4]
    DIRECTION OUTPUT ;
    USE SIGNAL ;
    PORT
      LAYER M4 ;
        RECT  0 42.192 0.084 42.216 ;
    END
  END o[4]
  PIN o[500]
    DIRECTION OUTPUT ;
    USE SIGNAL ;
    PORT
      LAYER M4 ;
        RECT  0 24.528 0.084 24.552 ;
    END
  END o[500]
  PIN o[501]
    DIRECTION OUTPUT ;
    USE SIGNAL ;
    PORT
      LAYER M4 ;
        RECT  0 24.624 0.084 24.648 ;
    END
  END o[501]
  PIN o[502]
    DIRECTION OUTPUT ;
    USE SIGNAL ;
    PORT
      LAYER M4 ;
        RECT  0 24.72 0.084 24.744 ;
    END
  END o[502]
  PIN o[503]
    DIRECTION OUTPUT ;
    USE SIGNAL ;
    PORT
      LAYER M4 ;
        RECT  0 24.816 0.084 24.84 ;
    END
  END o[503]
  PIN o[504]
    DIRECTION OUTPUT ;
    USE SIGNAL ;
    PORT
      LAYER M4 ;
        RECT  0 24.912 0.084 24.936 ;
    END
  END o[504]
  PIN o[505]
    DIRECTION OUTPUT ;
    USE SIGNAL ;
    PORT
      LAYER M4 ;
        RECT  0 25.008 0.084 25.032 ;
    END
  END o[505]
  PIN o[506]
    DIRECTION OUTPUT ;
    USE SIGNAL ;
    PORT
      LAYER M4 ;
        RECT  0 25.104 0.084 25.128 ;
    END
  END o[506]
  PIN o[507]
    DIRECTION OUTPUT ;
    USE SIGNAL ;
    PORT
      LAYER M4 ;
        RECT  0 25.2 0.084 25.224 ;
    END
  END o[507]
  PIN o[508]
    DIRECTION OUTPUT ;
    USE SIGNAL ;
    PORT
      LAYER M4 ;
        RECT  0 25.296 0.084 25.32 ;
    END
  END o[508]
  PIN o[509]
    DIRECTION OUTPUT ;
    USE SIGNAL ;
    PORT
      LAYER M4 ;
        RECT  0 25.392 0.084 25.416 ;
    END
  END o[509]
  PIN o[50]
    DIRECTION OUTPUT ;
    USE SIGNAL ;
    PORT
      LAYER M4 ;
        RECT  0 34.32 0.084 34.344 ;
    END
  END o[50]
  PIN o[510]
    DIRECTION OUTPUT ;
    USE SIGNAL ;
    PORT
      LAYER M4 ;
        RECT  0 25.488 0.084 25.512 ;
    END
  END o[510]
  PIN o[511]
    DIRECTION OUTPUT ;
    USE SIGNAL ;
    PORT
      LAYER M4 ;
        RECT  0 25.584 0.084 25.608 ;
    END
  END o[511]
  PIN o[512]
    DIRECTION OUTPUT ;
    USE SIGNAL ;
    PORT
      LAYER M4 ;
        RECT  0 16.464 0.084 16.488 ;
    END
  END o[512]
  PIN o[513]
    DIRECTION OUTPUT ;
    USE SIGNAL ;
    PORT
      LAYER M4 ;
        RECT  0 16.56 0.084 16.584 ;
    END
  END o[513]
  PIN o[514]
    DIRECTION OUTPUT ;
    USE SIGNAL ;
    PORT
      LAYER M4 ;
        RECT  0 16.656 0.084 16.68 ;
    END
  END o[514]
  PIN o[515]
    DIRECTION OUTPUT ;
    USE SIGNAL ;
    PORT
      LAYER M4 ;
        RECT  0 16.752 0.084 16.776 ;
    END
  END o[515]
  PIN o[516]
    DIRECTION OUTPUT ;
    USE SIGNAL ;
    PORT
      LAYER M4 ;
        RECT  0 16.848 0.084 16.872 ;
    END
  END o[516]
  PIN o[517]
    DIRECTION OUTPUT ;
    USE SIGNAL ;
    PORT
      LAYER M4 ;
        RECT  0 16.944 0.084 16.968 ;
    END
  END o[517]
  PIN o[518]
    DIRECTION OUTPUT ;
    USE SIGNAL ;
    PORT
      LAYER M4 ;
        RECT  0 17.04 0.084 17.064 ;
    END
  END o[518]
  PIN o[519]
    DIRECTION OUTPUT ;
    USE SIGNAL ;
    PORT
      LAYER M4 ;
        RECT  0 17.136 0.084 17.16 ;
    END
  END o[519]
  PIN o[51]
    DIRECTION OUTPUT ;
    USE SIGNAL ;
    PORT
      LAYER M4 ;
        RECT  0 34.416 0.084 34.44 ;
    END
  END o[51]
  PIN o[520]
    DIRECTION OUTPUT ;
    USE SIGNAL ;
    PORT
      LAYER M4 ;
        RECT  0 17.232 0.084 17.256 ;
    END
  END o[520]
  PIN o[521]
    DIRECTION OUTPUT ;
    USE SIGNAL ;
    PORT
      LAYER M4 ;
        RECT  0 17.328 0.084 17.352 ;
    END
  END o[521]
  PIN o[522]
    DIRECTION OUTPUT ;
    USE SIGNAL ;
    PORT
      LAYER M4 ;
        RECT  0 17.424 0.084 17.448 ;
    END
  END o[522]
  PIN o[523]
    DIRECTION OUTPUT ;
    USE SIGNAL ;
    PORT
      LAYER M4 ;
        RECT  0 17.52 0.084 17.544 ;
    END
  END o[523]
  PIN o[524]
    DIRECTION OUTPUT ;
    USE SIGNAL ;
    PORT
      LAYER M4 ;
        RECT  0 17.616 0.084 17.64 ;
    END
  END o[524]
  PIN o[525]
    DIRECTION OUTPUT ;
    USE SIGNAL ;
    PORT
      LAYER M4 ;
        RECT  0 17.712 0.084 17.736 ;
    END
  END o[525]
  PIN o[526]
    DIRECTION OUTPUT ;
    USE SIGNAL ;
    PORT
      LAYER M4 ;
        RECT  0 17.808 0.084 17.832 ;
    END
  END o[526]
  PIN o[527]
    DIRECTION OUTPUT ;
    USE SIGNAL ;
    PORT
      LAYER M4 ;
        RECT  0 17.904 0.084 17.928 ;
    END
  END o[527]
  PIN o[528]
    DIRECTION OUTPUT ;
    USE SIGNAL ;
    PORT
      LAYER M4 ;
        RECT  0 18 0.084 18.024 ;
    END
  END o[528]
  PIN o[529]
    DIRECTION OUTPUT ;
    USE SIGNAL ;
    PORT
      LAYER M4 ;
        RECT  0 18.096 0.084 18.12 ;
    END
  END o[529]
  PIN o[52]
    DIRECTION OUTPUT ;
    USE SIGNAL ;
    PORT
      LAYER M4 ;
        RECT  0 34.512 0.084 34.536 ;
    END
  END o[52]
  PIN o[530]
    DIRECTION OUTPUT ;
    USE SIGNAL ;
    PORT
      LAYER M4 ;
        RECT  0 18.192 0.084 18.216 ;
    END
  END o[530]
  PIN o[531]
    DIRECTION OUTPUT ;
    USE SIGNAL ;
    PORT
      LAYER M4 ;
        RECT  0 18.288 0.084 18.312 ;
    END
  END o[531]
  PIN o[532]
    DIRECTION OUTPUT ;
    USE SIGNAL ;
    PORT
      LAYER M4 ;
        RECT  0 18.384 0.084 18.408 ;
    END
  END o[532]
  PIN o[533]
    DIRECTION OUTPUT ;
    USE SIGNAL ;
    PORT
      LAYER M4 ;
        RECT  0 18.48 0.084 18.504 ;
    END
  END o[533]
  PIN o[534]
    DIRECTION OUTPUT ;
    USE SIGNAL ;
    PORT
      LAYER M4 ;
        RECT  0 18.576 0.084 18.6 ;
    END
  END o[534]
  PIN o[535]
    DIRECTION OUTPUT ;
    USE SIGNAL ;
    PORT
      LAYER M4 ;
        RECT  0 18.672 0.084 18.696 ;
    END
  END o[535]
  PIN o[536]
    DIRECTION OUTPUT ;
    USE SIGNAL ;
    PORT
      LAYER M4 ;
        RECT  0 18.768 0.084 18.792 ;
    END
  END o[536]
  PIN o[537]
    DIRECTION OUTPUT ;
    USE SIGNAL ;
    PORT
      LAYER M4 ;
        RECT  0 18.864 0.084 18.888 ;
    END
  END o[537]
  PIN o[538]
    DIRECTION OUTPUT ;
    USE SIGNAL ;
    PORT
      LAYER M4 ;
        RECT  0 18.96 0.084 18.984 ;
    END
  END o[538]
  PIN o[539]
    DIRECTION OUTPUT ;
    USE SIGNAL ;
    PORT
      LAYER M4 ;
        RECT  0 19.056 0.084 19.08 ;
    END
  END o[539]
  PIN o[53]
    DIRECTION OUTPUT ;
    USE SIGNAL ;
    PORT
      LAYER M4 ;
        RECT  0 34.608 0.084 34.632 ;
    END
  END o[53]
  PIN o[540]
    DIRECTION OUTPUT ;
    USE SIGNAL ;
    PORT
      LAYER M4 ;
        RECT  0 19.152 0.084 19.176 ;
    END
  END o[540]
  PIN o[541]
    DIRECTION OUTPUT ;
    USE SIGNAL ;
    PORT
      LAYER M4 ;
        RECT  0 19.248 0.084 19.272 ;
    END
  END o[541]
  PIN o[542]
    DIRECTION OUTPUT ;
    USE SIGNAL ;
    PORT
      LAYER M4 ;
        RECT  0 19.344 0.084 19.368 ;
    END
  END o[542]
  PIN o[543]
    DIRECTION OUTPUT ;
    USE SIGNAL ;
    PORT
      LAYER M4 ;
        RECT  0 19.44 0.084 19.464 ;
    END
  END o[543]
  PIN o[544]
    DIRECTION OUTPUT ;
    USE SIGNAL ;
    PORT
      LAYER M4 ;
        RECT  0 7.248 0.084 7.272 ;
    END
  END o[544]
  PIN o[545]
    DIRECTION OUTPUT ;
    USE SIGNAL ;
    PORT
      LAYER M4 ;
        RECT  0 7.344 0.084 7.368 ;
    END
  END o[545]
  PIN o[546]
    DIRECTION OUTPUT ;
    USE SIGNAL ;
    PORT
      LAYER M4 ;
        RECT  0 7.44 0.084 7.464 ;
    END
  END o[546]
  PIN o[547]
    DIRECTION OUTPUT ;
    USE SIGNAL ;
    PORT
      LAYER M4 ;
        RECT  0 7.536 0.084 7.56 ;
    END
  END o[547]
  PIN o[548]
    DIRECTION OUTPUT ;
    USE SIGNAL ;
    PORT
      LAYER M4 ;
        RECT  0 7.632 0.084 7.656 ;
    END
  END o[548]
  PIN o[549]
    DIRECTION OUTPUT ;
    USE SIGNAL ;
    PORT
      LAYER M4 ;
        RECT  0 7.728 0.084 7.752 ;
    END
  END o[549]
  PIN o[54]
    DIRECTION OUTPUT ;
    USE SIGNAL ;
    PORT
      LAYER M4 ;
        RECT  0 34.704 0.084 34.728 ;
    END
  END o[54]
  PIN o[550]
    DIRECTION OUTPUT ;
    USE SIGNAL ;
    PORT
      LAYER M4 ;
        RECT  0 7.824 0.084 7.848 ;
    END
  END o[550]
  PIN o[551]
    DIRECTION OUTPUT ;
    USE SIGNAL ;
    PORT
      LAYER M4 ;
        RECT  0 7.92 0.084 7.944 ;
    END
  END o[551]
  PIN o[552]
    DIRECTION OUTPUT ;
    USE SIGNAL ;
    PORT
      LAYER M4 ;
        RECT  0 8.016 0.084 8.04 ;
    END
  END o[552]
  PIN o[553]
    DIRECTION OUTPUT ;
    USE SIGNAL ;
    PORT
      LAYER M4 ;
        RECT  0 8.112 0.084 8.136 ;
    END
  END o[553]
  PIN o[554]
    DIRECTION OUTPUT ;
    USE SIGNAL ;
    PORT
      LAYER M4 ;
        RECT  0 8.208 0.084 8.232 ;
    END
  END o[554]
  PIN o[555]
    DIRECTION OUTPUT ;
    USE SIGNAL ;
    PORT
      LAYER M4 ;
        RECT  0 8.304 0.084 8.328 ;
    END
  END o[555]
  PIN o[556]
    DIRECTION OUTPUT ;
    USE SIGNAL ;
    PORT
      LAYER M4 ;
        RECT  0 8.4 0.084 8.424 ;
    END
  END o[556]
  PIN o[557]
    DIRECTION OUTPUT ;
    USE SIGNAL ;
    PORT
      LAYER M4 ;
        RECT  0 8.496 0.084 8.52 ;
    END
  END o[557]
  PIN o[558]
    DIRECTION OUTPUT ;
    USE SIGNAL ;
    PORT
      LAYER M4 ;
        RECT  0 8.592 0.084 8.616 ;
    END
  END o[558]
  PIN o[559]
    DIRECTION OUTPUT ;
    USE SIGNAL ;
    PORT
      LAYER M4 ;
        RECT  0 8.688 0.084 8.712 ;
    END
  END o[559]
  PIN o[55]
    DIRECTION OUTPUT ;
    USE SIGNAL ;
    PORT
      LAYER M4 ;
        RECT  0 34.8 0.084 34.824 ;
    END
  END o[55]
  PIN o[560]
    DIRECTION OUTPUT ;
    USE SIGNAL ;
    PORT
      LAYER M4 ;
        RECT  0 8.784 0.084 8.808 ;
    END
  END o[560]
  PIN o[561]
    DIRECTION OUTPUT ;
    USE SIGNAL ;
    PORT
      LAYER M4 ;
        RECT  0 8.88 0.084 8.904 ;
    END
  END o[561]
  PIN o[562]
    DIRECTION OUTPUT ;
    USE SIGNAL ;
    PORT
      LAYER M4 ;
        RECT  0 8.976 0.084 9 ;
    END
  END o[562]
  PIN o[563]
    DIRECTION OUTPUT ;
    USE SIGNAL ;
    PORT
      LAYER M4 ;
        RECT  0 9.072 0.084 9.096 ;
    END
  END o[563]
  PIN o[564]
    DIRECTION OUTPUT ;
    USE SIGNAL ;
    PORT
      LAYER M4 ;
        RECT  0 9.168 0.084 9.192 ;
    END
  END o[564]
  PIN o[565]
    DIRECTION OUTPUT ;
    USE SIGNAL ;
    PORT
      LAYER M4 ;
        RECT  0 9.264 0.084 9.288 ;
    END
  END o[565]
  PIN o[566]
    DIRECTION OUTPUT ;
    USE SIGNAL ;
    PORT
      LAYER M4 ;
        RECT  0 9.36 0.084 9.384 ;
    END
  END o[566]
  PIN o[567]
    DIRECTION OUTPUT ;
    USE SIGNAL ;
    PORT
      LAYER M4 ;
        RECT  0 9.456 0.084 9.48 ;
    END
  END o[567]
  PIN o[568]
    DIRECTION OUTPUT ;
    USE SIGNAL ;
    PORT
      LAYER M4 ;
        RECT  0 9.552 0.084 9.576 ;
    END
  END o[568]
  PIN o[569]
    DIRECTION OUTPUT ;
    USE SIGNAL ;
    PORT
      LAYER M4 ;
        RECT  0 9.648 0.084 9.672 ;
    END
  END o[569]
  PIN o[56]
    DIRECTION OUTPUT ;
    USE SIGNAL ;
    PORT
      LAYER M4 ;
        RECT  0 34.896 0.084 34.92 ;
    END
  END o[56]
  PIN o[570]
    DIRECTION OUTPUT ;
    USE SIGNAL ;
    PORT
      LAYER M4 ;
        RECT  0 9.744 0.084 9.768 ;
    END
  END o[570]
  PIN o[571]
    DIRECTION OUTPUT ;
    USE SIGNAL ;
    PORT
      LAYER M4 ;
        RECT  0 9.84 0.084 9.864 ;
    END
  END o[571]
  PIN o[572]
    DIRECTION OUTPUT ;
    USE SIGNAL ;
    PORT
      LAYER M4 ;
        RECT  0 9.936 0.084 9.96 ;
    END
  END o[572]
  PIN o[573]
    DIRECTION OUTPUT ;
    USE SIGNAL ;
    PORT
      LAYER M4 ;
        RECT  0 10.032 0.084 10.056 ;
    END
  END o[573]
  PIN o[574]
    DIRECTION OUTPUT ;
    USE SIGNAL ;
    PORT
      LAYER M4 ;
        RECT  0 10.128 0.084 10.152 ;
    END
  END o[574]
  PIN o[575]
    DIRECTION OUTPUT ;
    USE SIGNAL ;
    PORT
      LAYER M4 ;
        RECT  0 10.224 0.084 10.248 ;
    END
  END o[575]
  PIN o[576]
    DIRECTION OUTPUT ;
    USE SIGNAL ;
    PORT
      LAYER M4 ;
        RECT  0 3.408 0.084 3.432 ;
    END
  END o[576]
  PIN o[577]
    DIRECTION OUTPUT ;
    USE SIGNAL ;
    PORT
      LAYER M4 ;
        RECT  0 3.504 0.084 3.528 ;
    END
  END o[577]
  PIN o[578]
    DIRECTION OUTPUT ;
    USE SIGNAL ;
    PORT
      LAYER M4 ;
        RECT  0 3.6 0.084 3.624 ;
    END
  END o[578]
  PIN o[579]
    DIRECTION OUTPUT ;
    USE SIGNAL ;
    PORT
      LAYER M4 ;
        RECT  0 3.696 0.084 3.72 ;
    END
  END o[579]
  PIN o[57]
    DIRECTION OUTPUT ;
    USE SIGNAL ;
    PORT
      LAYER M4 ;
        RECT  0 34.992 0.084 35.016 ;
    END
  END o[57]
  PIN o[580]
    DIRECTION OUTPUT ;
    USE SIGNAL ;
    PORT
      LAYER M4 ;
        RECT  0 3.792 0.084 3.816 ;
    END
  END o[580]
  PIN o[581]
    DIRECTION OUTPUT ;
    USE SIGNAL ;
    PORT
      LAYER M4 ;
        RECT  0 3.888 0.084 3.912 ;
    END
  END o[581]
  PIN o[582]
    DIRECTION OUTPUT ;
    USE SIGNAL ;
    PORT
      LAYER M4 ;
        RECT  0 3.984 0.084 4.008 ;
    END
  END o[582]
  PIN o[583]
    DIRECTION OUTPUT ;
    USE SIGNAL ;
    PORT
      LAYER M4 ;
        RECT  0 4.08 0.084 4.104 ;
    END
  END o[583]
  PIN o[584]
    DIRECTION OUTPUT ;
    USE SIGNAL ;
    PORT
      LAYER M4 ;
        RECT  0 4.176 0.084 4.2 ;
    END
  END o[584]
  PIN o[585]
    DIRECTION OUTPUT ;
    USE SIGNAL ;
    PORT
      LAYER M4 ;
        RECT  0 4.272 0.084 4.296 ;
    END
  END o[585]
  PIN o[586]
    DIRECTION OUTPUT ;
    USE SIGNAL ;
    PORT
      LAYER M4 ;
        RECT  0 4.368 0.084 4.392 ;
    END
  END o[586]
  PIN o[587]
    DIRECTION OUTPUT ;
    USE SIGNAL ;
    PORT
      LAYER M4 ;
        RECT  0 4.464 0.084 4.488 ;
    END
  END o[587]
  PIN o[588]
    DIRECTION OUTPUT ;
    USE SIGNAL ;
    PORT
      LAYER M4 ;
        RECT  0 4.56 0.084 4.584 ;
    END
  END o[588]
  PIN o[589]
    DIRECTION OUTPUT ;
    USE SIGNAL ;
    PORT
      LAYER M4 ;
        RECT  0 4.656 0.084 4.68 ;
    END
  END o[589]
  PIN o[58]
    DIRECTION OUTPUT ;
    USE SIGNAL ;
    PORT
      LAYER M4 ;
        RECT  0 35.088 0.084 35.112 ;
    END
  END o[58]
  PIN o[590]
    DIRECTION OUTPUT ;
    USE SIGNAL ;
    PORT
      LAYER M4 ;
        RECT  0 4.752 0.084 4.776 ;
    END
  END o[590]
  PIN o[591]
    DIRECTION OUTPUT ;
    USE SIGNAL ;
    PORT
      LAYER M4 ;
        RECT  0 4.848 0.084 4.872 ;
    END
  END o[591]
  PIN o[592]
    DIRECTION OUTPUT ;
    USE SIGNAL ;
    PORT
      LAYER M4 ;
        RECT  0 4.944 0.084 4.968 ;
    END
  END o[592]
  PIN o[593]
    DIRECTION OUTPUT ;
    USE SIGNAL ;
    PORT
      LAYER M4 ;
        RECT  0 5.04 0.084 5.064 ;
    END
  END o[593]
  PIN o[594]
    DIRECTION OUTPUT ;
    USE SIGNAL ;
    PORT
      LAYER M4 ;
        RECT  0 5.136 0.084 5.16 ;
    END
  END o[594]
  PIN o[595]
    DIRECTION OUTPUT ;
    USE SIGNAL ;
    PORT
      LAYER M4 ;
        RECT  0 5.232 0.084 5.256 ;
    END
  END o[595]
  PIN o[596]
    DIRECTION OUTPUT ;
    USE SIGNAL ;
    PORT
      LAYER M4 ;
        RECT  0 5.328 0.084 5.352 ;
    END
  END o[596]
  PIN o[597]
    DIRECTION OUTPUT ;
    USE SIGNAL ;
    PORT
      LAYER M4 ;
        RECT  0 5.424 0.084 5.448 ;
    END
  END o[597]
  PIN o[598]
    DIRECTION OUTPUT ;
    USE SIGNAL ;
    PORT
      LAYER M4 ;
        RECT  0 5.52 0.084 5.544 ;
    END
  END o[598]
  PIN o[599]
    DIRECTION OUTPUT ;
    USE SIGNAL ;
    PORT
      LAYER M4 ;
        RECT  0 5.616 0.084 5.64 ;
    END
  END o[599]
  PIN o[59]
    DIRECTION OUTPUT ;
    USE SIGNAL ;
    PORT
      LAYER M4 ;
        RECT  0 35.184 0.084 35.208 ;
    END
  END o[59]
  PIN o[5]
    DIRECTION OUTPUT ;
    USE SIGNAL ;
    PORT
      LAYER M4 ;
        RECT  0 42.288 0.084 42.312 ;
    END
  END o[5]
  PIN o[600]
    DIRECTION OUTPUT ;
    USE SIGNAL ;
    PORT
      LAYER M4 ;
        RECT  0 5.712 0.084 5.736 ;
    END
  END o[600]
  PIN o[601]
    DIRECTION OUTPUT ;
    USE SIGNAL ;
    PORT
      LAYER M4 ;
        RECT  0 5.808 0.084 5.832 ;
    END
  END o[601]
  PIN o[602]
    DIRECTION OUTPUT ;
    USE SIGNAL ;
    PORT
      LAYER M4 ;
        RECT  0 5.904 0.084 5.928 ;
    END
  END o[602]
  PIN o[603]
    DIRECTION OUTPUT ;
    USE SIGNAL ;
    PORT
      LAYER M4 ;
        RECT  0 6 0.084 6.024 ;
    END
  END o[603]
  PIN o[604]
    DIRECTION OUTPUT ;
    USE SIGNAL ;
    PORT
      LAYER M4 ;
        RECT  0 6.096 0.084 6.12 ;
    END
  END o[604]
  PIN o[605]
    DIRECTION OUTPUT ;
    USE SIGNAL ;
    PORT
      LAYER M4 ;
        RECT  0 6.192 0.084 6.216 ;
    END
  END o[605]
  PIN o[606]
    DIRECTION OUTPUT ;
    USE SIGNAL ;
    PORT
      LAYER M4 ;
        RECT  0 6.288 0.084 6.312 ;
    END
  END o[606]
  PIN o[607]
    DIRECTION OUTPUT ;
    USE SIGNAL ;
    PORT
      LAYER M4 ;
        RECT  0 6.384 0.084 6.408 ;
    END
  END o[607]
  PIN o[608]
    DIRECTION OUTPUT ;
    USE SIGNAL ;
    PORT
      LAYER M4 ;
        RECT  0 1.872 0.084 1.896 ;
    END
  END o[608]
  PIN o[609]
    DIRECTION OUTPUT ;
    USE SIGNAL ;
    PORT
      LAYER M4 ;
        RECT  0 1.968 0.084 1.992 ;
    END
  END o[609]
  PIN o[60]
    DIRECTION OUTPUT ;
    USE SIGNAL ;
    PORT
      LAYER M4 ;
        RECT  0 35.28 0.084 35.304 ;
    END
  END o[60]
  PIN o[610]
    DIRECTION OUTPUT ;
    USE SIGNAL ;
    PORT
      LAYER M4 ;
        RECT  0 2.064 0.084 2.088 ;
    END
  END o[610]
  PIN o[611]
    DIRECTION OUTPUT ;
    USE SIGNAL ;
    PORT
      LAYER M4 ;
        RECT  0 2.16 0.084 2.184 ;
    END
  END o[611]
  PIN o[612]
    DIRECTION OUTPUT ;
    USE SIGNAL ;
    PORT
      LAYER M4 ;
        RECT  0 2.256 0.084 2.28 ;
    END
  END o[612]
  PIN o[613]
    DIRECTION OUTPUT ;
    USE SIGNAL ;
    PORT
      LAYER M4 ;
        RECT  0 2.352 0.084 2.376 ;
    END
  END o[613]
  PIN o[614]
    DIRECTION OUTPUT ;
    USE SIGNAL ;
    PORT
      LAYER M4 ;
        RECT  0 2.448 0.084 2.472 ;
    END
  END o[614]
  PIN o[615]
    DIRECTION OUTPUT ;
    USE SIGNAL ;
    PORT
      LAYER M4 ;
        RECT  0 2.544 0.084 2.568 ;
    END
  END o[615]
  PIN o[616]
    DIRECTION OUTPUT ;
    USE SIGNAL ;
    PORT
      LAYER M4 ;
        RECT  0 2.64 0.084 2.664 ;
    END
  END o[616]
  PIN o[617]
    DIRECTION OUTPUT ;
    USE SIGNAL ;
    PORT
      LAYER M4 ;
        RECT  0 2.736 0.084 2.76 ;
    END
  END o[617]
  PIN o[618]
    DIRECTION OUTPUT ;
    USE SIGNAL ;
    PORT
      LAYER M4 ;
        RECT  0 2.832 0.084 2.856 ;
    END
  END o[618]
  PIN o[619]
    DIRECTION OUTPUT ;
    USE SIGNAL ;
    PORT
      LAYER M4 ;
        RECT  0 2.928 0.084 2.952 ;
    END
  END o[619]
  PIN o[61]
    DIRECTION OUTPUT ;
    USE SIGNAL ;
    PORT
      LAYER M4 ;
        RECT  0 35.376 0.084 35.4 ;
    END
  END o[61]
  PIN o[620]
    DIRECTION OUTPUT ;
    USE SIGNAL ;
    PORT
      LAYER M4 ;
        RECT  0 3.024 0.084 3.048 ;
    END
  END o[620]
  PIN o[621]
    DIRECTION OUTPUT ;
    USE SIGNAL ;
    PORT
      LAYER M4 ;
        RECT  0 3.12 0.084 3.144 ;
    END
  END o[621]
  PIN o[622]
    DIRECTION OUTPUT ;
    USE SIGNAL ;
    PORT
      LAYER M4 ;
        RECT  0 3.216 0.084 3.24 ;
    END
  END o[622]
  PIN o[623]
    DIRECTION OUTPUT ;
    USE SIGNAL ;
    PORT
      LAYER M4 ;
        RECT  0 3.312 0.084 3.336 ;
    END
  END o[623]
  PIN o[62]
    DIRECTION OUTPUT ;
    USE SIGNAL ;
    PORT
      LAYER M4 ;
        RECT  0 35.472 0.084 35.496 ;
    END
  END o[62]
  PIN o[63]
    DIRECTION OUTPUT ;
    USE SIGNAL ;
    PORT
      LAYER M4 ;
        RECT  0 35.568 0.084 35.592 ;
    END
  END o[63]
  PIN o[64]
    DIRECTION OUTPUT ;
    USE SIGNAL ;
    PORT
      LAYER M4 ;
        RECT  0 29.52 0.084 29.544 ;
    END
  END o[64]
  PIN o[65]
    DIRECTION OUTPUT ;
    USE SIGNAL ;
    PORT
      LAYER M4 ;
        RECT  0 29.616 0.084 29.64 ;
    END
  END o[65]
  PIN o[66]
    DIRECTION OUTPUT ;
    USE SIGNAL ;
    PORT
      LAYER M4 ;
        RECT  0 29.712 0.084 29.736 ;
    END
  END o[66]
  PIN o[67]
    DIRECTION OUTPUT ;
    USE SIGNAL ;
    PORT
      LAYER M4 ;
        RECT  0 29.808 0.084 29.832 ;
    END
  END o[67]
  PIN o[68]
    DIRECTION OUTPUT ;
    USE SIGNAL ;
    PORT
      LAYER M4 ;
        RECT  0 29.904 0.084 29.928 ;
    END
  END o[68]
  PIN o[69]
    DIRECTION OUTPUT ;
    USE SIGNAL ;
    PORT
      LAYER M4 ;
        RECT  0 30 0.084 30.024 ;
    END
  END o[69]
  PIN o[6]
    DIRECTION OUTPUT ;
    USE SIGNAL ;
    PORT
      LAYER M4 ;
        RECT  0 42.384 0.084 42.408 ;
    END
  END o[6]
  PIN o[70]
    DIRECTION OUTPUT ;
    USE SIGNAL ;
    PORT
      LAYER M4 ;
        RECT  0 30.096 0.084 30.12 ;
    END
  END o[70]
  PIN o[71]
    DIRECTION OUTPUT ;
    USE SIGNAL ;
    PORT
      LAYER M4 ;
        RECT  0 30.192 0.084 30.216 ;
    END
  END o[71]
  PIN o[72]
    DIRECTION OUTPUT ;
    USE SIGNAL ;
    PORT
      LAYER M4 ;
        RECT  0 30.288 0.084 30.312 ;
    END
  END o[72]
  PIN o[73]
    DIRECTION OUTPUT ;
    USE SIGNAL ;
    PORT
      LAYER M4 ;
        RECT  0 30.384 0.084 30.408 ;
    END
  END o[73]
  PIN o[74]
    DIRECTION OUTPUT ;
    USE SIGNAL ;
    PORT
      LAYER M4 ;
        RECT  0 30.48 0.084 30.504 ;
    END
  END o[74]
  PIN o[75]
    DIRECTION OUTPUT ;
    USE SIGNAL ;
    PORT
      LAYER M4 ;
        RECT  0 30.576 0.084 30.6 ;
    END
  END o[75]
  PIN o[76]
    DIRECTION OUTPUT ;
    USE SIGNAL ;
    PORT
      LAYER M4 ;
        RECT  0 30.672 0.084 30.696 ;
    END
  END o[76]
  PIN o[77]
    DIRECTION OUTPUT ;
    USE SIGNAL ;
    PORT
      LAYER M4 ;
        RECT  0 30.768 0.084 30.792 ;
    END
  END o[77]
  PIN o[78]
    DIRECTION OUTPUT ;
    USE SIGNAL ;
    PORT
      LAYER M4 ;
        RECT  0 30.864 0.084 30.888 ;
    END
  END o[78]
  PIN o[79]
    DIRECTION OUTPUT ;
    USE SIGNAL ;
    PORT
      LAYER M4 ;
        RECT  0 30.96 0.084 30.984 ;
    END
  END o[79]
  PIN o[7]
    DIRECTION OUTPUT ;
    USE SIGNAL ;
    PORT
      LAYER M4 ;
        RECT  0 42.48 0.084 42.504 ;
    END
  END o[7]
  PIN o[80]
    DIRECTION OUTPUT ;
    USE SIGNAL ;
    PORT
      LAYER M4 ;
        RECT  0 31.056 0.084 31.08 ;
    END
  END o[80]
  PIN o[81]
    DIRECTION OUTPUT ;
    USE SIGNAL ;
    PORT
      LAYER M4 ;
        RECT  0 31.152 0.084 31.176 ;
    END
  END o[81]
  PIN o[82]
    DIRECTION OUTPUT ;
    USE SIGNAL ;
    PORT
      LAYER M4 ;
        RECT  0 31.248 0.084 31.272 ;
    END
  END o[82]
  PIN o[83]
    DIRECTION OUTPUT ;
    USE SIGNAL ;
    PORT
      LAYER M4 ;
        RECT  0 31.344 0.084 31.368 ;
    END
  END o[83]
  PIN o[84]
    DIRECTION OUTPUT ;
    USE SIGNAL ;
    PORT
      LAYER M4 ;
        RECT  0 31.44 0.084 31.464 ;
    END
  END o[84]
  PIN o[85]
    DIRECTION OUTPUT ;
    USE SIGNAL ;
    PORT
      LAYER M4 ;
        RECT  0 31.536 0.084 31.56 ;
    END
  END o[85]
  PIN o[86]
    DIRECTION OUTPUT ;
    USE SIGNAL ;
    PORT
      LAYER M4 ;
        RECT  0 31.632 0.084 31.656 ;
    END
  END o[86]
  PIN o[87]
    DIRECTION OUTPUT ;
    USE SIGNAL ;
    PORT
      LAYER M4 ;
        RECT  0 31.728 0.084 31.752 ;
    END
  END o[87]
  PIN o[88]
    DIRECTION OUTPUT ;
    USE SIGNAL ;
    PORT
      LAYER M4 ;
        RECT  0 31.824 0.084 31.848 ;
    END
  END o[88]
  PIN o[89]
    DIRECTION OUTPUT ;
    USE SIGNAL ;
    PORT
      LAYER M4 ;
        RECT  0 31.92 0.084 31.944 ;
    END
  END o[89]
  PIN o[8]
    DIRECTION OUTPUT ;
    USE SIGNAL ;
    PORT
      LAYER M4 ;
        RECT  0 42.576 0.084 42.6 ;
    END
  END o[8]
  PIN o[90]
    DIRECTION OUTPUT ;
    USE SIGNAL ;
    PORT
      LAYER M4 ;
        RECT  0 32.016 0.084 32.04 ;
    END
  END o[90]
  PIN o[91]
    DIRECTION OUTPUT ;
    USE SIGNAL ;
    PORT
      LAYER M4 ;
        RECT  0 32.112 0.084 32.136 ;
    END
  END o[91]
  PIN o[92]
    DIRECTION OUTPUT ;
    USE SIGNAL ;
    PORT
      LAYER M4 ;
        RECT  0 32.208 0.084 32.232 ;
    END
  END o[92]
  PIN o[93]
    DIRECTION OUTPUT ;
    USE SIGNAL ;
    PORT
      LAYER M4 ;
        RECT  0 32.304 0.084 32.328 ;
    END
  END o[93]
  PIN o[94]
    DIRECTION OUTPUT ;
    USE SIGNAL ;
    PORT
      LAYER M4 ;
        RECT  0 32.4 0.084 32.424 ;
    END
  END o[94]
  PIN o[95]
    DIRECTION OUTPUT ;
    USE SIGNAL ;
    PORT
      LAYER M4 ;
        RECT  0 32.496 0.084 32.52 ;
    END
  END o[95]
  PIN o[96]
    DIRECTION OUTPUT ;
    USE SIGNAL ;
    PORT
      LAYER M4 ;
        RECT  0 38.736 0.084 38.76 ;
    END
  END o[96]
  PIN o[97]
    DIRECTION OUTPUT ;
    USE SIGNAL ;
    PORT
      LAYER M4 ;
        RECT  0 38.832 0.084 38.856 ;
    END
  END o[97]
  PIN o[98]
    DIRECTION OUTPUT ;
    USE SIGNAL ;
    PORT
      LAYER M4 ;
        RECT  0 38.928 0.084 38.952 ;
    END
  END o[98]
  PIN o[99]
    DIRECTION OUTPUT ;
    USE SIGNAL ;
    PORT
      LAYER M4 ;
        RECT  0 39.024 0.084 39.048 ;
    END
  END o[99]
  PIN o[9]
    DIRECTION OUTPUT ;
    USE SIGNAL ;
    PORT
      LAYER M4 ;
        RECT  0 42.672 0.084 42.696 ;
    END
  END o[9]
  PIN rs
    DIRECTION INPUT ;
    USE SIGNAL ;
    PORT
      LAYER M5 ;
        RECT  10.8 0 10.824 0.084 ;
    END
  END rs
  PIN VDD
    DIRECTION INOUT ;
    USE POWER ;
    PORT
      LAYER M5 ;
        RECT  18.792 2.151 18.912 62.649 ;
        RECT  16.092 2.151 16.212 62.649 ;
        RECT  13.392 2.151 13.512 62.649 ;
        RECT  10.692 2.151 10.812 62.649 ;
        RECT  7.992 2.151 8.112 62.649 ;
        RECT  5.292 2.151 5.412 62.649 ;
        RECT  2.592 2.151 2.712 62.649 ;
    END
  END VDD
  PIN VSS
    DIRECTION INOUT ;
    USE GROUND ;
    PORT
      LAYER M5 ;
        RECT  18.6 2.137 18.72 62.663 ;
        RECT  15.9 2.137 16.02 62.663 ;
        RECT  13.2 2.137 13.32 62.663 ;
        RECT  10.5 2.137 10.62 62.663 ;
        RECT  7.8 2.137 7.92 62.663 ;
        RECT  5.1 2.137 5.22 62.663 ;
        RECT  2.4 2.137 2.52 62.663 ;
    END
  END VSS
  # OT_OBS_CLOSED layer=M5 d_um=1.536 added=117
  OBS
    LAYER RVTN ;
     RECT  2.16 2.16 19.44 2.295 ;
     RECT  2.16 2.565 19.44 2.835 ;
     RECT  2.16 3.105 19.44 3.375 ;
     RECT  2.16 3.645 19.44 3.915 ;
     RECT  2.16 4.185 19.44 4.455 ;
     RECT  2.16 4.725 19.44 4.995 ;
     RECT  2.16 5.265 19.44 5.535 ;
     RECT  2.16 5.805 19.44 6.075 ;
     RECT  2.16 6.345 19.44 6.615 ;
     RECT  2.16 6.885 19.44 7.155 ;
     RECT  2.16 7.425 19.44 7.695 ;
     RECT  2.16 7.965 19.44 8.235 ;
     RECT  2.16 8.505 19.44 8.775 ;
     RECT  2.16 9.045 19.44 9.315 ;
     RECT  2.16 9.585 19.44 9.855 ;
     RECT  2.16 10.125 19.44 10.395 ;
     RECT  2.16 10.665 19.44 10.935 ;
     RECT  2.16 11.205 19.44 11.475 ;
     RECT  2.16 11.745 19.44 12.015 ;
     RECT  2.16 12.285 19.44 12.555 ;
     RECT  2.16 12.825 19.44 13.095 ;
     RECT  2.16 13.365 19.44 13.635 ;
     RECT  2.16 13.905 19.44 14.175 ;
     RECT  2.16 14.445 19.44 14.715 ;
     RECT  2.16 14.985 19.44 15.255 ;
     RECT  2.16 15.525 19.44 15.795 ;
     RECT  2.16 16.065 19.44 16.335 ;
     RECT  2.16 16.605 19.44 16.875 ;
     RECT  2.16 17.145 19.44 17.415 ;
     RECT  2.16 17.685 19.44 17.955 ;
     RECT  2.16 18.225 19.44 18.495 ;
     RECT  2.16 18.765 19.44 19.035 ;
     RECT  2.16 19.305 19.44 19.575 ;
     RECT  2.16 19.845 19.44 20.115 ;
     RECT  2.16 20.385 19.44 20.655 ;
     RECT  2.16 20.925 19.44 21.195 ;
     RECT  2.16 21.465 19.44 21.735 ;
     RECT  2.16 22.005 19.44 22.275 ;
     RECT  2.16 22.545 19.44 22.815 ;
     RECT  2.16 23.085 19.44 23.355 ;
     RECT  2.16 23.625 19.44 23.895 ;
     RECT  2.16 24.165 19.44 24.435 ;
     RECT  2.16 24.705 19.44 24.975 ;
     RECT  2.16 25.245 19.44 25.515 ;
     RECT  2.16 25.785 19.44 26.055 ;
     RECT  2.16 26.325 19.44 26.595 ;
     RECT  2.16 26.865 19.44 27.135 ;
     RECT  2.16 27.405 19.44 27.675 ;
     RECT  2.16 27.945 19.44 28.215 ;
     RECT  2.16 28.485 19.44 28.755 ;
     RECT  2.16 29.025 19.44 29.295 ;
     RECT  2.16 29.565 19.44 29.835 ;
     RECT  2.16 30.105 19.44 30.375 ;
     RECT  2.16 30.645 19.44 30.915 ;
     RECT  2.16 31.185 19.44 31.455 ;
     RECT  2.16 31.725 19.44 31.995 ;
     RECT  2.16 32.265 19.44 32.535 ;
     RECT  2.16 32.805 19.44 33.075 ;
     RECT  2.16 33.345 19.44 33.615 ;
     RECT  2.16 33.885 19.44 34.155 ;
     RECT  2.16 34.425 19.44 34.695 ;
     RECT  2.16 34.965 19.44 35.235 ;
     RECT  2.16 35.505 19.44 35.775 ;
     RECT  2.16 36.045 19.44 36.315 ;
     RECT  2.16 36.585 19.44 36.855 ;
     RECT  2.16 37.125 19.44 37.395 ;
     RECT  2.16 37.665 19.44 37.935 ;
     RECT  2.16 38.205 19.44 38.475 ;
     RECT  2.16 38.745 19.44 39.015 ;
     RECT  2.16 39.285 19.44 39.555 ;
     RECT  2.16 39.825 19.44 40.095 ;
     RECT  2.16 40.365 19.44 40.635 ;
     RECT  2.16 40.905 19.44 41.175 ;
     RECT  2.16 41.445 19.44 41.715 ;
     RECT  2.16 41.985 19.44 42.255 ;
     RECT  2.16 42.525 19.44 42.795 ;
     RECT  2.16 43.065 19.44 43.335 ;
     RECT  2.16 43.605 19.44 43.875 ;
     RECT  2.16 44.145 19.44 44.415 ;
     RECT  2.16 44.685 19.44 44.955 ;
     RECT  2.16 45.225 19.44 45.495 ;
     RECT  2.16 45.765 19.44 46.035 ;
     RECT  2.16 46.305 19.44 46.575 ;
     RECT  2.16 46.845 19.44 47.115 ;
     RECT  2.16 47.385 19.44 47.655 ;
     RECT  2.16 47.925 19.44 48.195 ;
     RECT  2.16 48.465 19.44 48.735 ;
     RECT  2.16 49.005 19.44 49.275 ;
     RECT  2.16 49.545 19.44 49.815 ;
     RECT  2.16 50.085 19.44 50.355 ;
     RECT  2.16 50.625 19.44 50.895 ;
     RECT  2.16 51.165 19.44 51.435 ;
     RECT  2.16 51.705 19.44 51.975 ;
     RECT  2.16 52.245 19.44 52.515 ;
     RECT  2.16 52.785 19.44 53.055 ;
     RECT  2.16 53.325 19.44 53.595 ;
     RECT  2.16 53.865 19.44 54.135 ;
     RECT  2.16 54.405 19.44 54.675 ;
     RECT  2.16 54.945 19.44 55.215 ;
     RECT  2.16 55.485 19.44 55.755 ;
     RECT  2.16 56.025 19.44 56.295 ;
     RECT  2.16 56.565 19.44 56.835 ;
     RECT  2.16 57.105 19.44 57.375 ;
     RECT  2.16 57.645 19.44 57.915 ;
     RECT  2.16 58.185 19.44 58.455 ;
     RECT  2.16 58.725 19.44 58.995 ;
     RECT  2.16 59.265 19.44 59.535 ;
     RECT  2.16 59.805 19.44 60.075 ;
     RECT  2.16 60.345 19.44 60.615 ;
     RECT  2.16 60.885 19.44 61.155 ;
     RECT  2.16 61.425 19.44 61.695 ;
     RECT  2.16 61.965 19.44 62.235 ;
     RECT  2.16 62.505 19.44 62.64 ;
    LAYER RVTP ;
     RECT  2.16 2.295 19.44 2.565 ;
     RECT  2.16 2.835 19.44 3.105 ;
     RECT  2.16 3.375 19.44 3.645 ;
     RECT  2.16 3.915 19.44 4.185 ;
     RECT  2.16 4.455 19.44 4.725 ;
     RECT  2.16 4.995 19.44 5.265 ;
     RECT  2.16 5.535 19.44 5.805 ;
     RECT  2.16 6.075 19.44 6.345 ;
     RECT  2.16 6.615 19.44 6.885 ;
     RECT  2.16 7.155 19.44 7.425 ;
     RECT  2.16 7.695 19.44 7.965 ;
     RECT  2.16 8.235 19.44 8.505 ;
     RECT  2.16 8.775 19.44 9.045 ;
     RECT  2.16 9.315 19.44 9.585 ;
     RECT  2.16 9.855 19.44 10.125 ;
     RECT  2.16 10.395 19.44 10.665 ;
     RECT  2.16 10.935 19.44 11.205 ;
     RECT  2.16 11.475 19.44 11.745 ;
     RECT  2.16 12.015 19.44 12.285 ;
     RECT  2.16 12.555 19.44 12.825 ;
     RECT  2.16 13.095 19.44 13.365 ;
     RECT  2.16 13.635 19.44 13.905 ;
     RECT  2.16 14.175 19.44 14.445 ;
     RECT  2.16 14.715 19.44 14.985 ;
     RECT  2.16 15.255 19.44 15.525 ;
     RECT  2.16 15.795 19.44 16.065 ;
     RECT  2.16 16.335 19.44 16.605 ;
     RECT  2.16 16.875 19.44 17.145 ;
     RECT  2.16 17.415 19.44 17.685 ;
     RECT  2.16 17.955 19.44 18.225 ;
     RECT  2.16 18.495 19.44 18.765 ;
     RECT  2.16 19.035 19.44 19.305 ;
     RECT  2.16 19.575 19.44 19.845 ;
     RECT  2.16 20.115 19.44 20.385 ;
     RECT  2.16 20.655 19.44 20.925 ;
     RECT  2.16 21.195 19.44 21.465 ;
     RECT  2.16 21.735 19.44 22.005 ;
     RECT  2.16 22.275 19.44 22.545 ;
     RECT  2.16 22.815 19.44 23.085 ;
     RECT  2.16 23.355 19.44 23.625 ;
     RECT  2.16 23.895 19.44 24.165 ;
     RECT  2.16 24.435 19.44 24.705 ;
     RECT  2.16 24.975 19.44 25.245 ;
     RECT  2.16 25.515 19.44 25.785 ;
     RECT  2.16 26.055 19.44 26.325 ;
     RECT  2.16 26.595 19.44 26.865 ;
     RECT  2.16 27.135 19.44 27.405 ;
     RECT  2.16 27.675 19.44 27.945 ;
     RECT  2.16 28.215 19.44 28.485 ;
     RECT  2.16 28.755 19.44 29.025 ;
     RECT  2.16 29.295 19.44 29.565 ;
     RECT  2.16 29.835 19.44 30.105 ;
     RECT  2.16 30.375 19.44 30.645 ;
     RECT  2.16 30.915 19.44 31.185 ;
     RECT  2.16 31.455 19.44 31.725 ;
     RECT  2.16 31.995 19.44 32.265 ;
     RECT  2.16 32.535 19.44 32.805 ;
     RECT  2.16 33.075 19.44 33.345 ;
     RECT  2.16 33.615 19.44 33.885 ;
     RECT  2.16 34.155 19.44 34.425 ;
     RECT  2.16 34.695 19.44 34.965 ;
     RECT  2.16 35.235 19.44 35.505 ;
     RECT  2.16 35.775 19.44 36.045 ;
     RECT  2.16 36.315 19.44 36.585 ;
     RECT  2.16 36.855 19.44 37.125 ;
     RECT  2.16 37.395 19.44 37.665 ;
     RECT  2.16 37.935 19.44 38.205 ;
     RECT  2.16 38.475 19.44 38.745 ;
     RECT  2.16 39.015 19.44 39.285 ;
     RECT  2.16 39.555 19.44 39.825 ;
     RECT  2.16 40.095 19.44 40.365 ;
     RECT  2.16 40.635 19.44 40.905 ;
     RECT  2.16 41.175 19.44 41.445 ;
     RECT  2.16 41.715 19.44 41.985 ;
     RECT  2.16 42.255 19.44 42.525 ;
     RECT  2.16 42.795 19.44 43.065 ;
     RECT  2.16 43.335 19.44 43.605 ;
     RECT  2.16 43.875 19.44 44.145 ;
     RECT  2.16 44.415 19.44 44.685 ;
     RECT  2.16 44.955 19.44 45.225 ;
     RECT  2.16 45.495 19.44 45.765 ;
     RECT  2.16 46.035 19.44 46.305 ;
     RECT  2.16 46.575 19.44 46.845 ;
     RECT  2.16 47.115 19.44 47.385 ;
     RECT  2.16 47.655 19.44 47.925 ;
     RECT  2.16 48.195 19.44 48.465 ;
     RECT  2.16 48.735 19.44 49.005 ;
     RECT  2.16 49.275 19.44 49.545 ;
     RECT  2.16 49.815 19.44 50.085 ;
     RECT  2.16 50.355 19.44 50.625 ;
     RECT  2.16 50.895 19.44 51.165 ;
     RECT  2.16 51.435 19.44 51.705 ;
     RECT  2.16 51.975 19.44 52.245 ;
     RECT  2.16 52.515 19.44 52.785 ;
     RECT  2.16 53.055 19.44 53.325 ;
     RECT  2.16 53.595 19.44 53.865 ;
     RECT  2.16 54.135 19.44 54.405 ;
     RECT  2.16 54.675 19.44 54.945 ;
     RECT  2.16 55.215 19.44 55.485 ;
     RECT  2.16 55.755 19.44 56.025 ;
     RECT  2.16 56.295 19.44 56.565 ;
     RECT  2.16 56.835 19.44 57.105 ;
     RECT  2.16 57.375 19.44 57.645 ;
     RECT  2.16 57.915 19.44 58.185 ;
     RECT  2.16 58.455 19.44 58.725 ;
     RECT  2.16 58.995 19.44 59.265 ;
     RECT  2.16 59.535 19.44 59.805 ;
     RECT  2.16 60.075 19.44 60.345 ;
     RECT  2.16 60.615 19.44 60.885 ;
     RECT  2.16 61.155 19.44 61.425 ;
     RECT  2.16 61.695 19.44 61.965 ;
     RECT  2.16 62.235 19.44 62.505 ;
    LAYER M1 ;
     RECT  2.16 2.151 19.44 62.649 ;
    LAYER M2 ;
     RECT  0.103 8.946 0.139 9.684 ;
     RECT  0.103 10.836 0.139 10.854 ;
     RECT  0.103 12.366 0.139 13.284 ;
     RECT  0.103 27.342 0.139 27.36 ;
     RECT  0.103 30.726 0.139 30.744 ;
     RECT  0.103 31.536 0.139 31.554 ;
     RECT  0.103 32.346 0.139 33.534 ;
     RECT  0.103 37.026 0.139 37.044 ;
     RECT  0.103 38.556 0.139 39.78 ;
     RECT  0.103 48.276 0.139 48.294 ;
     RECT  0.139 14.796 0.175 14.814 ;
     RECT  0.103 20.466 0.175 20.484 ;
     RECT  0.103 24.912 0.175 25.344 ;
     RECT  0.139 26.136 0.175 26.154 ;
     RECT  0.139 27.216 0.175 27.36 ;
     RECT  0.139 31.536 0.175 33.534 ;
     RECT  0.103 49.446 0.175 49.464 ;
     RECT  0.103 50.706 0.175 50.994 ;
     RECT  0.103 51.831 0.175 53.892 ;
     RECT  0.103 54.684 0.175 55.242 ;
     RECT  0.103 56.196 0.175 56.754 ;
     RECT  0.103 57.546 0.175 58.014 ;
     RECT  0.103 60.966 0.175 60.984 ;
     RECT  0.139 8.946 0.203 10.854 ;
     RECT  0.139 12.294 0.211 13.284 ;
     RECT  0.175 14.076 0.211 14.814 ;
     RECT  0.175 24.714 0.211 26.154 ;
     RECT  0.103 29.304 0.211 29.322 ;
     RECT  0.139 30.114 0.211 30.744 ;
     RECT  0.175 60.696 0.211 60.984 ;
     RECT  0.103 61.866 0.211 62.262 ;
     RECT  0.203 10.206 0.239 10.854 ;
     RECT  0.211 12.294 0.239 14.814 ;
     RECT  0.211 24.714 0.247 26.352 ;
     RECT  0.175 27.216 0.247 27.594 ;
     RECT  0.211 29.304 0.247 30.744 ;
     RECT  0.175 51.831 0.247 58.014 ;
     RECT  0.211 60.696 0.275 62.262 ;
     RECT  0.239 10.836 0.283 10.854 ;
     RECT  0.247 24.714 0.347 27.594 ;
     RECT  0.139 37.944 0.347 39.78 ;
     RECT  0.247 51.831 0.391 58.104 ;
     RECT  0.103 59.166 0.391 59.724 ;
     RECT  0.391 42.696 0.427 42.714 ;
     RECT  0.283 10.836 0.463 11.349 ;
     RECT  0.239 12.294 0.463 14.094 ;
     RECT  0.427 42.696 0.463 42.894 ;
     RECT  0.103 7.938 0.499 7.956 ;
     RECT  0.203 8.946 0.499 9.414 ;
     RECT  0.175 20.394 0.499 20.484 ;
     RECT  0.463 22.896 0.499 22.914 ;
     RECT  0.247 28.764 0.499 30.744 ;
     RECT  0.175 31.536 0.499 34.11 ;
     RECT  0.463 42.534 0.499 42.894 ;
     RECT  0.175 49.446 0.499 50.994 ;
     RECT  0.391 51.831 0.499 59.724 ;
     RECT  0.275 60.696 0.499 61.452 ;
     RECT  0.499 6.966 0.535 6.984 ;
     RECT  0.499 16.686 0.535 16.704 ;
     RECT  0.103 17.658 0.535 17.676 ;
     RECT  0.103 18.774 0.535 19.224 ;
     RECT  0.499 20.394 0.535 21.222 ;
     RECT  0.499 22.896 0.535 23.346 ;
     RECT  0.347 25.056 0.535 27.594 ;
     RECT  0.103 35.316 0.535 35.334 ;
     RECT  0.499 41.994 0.535 42.894 ;
     RECT  0.139 48.276 0.535 48.384 ;
     RECT  0.499 49.284 0.535 50.994 ;
     RECT  0.499 51.786 0.535 61.452 ;
     RECT  0.535 41.994 1.219 43.326 ;
     RECT  0.103 4.536 1.399 4.554 ;
     RECT  0.535 49.284 1.687 61.452 ;
     RECT  0.275 62.244 1.687 62.262 ;
     RECT  0.103 3.384 2.16 3.402 ;
     RECT  1.399 4.536 2.16 4.824 ;
     RECT  0.535 6.966 2.16 7.182 ;
     RECT  0.499 7.938 2.16 9.414 ;
     RECT  0.463 10.836 2.16 14.094 ;
     RECT  0.535 16.344 2.16 16.704 ;
     RECT  0.535 17.658 2.16 19.368 ;
     RECT  0.535 20.394 2.16 21.294 ;
     RECT  0.535 22.176 2.16 23.346 ;
     RECT  0.535 25.056 2.16 27.702 ;
     RECT  0.499 28.764 2.16 34.182 ;
     RECT  0.535 35.316 2.16 35.604 ;
     RECT  0.139 36.396 2.16 37.044 ;
     RECT  0.347 37.944 2.16 39.312 ;
     RECT  0.535 40.914 2.16 40.932 ;
     RECT  1.219 41.994 2.16 43.704 ;
     RECT  0.103 45.576 2.16 46.674 ;
     RECT  0.535 48.24 2.16 48.384 ;
     RECT  1.687 49.284 2.16 62.262 ;
     RECT  2.16 2.151 2.335 62.649 ;
     RECT  2.335 2.034 3.307 62.649 ;
     RECT  3.307 1.962 3.703 62.649 ;
     RECT  3.703 1.962 6.359 62.694 ;
     RECT  6.359 2.034 9.419 62.694 ;
     RECT  9.419 2.151 9.491 62.694 ;
     RECT  9.491 2.151 10.219 62.649 ;
     RECT  10.219 2.106 10.687 62.649 ;
     RECT  10.687 2.07 15.367 62.649 ;
     RECT  15.367 1.962 16.267 62.649 ;
     RECT  16.267 1.926 18.859 62.649 ;
     RECT  18.859 1.881 19.44 62.649 ;
     RECT  19.44 1.881 19.931 62.496 ;
     RECT  19.931 1.881 19.967 13.968 ;
     RECT  19.967 1.881 20.003 13.464 ;
     RECT  19.931 24.408 20.183 62.496 ;
     RECT  19.931 14.724 20.219 23.616 ;
     RECT  20.183 39.6 20.255 62.496 ;
     RECT  20.255 39.6 20.291 60.372 ;
     RECT  20.255 61.2 20.291 62.496 ;
     RECT  20.291 40.068 20.327 60.372 ;
     RECT  20.183 24.408 20.363 38.736 ;
     RECT  20.291 61.938 20.399 62.496 ;
     RECT  20.003 1.881 20.435 12.546 ;
     RECT  20.219 14.724 20.435 16.056 ;
     RECT  20.219 16.884 20.435 23.616 ;
     RECT  20.363 24.408 20.435 34.524 ;
     RECT  20.363 35.316 20.435 38.736 ;
     RECT  20.327 40.068 20.435 56.25 ;
     RECT  20.327 57.078 20.435 60.372 ;
     RECT  20.399 61.938 20.435 62.226 ;
     RECT  20.435 2.808 20.471 3.906 ;
     RECT  20.435 41.76 20.471 49.644 ;
     RECT  20.435 50.751 20.471 54.234 ;
     RECT  20.435 1.881 20.507 2.052 ;
     RECT  20.435 4.968 20.507 10.386 ;
     RECT  20.435 16.884 20.507 20.682 ;
     RECT  20.435 21.438 20.507 22.374 ;
     RECT  20.435 23.166 20.507 23.616 ;
     RECT  20.435 24.948 20.507 34.524 ;
     RECT  20.435 40.068 20.507 40.734 ;
     RECT  20.471 41.76 20.507 46.098 ;
     RECT  20.471 47.358 20.507 49.644 ;
     RECT  20.471 53.37 20.507 53.388 ;
     RECT  20.435 59.472 20.507 60.372 ;
     RECT  20.435 62.208 20.507 62.226 ;
     RECT  20.471 2.808 20.543 3.402 ;
     RECT  20.507 5.04 20.543 9.072 ;
     RECT  20.003 13.446 20.543 13.464 ;
     RECT  20.507 16.884 20.543 17.406 ;
     RECT  20.507 20.43 20.543 20.682 ;
     RECT  20.507 25.758 20.543 29.826 ;
     RECT  20.507 33.624 20.543 34.524 ;
     RECT  20.507 41.76 20.543 45.288 ;
     RECT  20.507 48.168 20.543 49.644 ;
     RECT  20.471 54.216 20.543 54.234 ;
     RECT  20.435 57.114 20.543 58.284 ;
     RECT  20.543 3.384 20.579 3.402 ;
     RECT  20.543 7.164 20.579 8.262 ;
     RECT  20.543 9.018 20.579 9.072 ;
     RECT  20.435 11.25 20.579 12.546 ;
     RECT  20.543 33.624 20.579 34.416 ;
     RECT  20.543 5.778 20.615 6.408 ;
     RECT  20.579 11.826 20.615 12.546 ;
     RECT  20.507 30.888 20.615 32.868 ;
     RECT  20.435 14.724 20.651 15.858 ;
     RECT  20.471 50.751 21.199 52.236 ;
     RECT  20.543 57.114 21.199 58.014 ;
     RECT  20.507 40.41 21.235 40.734 ;
     RECT  20.543 48.708 21.235 49.644 ;
     RECT  21.199 50.562 21.235 52.236 ;
     RECT  20.615 32.31 21.263 32.868 ;
     RECT  20.435 35.316 21.271 36.108 ;
     RECT  21.235 40.41 21.271 41.004 ;
     RECT  20.543 25.758 21.299 29.016 ;
     RECT  21.235 48.708 21.299 52.236 ;
     RECT  21.199 57.006 21.299 58.014 ;
     RECT  21.271 35.316 21.307 36.144 ;
     RECT  20.435 55.026 21.343 56.25 ;
     RECT  20.615 30.888 21.371 31.059 ;
     RECT  20.435 36.9 21.371 38.736 ;
     RECT  21.299 50.292 21.371 52.236 ;
     RECT  20.651 15.03 21.379 15.858 ;
     RECT  20.579 33.696 21.379 33.984 ;
     RECT  21.307 34.74 21.379 36.144 ;
     RECT  21.299 25.758 21.407 28.278 ;
     RECT  21.371 37.062 21.407 38.736 ;
     RECT  21.271 40.41 21.407 41.094 ;
     RECT  21.299 48.708 21.407 48.996 ;
     RECT  20.615 11.826 21.415 11.844 ;
     RECT  21.379 14.76 21.415 15.858 ;
     RECT  20.543 16.884 21.415 17.244 ;
     RECT  21.379 33.696 21.415 36.144 ;
     RECT  20.507 47.358 21.415 47.376 ;
     RECT  20.615 5.778 21.443 5.796 ;
     RECT  20.579 9.018 21.443 9.036 ;
     RECT  21.415 14.76 21.443 17.244 ;
     RECT  20.507 18.198 21.443 18.216 ;
     RECT  20.507 21.438 21.443 21.96 ;
     RECT  20.507 23.598 21.443 23.616 ;
     RECT  21.407 25.758 21.443 25.776 ;
     RECT  21.407 26.838 21.443 28.278 ;
     RECT  21.415 33.696 21.443 36.27 ;
     RECT  21.415 47.016 21.443 47.376 ;
     RECT  21.299 57.114 21.443 58.014 ;
     RECT  20.543 29.808 21.451 29.826 ;
     RECT  21.371 30.888 21.451 31.014 ;
     RECT  20.507 1.881 21.479 1.944 ;
     RECT  21.443 14.76 21.479 15.048 ;
     RECT  21.443 15.84 21.479 17.244 ;
     RECT  21.443 26.838 21.479 27.36 ;
     RECT  21.451 29.808 21.479 31.014 ;
     RECT  21.407 37.062 21.479 38.538 ;
     RECT  21.407 40.716 21.479 40.932 ;
     RECT  20.543 42.03 21.479 45.288 ;
     RECT  21.371 50.706 21.479 52.236 ;
     RECT  21.443 57.114 21.479 57.132 ;
     RECT  21.443 57.96 21.479 58.014 ;
     RECT  21.479 1.926 21.515 1.944 ;
     RECT  20.579 7.668 21.515 8.262 ;
     RECT  20.507 9.828 21.515 9.846 ;
     RECT  21.415 11.826 21.515 12.384 ;
     RECT  21.479 15.84 21.515 16.596 ;
     RECT  20.507 19.116 21.515 19.134 ;
     RECT  20.543 20.43 21.515 20.448 ;
     RECT  21.443 21.942 21.515 21.96 ;
     RECT  21.479 27.342 21.515 27.36 ;
     RECT  21.443 28.26 21.515 28.278 ;
     RECT  21.479 30.501 21.515 30.906 ;
     RECT  21.263 32.85 21.515 32.868 ;
     RECT  21.443 34.668 21.515 36.27 ;
     RECT  21.479 38.52 21.515 38.538 ;
     RECT  21.479 42.03 21.515 43.164 ;
     RECT  21.479 44.496 21.515 45.288 ;
     RECT  20.507 46.08 21.515 46.098 ;
     RECT  21.443 47.016 21.515 47.034 ;
     RECT  21.407 48.708 21.515 48.726 ;
     RECT  21.479 50.796 21.515 51.498 ;
     RECT  21.415 53.406 21.515 53.424 ;
     RECT  21.343 54.612 21.515 56.25 ;
     RECT  21.479 57.996 21.515 58.014 ;
     RECT  21.515 34.668 21.551 34.686 ;
     RECT  21.515 35.856 21.551 36.108 ;
     RECT  21.515 30.501 21.587 30.519 ;
     RECT  21.443 33.696 21.587 33.714 ;
     RECT  21.551 35.856 21.587 35.874 ;
     RECT  21.479 37.062 21.587 37.224 ;
     RECT  21.515 54.612 21.587 54.702 ;
     RECT  21.487 62.316 21.587 62.334 ;
    LAYER M3 ;
     RECT  19.908 0.811 19.926 0.907 ;
     RECT  19.908 0.907 20.43 1.003 ;
     RECT  18.576 0.715 18.594 1.099 ;
     RECT  17.856 1.099 18.594 1.387 ;
     RECT  19.908 1.003 20.502 1.483 ;
     RECT  17.82 1.387 18.594 1.579 ;
     RECT  17.82 1.579 18.774 1.675 ;
     RECT  19.872 1.483 20.502 1.675 ;
     RECT  21.492 1.291 21.51 1.771 ;
     RECT  21.456 1.771 21.51 1.904 ;
     RECT  21.492 1.904 21.51 1.949 ;
     RECT  4.14 1.867 4.158 2.029 ;
     RECT  15.372 1.957 15.39 2.029 ;
     RECT  16.272 1.921 16.29 2.029 ;
     RECT  2.34 2.029 2.358 2.059 ;
     RECT  10.656 1.963 10.674 2.065 ;
     RECT  15.372 2.029 16.29 2.065 ;
     RECT  2.34 2.059 2.394 2.101 ;
     RECT  3.312 1.957 3.33 2.101 ;
     RECT  4.14 2.029 4.698 2.101 ;
     RECT  6.336 1.957 6.354 2.101 ;
     RECT  7.128 2.065 7.146 2.101 ;
     RECT  9.396 2.029 9.414 2.101 ;
     RECT  10.656 2.065 10.71 2.101 ;
     RECT  17.82 1.675 20.502 2.101 ;
     RECT  6.264 2.101 7.146 2.143 ;
     RECT  2.34 2.101 5.418 2.155 ;
     RECT  2.304 2.155 5.418 2.191 ;
     RECT  6.264 2.143 7.905 2.191 ;
     RECT  10.224 2.101 10.71 2.191 ;
     RECT  13.215 2.143 13.305 2.191 ;
     RECT  15.372 2.065 16.398 2.191 ;
     RECT  17.784 2.101 20.502 2.191 ;
     RECT  12.132 2.191 12.15 2.251 ;
     RECT  10.224 2.191 10.926 2.263 ;
     RECT  2.304 2.191 7.905 2.299 ;
     RECT  12.996 2.191 13.305 2.299 ;
     RECT  2.304 2.299 8.154 2.335 ;
     RECT  9.072 2.101 9.414 2.335 ;
     RECT  11.952 2.251 12.15 2.335 ;
     RECT  12.924 2.299 13.305 2.335 ;
     RECT  11.952 2.335 13.305 2.413 ;
     RECT  15.372 2.191 20.502 2.443 ;
     RECT  2.304 2.335 9.414 2.497 ;
     RECT  10.224 2.263 11.034 2.497 ;
     RECT  11.952 2.413 13.497 2.497 ;
     RECT  11.952 2.497 13.59 2.539 ;
     RECT  2.304 2.497 11.034 2.569 ;
     RECT  11.952 2.539 13.662 2.569 ;
     RECT  2.304 2.569 13.662 2.587 ;
     RECT  2.268 2.587 13.662 2.641 ;
     RECT  2.268 2.641 14.526 2.765 ;
     RECT  2.304 2.765 14.526 2.839 ;
     RECT  15.372 2.443 20.538 2.839 ;
     RECT  0.324 2.635 0.342 2.861 ;
     RECT  2.304 2.839 20.538 3.115 ;
     RECT  2.304 3.115 20.574 3.407 ;
     RECT  2.304 3.407 20.538 3.577 ;
     RECT  2.268 3.577 20.538 3.677 ;
     RECT  21.42 3.979 21.438 4.157 ;
     RECT  0.108 3.379 0.126 4.363 ;
     RECT  2.304 3.677 20.538 4.487 ;
     RECT  1.404 1.963 1.422 4.829 ;
     RECT  0.108 4.363 0.342 4.973 ;
     RECT  0.144 4.973 0.342 5.549 ;
     RECT  21.42 5.515 21.438 5.801 ;
     RECT  2.34 4.487 20.538 5.803 ;
     RECT  2.304 5.803 20.538 5.899 ;
     RECT  0.144 5.549 0.162 6.077 ;
     RECT  2.304 5.899 20.574 6.385 ;
     RECT  2.304 6.385 20.61 6.809 ;
     RECT  2.376 6.809 20.61 6.989 ;
     RECT  0.504 6.961 0.522 7.159 ;
     RECT  2.376 6.989 20.574 7.187 ;
     RECT  2.376 7.187 20.538 7.373 ;
     RECT  21.492 7.147 21.51 7.531 ;
     RECT  0.504 7.159 0.558 7.565 ;
     RECT  2.376 7.373 20.286 7.627 ;
     RECT  21.312 7.531 21.51 7.661 ;
     RECT  0.504 7.565 0.522 7.933 ;
     RECT  2.304 7.627 20.286 7.933 ;
     RECT  2.232 7.933 20.286 8.107 ;
     RECT  21.42 7.661 21.51 8.621 ;
     RECT  2.232 8.107 20.43 8.779 ;
     RECT  2.232 8.779 20.502 8.815 ;
     RECT  2.232 8.815 20.538 8.879 ;
     RECT  21.42 8.621 21.438 9.041 ;
     RECT  2.304 8.879 20.538 9.049 ;
     RECT  0.108 7.933 0.522 9.355 ;
     RECT  0.108 9.355 0.63 9.485 ;
     RECT  2.304 9.049 20.574 9.677 ;
     RECT  21.492 9.355 21.51 9.851 ;
     RECT  2.304 9.677 20.502 10.391 ;
     RECT  21.312 10.699 21.51 10.829 ;
     RECT  2.304 10.391 20.43 11.245 ;
     RECT  2.304 11.245 20.574 11.326 ;
     RECT  2.088 11.326 20.574 11.507 ;
     RECT  2.232 11.507 20.574 11.579 ;
     RECT  2.304 11.579 20.574 11.659 ;
     RECT  2.304 11.659 20.646 11.939 ;
     RECT  2.34 11.939 20.646 12.043 ;
     RECT  21.492 10.829 21.51 12.043 ;
     RECT  2.34 12.043 21.51 12.653 ;
     RECT  2.34 12.653 20.646 12.991 ;
     RECT  0.108 9.485 0.558 14.573 ;
     RECT  0.144 14.573 0.558 14.669 ;
     RECT  2.304 12.991 20.646 14.747 ;
     RECT  0.144 14.669 0.234 14.819 ;
     RECT  0.144 14.819 0.162 14.957 ;
     RECT  2.304 14.747 20.538 15.061 ;
     RECT  2.268 15.061 20.538 15.149 ;
     RECT  0.324 15.595 0.342 15.821 ;
     RECT  2.304 15.149 20.538 16.013 ;
     RECT  2.304 16.013 20.43 16.061 ;
     RECT  2.304 16.061 20.214 16.168 ;
     RECT  2.268 16.168 20.214 16.403 ;
     RECT  2.268 16.403 19.53 16.439 ;
     RECT  0.54 16.339 0.558 16.681 ;
     RECT  0.504 16.681 0.558 16.685 ;
     RECT  21.384 12.653 21.51 16.907 ;
     RECT  2.304 16.439 19.53 17.131 ;
     RECT  20.484 16.939 20.502 17.131 ;
     RECT  2.304 17.131 20.502 17.323 ;
     RECT  2.268 17.323 20.502 17.383 ;
     RECT  2.268 17.383 20.538 17.447 ;
     RECT  2.304 17.447 20.538 17.645 ;
     RECT  0.504 16.685 0.522 17.653 ;
     RECT  0.108 17.653 0.522 17.837 ;
     RECT  0.504 17.837 0.522 18.029 ;
     RECT  2.304 17.645 20.502 18.379 ;
     RECT  2.268 18.379 20.502 18.527 ;
     RECT  21.42 16.907 21.51 18.749 ;
     RECT  0.54 18.301 0.558 18.769 ;
     RECT  21.492 18.749 21.51 19.139 ;
     RECT  2.304 18.527 20.502 19.373 ;
     RECT  2.304 19.373 14.094 19.435 ;
     RECT  2.268 19.435 14.094 19.607 ;
     RECT  0.108 18.769 0.558 20.045 ;
     RECT  14.832 19.373 20.502 20.299 ;
     RECT  0.108 20.045 0.198 20.621 ;
     RECT  21.492 20.425 21.51 20.683 ;
     RECT  14.832 20.299 20.538 20.687 ;
     RECT  14.832 20.687 20.43 20.921 ;
     RECT  0.144 20.621 0.198 21.101 ;
     RECT  0.18 21.101 0.198 21.199 ;
     RECT  0.18 21.199 0.522 21.271 ;
     RECT  0.18 21.271 0.558 21.485 ;
     RECT  2.304 19.607 14.094 21.505 ;
     RECT  14.832 20.921 20.286 21.505 ;
     RECT  0.324 21.485 0.558 21.581 ;
     RECT  21.384 20.683 21.51 21.767 ;
     RECT  2.304 21.505 20.286 21.835 ;
     RECT  21.492 21.767 21.51 21.965 ;
     RECT  2.304 21.835 20.43 22.027 ;
     RECT  2.304 22.027 20.502 22.459 ;
     RECT  2.232 22.459 20.502 22.555 ;
     RECT  2.196 22.555 20.502 22.733 ;
     RECT  0.504 21.581 0.558 22.891 ;
     RECT  0.144 22.891 0.558 23.069 ;
     RECT  2.268 22.733 20.502 23.189 ;
     RECT  2.268 23.189 20.214 23.213 ;
     RECT  0.324 23.069 0.558 23.501 ;
     RECT  2.304 23.213 20.214 23.971 ;
     RECT  2.232 23.971 20.214 24.043 ;
     RECT  0.324 23.501 0.522 24.173 ;
     RECT  0.324 24.173 0.486 24.269 ;
     RECT  2.232 24.043 20.43 24.395 ;
     RECT  2.268 24.395 20.43 24.467 ;
     RECT  2.304 24.467 20.43 24.523 ;
     RECT  0.324 24.269 0.342 24.619 ;
     RECT  21.42 23.083 21.438 24.715 ;
     RECT  21.42 24.715 21.474 24.811 ;
     RECT  0.18 24.619 0.342 24.907 ;
     RECT  21.384 24.811 21.474 24.907 ;
     RECT  0.108 24.907 0.342 25.051 ;
     RECT  0.108 25.051 0.558 25.229 ;
     RECT  21.384 24.907 21.51 25.291 ;
     RECT  21.348 25.291 21.51 25.387 ;
     RECT  2.304 24.523 20.502 25.579 ;
     RECT  21.276 25.387 21.51 25.579 ;
     RECT  2.304 25.579 21.51 26.051 ;
     RECT  0.108 25.229 0.126 26.059 ;
     RECT  0.108 26.059 0.198 26.329 ;
     RECT  0.108 26.329 0.234 26.599 ;
     RECT  0.108 26.599 0.27 26.716 ;
     RECT  2.304 26.051 20.538 26.716 ;
     RECT  2.088 26.716 20.538 26.969 ;
     RECT  0.108 26.716 0.342 27.139 ;
     RECT  2.232 26.969 20.538 27.437 ;
     RECT  2.304 27.437 20.538 27.595 ;
     RECT  21.276 26.051 21.51 27.595 ;
     RECT  0.108 27.139 0.558 27.629 ;
     RECT  0.144 27.629 0.558 28.109 ;
     RECT  2.304 27.595 21.51 28.283 ;
     RECT  0.144 28.109 0.522 28.301 ;
     RECT  2.304 28.283 21.294 28.319 ;
     RECT  2.304 28.319 20.538 28.957 ;
     RECT  21.276 28.319 21.294 29.021 ;
     RECT  0.144 28.301 0.342 29.299 ;
     RECT  21.348 29.227 21.474 29.515 ;
     RECT  2.268 28.957 20.538 29.633 ;
     RECT  0.108 29.299 0.342 29.839 ;
     RECT  2.268 29.633 20.502 30.065 ;
     RECT  0.108 29.839 0.558 30.317 ;
     RECT  2.304 30.065 20.502 30.443 ;
     RECT  21.348 29.515 21.51 30.496 ;
     RECT  21.348 30.496 21.582 30.763 ;
     RECT  0.108 30.317 0.342 31.261 ;
     RECT  2.304 30.443 20.466 31.423 ;
     RECT  2.304 31.423 20.574 31.483 ;
     RECT  2.268 31.483 20.574 31.765 ;
     RECT  21.312 30.763 21.582 31.765 ;
     RECT  2.268 31.765 21.582 32.495 ;
     RECT  0.108 31.261 0.558 32.909 ;
     RECT  2.304 32.495 21.582 33.448 ;
     RECT  2.268 33.448 21.582 33.719 ;
     RECT  0.108 32.909 0.522 33.773 ;
     RECT  0.144 33.773 0.522 33.869 ;
     RECT  0.18 33.869 0.522 33.889 ;
     RECT  2.268 33.719 21.474 34.087 ;
     RECT  2.232 34.087 21.474 34.259 ;
     RECT  0.18 33.889 0.558 34.349 ;
     RECT  0.18 34.349 0.522 34.445 ;
     RECT  2.268 34.259 21.474 34.663 ;
     RECT  2.268 34.663 21.546 34.781 ;
     RECT  2.268 34.781 20.574 34.925 ;
     RECT  2.268 34.925 20.43 34.987 ;
     RECT  2.196 34.987 20.43 35.033 ;
     RECT  0.18 34.445 0.198 35.311 ;
     RECT  0.108 35.311 0.198 35.405 ;
     RECT  0.144 35.405 0.198 35.563 ;
     RECT  21.312 34.781 21.546 35.563 ;
     RECT  0.144 35.563 0.234 35.581 ;
     RECT  21.276 35.563 21.546 35.851 ;
     RECT  21.276 35.851 21.582 35.947 ;
     RECT  0.144 35.581 0.558 35.981 ;
     RECT  21.24 35.947 21.582 36.077 ;
     RECT  2.304 35.033 20.43 36.139 ;
     RECT  21.276 36.077 21.582 36.269 ;
     RECT  0.144 35.981 0.342 36.931 ;
     RECT  0.144 36.931 0.558 37.021 ;
     RECT  2.304 36.139 20.538 37.057 ;
     RECT  21.312 36.269 21.582 37.057 ;
     RECT  2.304 37.057 21.582 37.193 ;
     RECT  0.108 37.021 0.558 37.325 ;
     RECT  2.304 37.193 20.502 37.831 ;
     RECT  2.268 37.831 20.502 38.039 ;
     RECT  2.268 38.039 20.43 38.201 ;
     RECT  0.108 37.325 0.162 39.019 ;
     RECT  0.108 39.019 0.342 39.091 ;
     RECT  2.304 38.201 20.214 39.115 ;
     RECT  2.304 39.115 20.502 39.217 ;
     RECT  2.232 39.217 20.502 39.293 ;
     RECT  0.108 39.091 0.558 39.499 ;
     RECT  0.108 39.499 0.666 39.725 ;
     RECT  0.108 39.725 0.342 39.785 ;
     RECT  0.108 39.785 0.234 39.821 ;
     RECT  2.268 39.293 20.502 39.857 ;
     RECT  2.304 39.857 20.502 40.091 ;
     RECT  0.144 39.821 0.234 40.109 ;
     RECT  0.144 40.109 0.162 40.637 ;
     RECT  21.24 37.193 21.582 40.747 ;
     RECT  21.204 40.747 21.582 41.009 ;
     RECT  21.276 41.009 21.582 41.099 ;
     RECT  0.54 40.909 0.558 41.165 ;
     RECT  2.304 40.091 20.466 41.227 ;
     RECT  2.304 41.227 20.538 41.515 ;
     RECT  2.268 41.515 20.538 41.611 ;
     RECT  2.232 41.611 20.538 41.747 ;
     RECT  0.144 41.659 0.162 41.989 ;
     RECT  1.224 41.227 1.242 41.989 ;
     RECT  2.268 41.747 20.538 42.091 ;
     RECT  21.312 41.099 21.582 42.091 ;
     RECT  2.268 42.091 21.582 42.134 ;
     RECT  2.268 42.134 20.538 42.359 ;
     RECT  2.304 42.359 20.538 42.509 ;
     RECT  2.304 42.509 20.502 43.169 ;
     RECT  0.144 41.989 1.242 43.277 ;
     RECT  21.312 42.134 21.582 43.435 ;
     RECT  0.396 43.277 1.242 43.565 ;
     RECT  21.276 43.435 21.582 43.565 ;
     RECT  0.396 43.565 0.45 43.661 ;
     RECT  1.224 43.565 1.242 43.709 ;
     RECT  0.396 43.661 0.414 43.757 ;
     RECT  2.34 43.169 20.502 44.203 ;
     RECT  2.304 44.203 20.502 44.689 ;
     RECT  2.268 44.689 20.502 44.813 ;
     RECT  0.108 45.571 0.126 45.643 ;
     RECT  0.108 45.643 0.342 45.773 ;
     RECT  2.304 44.813 20.502 45.869 ;
     RECT  0.108 45.773 0.126 46.579 ;
     RECT  2.304 45.869 20.43 46.813 ;
     RECT  2.304 46.813 20.466 46.891 ;
     RECT  0.108 46.579 0.162 46.925 ;
     RECT  0.144 46.925 0.162 46.987 ;
     RECT  0.144 46.987 0.342 47.117 ;
     RECT  2.304 46.891 20.502 48.163 ;
     RECT  0.144 47.117 0.162 48.235 ;
     RECT  0.144 48.235 0.558 48.271 ;
     RECT  2.304 48.163 20.538 48.505 ;
     RECT  2.268 48.505 20.538 48.557 ;
     RECT  0.108 48.271 0.558 48.653 ;
     RECT  21.312 43.565 21.582 48.811 ;
     RECT  0.144 48.653 0.558 49.003 ;
     RECT  2.304 48.557 20.502 49.271 ;
     RECT  0.144 49.003 1.17 49.277 ;
     RECT  0.144 49.277 0.558 49.441 ;
     RECT  0.108 49.441 0.558 50.155 ;
     RECT  0.108 50.155 1.278 50.285 ;
     RECT  21.276 48.811 21.582 50.287 ;
     RECT  1.152 50.285 1.278 50.381 ;
     RECT  2.304 49.271 20.466 50.539 ;
     RECT  2.304 50.539 20.502 50.557 ;
     RECT  21.24 50.287 21.582 50.557 ;
     RECT  1.152 50.381 1.17 50.621 ;
     RECT  2.304 50.557 21.582 50.729 ;
     RECT  0.108 50.285 0.342 51.169 ;
     RECT  2.304 50.729 20.502 51.355 ;
     RECT  0.108 51.169 0.558 51.745 ;
     RECT  0.108 51.745 0.594 51.854 ;
     RECT  2.268 51.355 20.502 52.079 ;
     RECT  2.34 52.079 20.502 52.861 ;
     RECT  0.108 51.854 0.558 53.761 ;
     RECT  0.108 53.761 1.17 53.905 ;
     RECT  2.304 52.861 20.502 53.995 ;
     RECT  0.108 53.905 1.242 54.029 ;
     RECT  1.224 54.029 1.242 54.131 ;
     RECT  2.304 53.995 20.538 54.239 ;
     RECT  0.108 54.029 0.342 54.751 ;
     RECT  2.304 54.239 20.502 55.003 ;
     RECT  0.108 54.751 0.486 55.219 ;
     RECT  0.108 55.219 0.558 55.247 ;
     RECT  2.268 55.003 20.502 55.319 ;
     RECT  2.304 55.319 20.502 55.553 ;
     RECT  0.144 55.247 0.558 55.565 ;
     RECT  2.304 55.553 20.466 56.093 ;
     RECT  0.144 55.565 0.522 56.141 ;
     RECT  0.144 56.141 0.486 56.191 ;
     RECT  21.276 50.729 21.582 57.001 ;
     RECT  0.108 56.191 0.486 57.109 ;
     RECT  2.304 56.093 20.43 57.181 ;
     RECT  2.268 57.181 20.43 57.259 ;
     RECT  21.204 57.001 21.582 57.259 ;
     RECT  0.108 57.109 0.522 57.379 ;
     RECT  2.268 57.259 21.582 57.524 ;
     RECT  0.108 57.379 0.558 57.811 ;
     RECT  0.108 57.811 1.206 58.019 ;
     RECT  2.268 57.524 20.502 58.261 ;
     RECT  2.268 58.261 20.538 58.487 ;
     RECT  0.108 58.019 0.558 59.021 ;
     RECT  2.304 58.487 20.538 59.021 ;
     RECT  0.108 59.021 0.522 59.881 ;
     RECT  0.108 59.881 0.558 59.885 ;
     RECT  0.324 59.885 0.558 60.151 ;
     RECT  0.324 60.151 0.63 60.187 ;
     RECT  0.324 60.187 1.17 60.235 ;
     RECT  0.324 60.235 1.278 60.365 ;
     RECT  2.304 59.021 20.502 60.377 ;
     RECT  0.324 60.365 1.17 60.691 ;
     RECT  0.18 60.691 1.17 60.961 ;
     RECT  2.304 60.377 20.43 61.099 ;
     RECT  0.108 60.961 1.17 61.699 ;
     RECT  2.304 61.099 20.502 61.699 ;
     RECT  0.108 61.699 20.502 61.889 ;
     RECT  0.108 61.889 18.897 61.901 ;
     RECT  12.168 61.901 18.897 61.925 ;
     RECT  12.168 61.925 17.442 61.961 ;
     RECT  12.204 61.961 17.442 61.997 ;
     RECT  0.108 61.901 11.43 62.045 ;
     RECT  12.492 61.997 17.442 62.069 ;
     RECT  12.888 62.069 17.442 62.159 ;
     RECT  19.656 61.889 20.502 62.189 ;
     RECT  15.915 62.159 17.334 62.195 ;
     RECT  19.692 62.189 20.502 62.231 ;
     RECT  0.108 62.045 10.797 62.303 ;
     RECT  12.888 62.159 14.994 62.303 ;
     RECT  21.348 57.524 21.582 62.339 ;
     RECT  21.348 62.339 21.51 62.381 ;
     RECT  0.108 62.303 8.097 62.387 ;
     RECT  8.856 62.303 10.797 62.387 ;
     RECT  12.888 62.303 13.497 62.387 ;
     RECT  15.915 62.195 16.902 62.387 ;
     RECT  18.216 61.925 18.897 62.387 ;
     RECT  0.108 62.387 7.938 62.429 ;
     RECT  18.216 62.387 18.705 62.429 ;
     RECT  8.856 62.387 10.605 62.465 ;
     RECT  14.328 62.303 14.562 62.465 ;
     RECT  21.348 62.381 21.366 62.477 ;
     RECT  0.108 62.429 6.102 62.501 ;
     RECT  6.84 62.429 7.938 62.501 ;
     RECT  9.468 62.465 10.605 62.501 ;
     RECT  19.692 62.231 20.394 62.501 ;
     RECT  0.108 62.501 5.274 62.537 ;
     RECT  6.084 62.501 6.102 62.537 ;
     RECT  6.84 62.501 7.074 62.537 ;
     RECT  12.888 62.387 13.305 62.537 ;
     RECT  14.328 62.465 14.346 62.537 ;
     RECT  7.815 62.501 7.938 62.573 ;
     RECT  16.884 62.387 16.902 62.573 ;
     RECT  19.692 62.501 20.358 62.573 ;
     RECT  0.108 62.537 5.205 62.609 ;
     RECT  6.84 62.537 7.002 62.609 ;
     RECT  3.708 62.609 5.205 62.657 ;
     RECT  7.815 62.573 7.905 62.657 ;
     RECT  10.515 62.501 10.605 62.657 ;
     RECT  13.215 62.537 13.305 62.657 ;
     RECT  15.915 62.387 16.005 62.657 ;
     RECT  18.615 62.429 18.705 62.657 ;
     RECT  3.708 62.657 4.986 62.699 ;
     RECT  6.876 62.609 7.002 62.699 ;
     RECT  9.468 62.501 9.486 62.699 ;
     RECT  0.108 62.609 2.97 62.765 ;
     RECT  19.692 62.573 20.25 62.765 ;
     RECT  0.576 62.765 2.97 62.861 ;
     RECT  19.692 62.765 19.71 62.861 ;
     RECT  4.176 62.699 4.986 62.957 ;
     RECT  0.612 62.861 2.97 63.245 ;
     RECT  1.152 63.245 2.97 63.341 ;
     RECT  4.176 62.957 4.554 63.533 ;
     RECT  1.152 63.341 1.17 63.725 ;
     RECT  2.304 63.341 2.97 63.821 ;
     RECT  4.536 63.533 4.554 63.917 ;
     RECT  2.952 63.821 2.97 64.013 ;
    LAYER M4 ;
     RECT  0.06 1.872 2.981 64.008 ;
     RECT  2.981 1.872 3.449 63.912 ;
     RECT  3.449 23.136 3.845 63.912 ;
     RECT  3.449 1.872 3.917 22.056 ;
     RECT  3.917 1.872 4.169 17.112 ;
     RECT  3.845 26.496 4.565 63.912 ;
     RECT  4.565 26.496 4.997 62.952 ;
     RECT  3.917 18.24 5.101 22.056 ;
     RECT  3.845 23.136 5.101 25.032 ;
     RECT  4.169 2.148 5.108 17.112 ;
     RECT  5.101 18.24 5.108 25.032 ;
     RECT  4.997 26.496 5.108 62.652 ;
     RECT  5.108 2.148 5.212 62.652 ;
     RECT  5.212 2.418 5.404 62.472 ;
     RECT  5.404 2.592 5.465 19.032 ;
     RECT  5.465 2.784 5.609 19.032 ;
     RECT  5.609 2.832 6.397 19.032 ;
     RECT  5.404 20.016 6.397 62.472 ;
     RECT  6.397 2.832 6.901 62.472 ;
     RECT  6.901 2.832 7.477 62.52 ;
     RECT  7.477 2.4 7.808 62.52 ;
     RECT  7.808 2.148 7.912 62.652 ;
     RECT  7.912 2.418 8.104 62.382 ;
     RECT  8.104 2.496 9.497 62.04 ;
     RECT  9.497 2.496 10.508 7.656 ;
     RECT  9.497 8.736 10.508 62.04 ;
     RECT  10.508 2.148 10.612 62.652 ;
     RECT  10.612 2.148 10.645 62.382 ;
     RECT  10.309 0.096 10.739 0.12 ;
     RECT  10.645 1.968 10.804 62.382 ;
     RECT  10.804 1.968 10.835 7.656 ;
     RECT  10.835 2.256 11.477 7.656 ;
     RECT  11.477 4.176 11.837 7.656 ;
     RECT  11.837 7.104 11.977 7.656 ;
     RECT  10.804 8.688 11.977 62.04 ;
     RECT  11.477 2.256 11.981 3.192 ;
     RECT  11.981 2.4 12.661 3.192 ;
     RECT  11.837 4.176 12.661 5.88 ;
     RECT  12.661 2.4 13.208 5.88 ;
     RECT  11.977 7.104 13.208 62.04 ;
     RECT  13.208 2.148 13.312 62.652 ;
     RECT  13.312 2.418 13.504 62.382 ;
     RECT  13.504 7.104 13.817 62.04 ;
     RECT  13.817 7.104 13.889 29.352 ;
     RECT  13.889 7.104 13.997 24.984 ;
     RECT  13.817 30.384 14.473 62.04 ;
     RECT  13.997 7.104 14.965 20.616 ;
     RECT  13.997 21.648 14.965 24.984 ;
     RECT  13.504 2.496 15.073 5.928 ;
     RECT  14.965 7.104 15.073 25.176 ;
     RECT  15.073 2.496 15.109 25.176 ;
     RECT  15.109 2.496 15.397 25.272 ;
     RECT  13.889 26.544 15.397 29.352 ;
     RECT  15.397 2.496 15.493 29.352 ;
     RECT  14.473 30.384 15.493 33.912 ;
     RECT  15.493 2.496 15.781 33.912 ;
     RECT  14.473 34.944 15.865 62.04 ;
     RECT  15.781 2.256 15.908 33.912 ;
     RECT  15.865 34.896 15.908 62.04 ;
     RECT  15.908 2.148 16.012 62.652 ;
     RECT  16.012 2.256 16.204 62.382 ;
     RECT  16.204 30.96 16.265 62.04 ;
     RECT  16.204 2.256 16.517 24.216 ;
     RECT  16.265 30.96 16.553 61.944 ;
     RECT  16.553 30.96 16.877 61.752 ;
     RECT  16.877 61.632 17.021 61.752 ;
     RECT  16.517 2.496 17.341 24.216 ;
     RECT  16.204 25.776 17.341 29.544 ;
     RECT  17.341 2.496 17.365 29.544 ;
     RECT  16.877 30.96 17.365 60.6 ;
     RECT  17.365 2.496 17.557 60.6 ;
     RECT  17.809 1.392 17.845 1.416 ;
     RECT  17.021 61.632 17.989 61.656 ;
     RECT  17.989 61.632 18.133 61.704 ;
     RECT  17.845 1.104 18.529 1.416 ;
     RECT  17.557 2.448 18.529 60.6 ;
     RECT  18.529 1.104 18.565 60.6 ;
     RECT  18.565 0.72 18.608 60.6 ;
     RECT  18.133 61.632 18.608 61.992 ;
     RECT  18.608 0.72 18.712 62.652 ;
     RECT  18.712 0.72 18.965 62.382 ;
     RECT  18.965 49.008 19.681 62.382 ;
     RECT  18.965 39.216 20.365 47.976 ;
     RECT  19.681 49.008 20.365 62.856 ;
     RECT  18.965 0.72 20.473 38.184 ;
     RECT  20.365 39.216 20.473 62.856 ;
     RECT  20.473 0.72 21.564 62.856 ;
    LAYER M5 ;
     RECT  10.704 0.016 10.824 0.085 ;
     RECT  2.4 2.137 2.52 2.151 ;
     RECT  5.1 2.137 5.22 2.151 ;
     RECT  7.8 2.137 7.92 2.151 ;
     RECT  13.2 2.137 13.32 2.151 ;
     RECT  15.9 2.137 16.02 2.151 ;
     RECT  18.6 2.137 18.72 2.151 ;
     RECT  10.32 0.085 10.824 2.245 ;
     RECT  15.9 2.151 16.212 2.245 ;
     RECT  2.4 2.151 2.712 2.485 ;
     RECT  2.4 2.485 2.856 2.627 ;
     RECT  7.8 2.151 8.112 2.821 ;
     RECT  13.2 2.151 13.512 2.821 ;
     RECT  18.6 2.151 18.912 2.821 ;
     RECT  0.144 2.485 0.168 2.867 ;
     RECT  10.32 2.245 11.4 2.869 ;
     RECT  10.128 2.869 11.4 2.915 ;
     RECT  15.792 2.245 16.212 2.915 ;
     RECT  7.68 2.821 8.112 3.443 ;
     RECT  18.6 2.821 19.128 3.589 ;
     RECT  18.6 3.589 19.368 3.877 ;
     RECT  18.144 3.877 19.368 3.925 ;
     RECT  14.784 3.109 14.808 4.019 ;
     RECT  10.128 2.915 10.812 4.115 ;
     RECT  18.048 3.925 19.368 4.453 ;
     RECT  0.144 4.213 0.168 4.499 ;
     RECT  13.104 2.821 13.512 5.557 ;
     RECT  17.184 4.453 19.368 5.845 ;
     RECT  10.32 4.115 10.812 6.229 ;
     RECT  9.504 6.229 10.812 6.803 ;
     RECT  17.184 5.845 19.416 6.805 ;
     RECT  15.9 2.915 16.212 7.381 ;
     RECT  21.408 7.477 21.432 7.667 ;
     RECT  13.008 5.557 13.512 8.149 ;
     RECT  15.792 7.381 16.212 8.723 ;
     RECT  13.008 8.149 13.608 8.869 ;
     RECT  15.9 8.723 16.212 9.109 ;
     RECT  17.184 6.805 19.464 9.109 ;
     RECT  5.1 2.151 5.412 9.589 ;
     RECT  6.72 9.061 6.744 9.589 ;
     RECT  5.1 9.589 6.744 9.635 ;
     RECT  10.32 6.803 10.812 9.637 ;
     RECT  12.96 8.869 13.608 9.683 ;
     RECT  14.832 9.349 14.856 10.643 ;
     RECT  7.8 3.443 8.112 10.933 ;
     RECT  13.008 9.683 13.608 11.077 ;
     RECT  13.008 11.077 13.704 11.125 ;
     RECT  5.1 9.635 6.264 11.171 ;
     RECT  15.9 9.109 19.464 11.269 ;
     RECT  12.24 11.125 13.704 12.085 ;
     RECT  5.1 11.171 5.544 12.227 ;
     RECT  21.408 12.229 21.432 12.419 ;
     RECT  9.456 9.637 10.812 12.469 ;
     RECT  15.9 11.269 19.944 12.563 ;
     RECT  9.264 12.469 10.812 12.805 ;
     RECT  9.264 12.805 11.208 13.091 ;
     RECT  7.68 10.933 8.112 13.621 ;
     RECT  12.24 12.085 14.328 13.715 ;
     RECT  6.912 13.621 8.112 14.675 ;
     RECT  7.584 14.675 8.112 14.677 ;
     RECT  9.264 13.091 10.812 14.677 ;
     RECT  0.144 15.541 0.168 15.827 ;
     RECT  20.496 15.829 20.52 16.019 ;
     RECT  7.584 14.677 10.812 16.115 ;
     RECT  7.584 16.115 9.288 16.501 ;
     RECT  12.24 13.715 13.512 16.501 ;
     RECT  7.392 16.501 9.288 16.595 ;
     RECT  7.392 16.595 9.048 17.123 ;
     RECT  12.24 16.501 14.28 17.605 ;
     RECT  12.144 17.605 14.28 17.651 ;
     RECT  10.32 16.115 10.812 18.037 ;
     RECT  13.2 17.651 14.28 18.131 ;
     RECT  10.08 18.037 10.812 18.325 ;
     RECT  9.12 18.325 10.812 18.421 ;
     RECT  12.144 17.651 12.168 18.421 ;
     RECT  9.12 18.421 12.168 18.467 ;
     RECT  10.08 18.467 12.168 18.563 ;
     RECT  12.144 18.563 12.168 19.285 ;
     RECT  13.2 18.131 13.512 19.285 ;
     RECT  15.9 12.563 19.464 19.333 ;
     RECT  7.392 17.123 8.112 19.525 ;
     RECT  7.392 19.525 8.232 19.571 ;
     RECT  12.144 19.285 13.512 19.813 ;
     RECT  12.144 19.813 13.656 19.859 ;
     RECT  7.8 19.571 8.232 19.861 ;
     RECT  12.336 19.859 13.656 19.955 ;
     RECT  5.1 12.227 5.412 20.005 ;
     RECT  5.1 20.005 6.264 20.149 ;
     RECT  5.1 20.149 6.6 20.579 ;
     RECT  10.08 18.563 10.812 21.061 ;
     RECT  12.336 19.955 13.512 21.061 ;
     RECT  6.576 20.579 6.6 21.107 ;
     RECT  15.168 19.333 19.464 21.251 ;
     RECT  10.08 21.061 13.512 21.683 ;
     RECT  10.08 21.683 10.812 21.781 ;
     RECT  7.8 19.861 8.424 22.021 ;
     RECT  15.408 21.251 19.464 22.499 ;
     RECT  7.344 22.021 8.424 22.501 ;
     RECT  9.696 21.781 10.812 22.501 ;
     RECT  7.344 22.501 10.812 22.741 ;
     RECT  12.336 21.683 13.512 22.741 ;
     RECT  6.48 22.741 13.512 22.787 ;
     RECT  6.48 22.787 8.424 22.931 ;
     RECT  9.696 22.787 13.512 23.269 ;
     RECT  15.792 22.499 19.464 23.315 ;
     RECT  9.696 23.269 14.76 23.555 ;
     RECT  6.48 22.931 8.232 23.941 ;
     RECT  9.696 23.555 13.512 23.941 ;
     RECT  6.48 23.941 13.512 23.987 ;
     RECT  0.144 23.605 0.168 24.755 ;
     RECT  14.736 23.555 14.76 24.947 ;
     RECT  6.48 23.987 9.048 24.949 ;
     RECT  6.48 24.949 9.144 25.091 ;
     RECT  6.48 25.091 8.568 25.139 ;
     RECT  5.1 20.579 5.412 25.429 ;
     RECT  6.864 25.139 8.568 25.811 ;
     RECT  10.32 23.987 10.812 26.101 ;
     RECT  10.32 26.101 10.968 27.059 ;
     RECT  7.344 25.811 8.568 27.637 ;
     RECT  6.816 27.637 8.568 27.829 ;
     RECT  6.816 27.829 8.808 27.923 ;
     RECT  10.32 27.059 10.812 28.885 ;
     RECT  15.9 23.315 19.464 28.981 ;
     RECT  10.32 28.885 10.92 29.075 ;
     RECT  7.344 27.923 8.808 29.605 ;
     RECT  7.344 29.605 9.144 29.699 ;
     RECT  10.32 29.075 10.812 29.797 ;
     RECT  9.12 29.699 9.144 29.843 ;
     RECT  12.336 23.987 13.512 30.851 ;
     RECT  15.504 28.981 19.464 30.947 ;
     RECT  5.1 25.429 5.784 31.141 ;
     RECT  7.344 29.699 8.112 31.141 ;
     RECT  10.224 29.797 10.812 31.189 ;
     RECT  10.08 31.189 10.812 31.427 ;
     RECT  2.4 2.627 2.712 31.477 ;
     RECT  15.792 30.947 19.464 31.525 ;
     RECT  15.792 31.525 19.656 31.573 ;
     RECT  2.4 31.477 2.856 31.715 ;
     RECT  5.1 31.141 8.112 31.955 ;
     RECT  15.792 31.573 20.232 32.005 ;
     RECT  6.864 31.955 8.112 32.147 ;
     RECT  10.5 31.427 10.812 32.917 ;
     RECT  7.296 32.147 8.112 33.107 ;
     RECT  15.792 32.005 20.328 33.107 ;
     RECT  10.5 32.917 11.304 33.541 ;
     RECT  10.08 33.541 11.304 34.259 ;
     RECT  7.344 33.107 8.112 34.741 ;
     RECT  12.384 30.851 13.512 34.741 ;
     RECT  10.08 34.259 11.256 35.027 ;
     RECT  15.9 33.107 20.328 35.317 ;
     RECT  7.344 34.741 8.232 35.845 ;
     RECT  15.792 35.317 20.328 36.275 ;
     RECT  10.224 35.027 11.256 36.901 ;
     RECT  10.176 36.901 11.256 37.477 ;
     RECT  10.176 37.477 11.4 38.101 ;
     RECT  12.384 34.741 14.424 38.101 ;
     RECT  10.176 38.101 14.424 38.149 ;
     RECT  10.176 38.149 14.808 38.531 ;
     RECT  5.1 31.955 5.412 38.725 ;
     RECT  10.5 38.531 14.808 39.011 ;
     RECT  14.784 39.011 14.808 39.251 ;
     RECT  2.4 31.715 2.712 39.493 ;
     RECT  7.344 35.845 8.376 39.539 ;
     RECT  15.9 36.275 20.328 39.587 ;
     RECT  2.4 39.493 2.856 39.731 ;
     RECT  2.4 39.731 2.808 39.827 ;
     RECT  5.1 38.725 6.312 40.691 ;
     RECT  15.9 39.587 17.064 40.837 ;
     RECT  18.048 39.587 20.328 40.837 ;
     RECT  10.5 39.011 13.704 41.075 ;
     RECT  9.456 41.365 9.48 41.507 ;
     RECT  7.344 39.539 8.28 41.749 ;
     RECT  10.5 41.075 13.656 42.421 ;
     RECT  10.5 42.421 13.992 43.187 ;
     RECT  10.5 43.187 11.4 43.331 ;
     RECT  7.344 41.749 9.048 43.379 ;
     RECT  2.4 39.827 2.712 44.149 ;
     RECT  2.016 44.149 2.712 44.339 ;
     RECT  12.384 43.187 13.992 45.059 ;
     RECT  15.9 40.837 20.328 45.059 ;
     RECT  10.5 43.331 10.812 45.253 ;
     RECT  12.48 45.059 13.992 45.541 ;
     RECT  12.48 45.541 14.232 45.587 ;
     RECT  0.144 45.733 0.168 46.019 ;
     RECT  10.5 45.253 11.016 46.069 ;
     RECT  7.8 43.379 9.048 46.259 ;
     RECT  10.224 46.069 11.016 46.259 ;
     RECT  18.144 45.059 20.328 46.741 ;
     RECT  7.8 46.259 8.232 46.835 ;
     RECT  13.2 45.587 14.232 47.317 ;
     RECT  15.9 45.059 16.92 47.605 ;
     RECT  10.224 46.259 10.812 47.795 ;
     RECT  7.8 46.835 8.112 47.845 ;
     RECT  15.9 47.605 17.064 47.987 ;
     RECT  18.048 46.741 20.328 48.083 ;
     RECT  2.4 44.339 2.712 48.133 ;
     RECT  10.5 47.795 10.812 48.229 ;
     RECT  2.4 48.133 2.856 48.275 ;
     RECT  7.8 47.845 9.096 48.469 ;
     RECT  15.9 47.987 16.92 48.997 ;
     RECT  7.392 48.469 9.096 49.091 ;
     RECT  12.528 47.317 14.232 49.331 ;
     RECT  13.104 49.331 14.232 49.427 ;
     RECT  13.2 49.427 14.232 49.525 ;
     RECT  15.9 48.997 17.016 49.525 ;
     RECT  7.8 49.091 9.096 49.619 ;
     RECT  10.5 48.229 10.92 49.717 ;
     RECT  13.2 49.525 17.016 50.195 ;
     RECT  7.8 49.619 8.52 50.437 ;
     RECT  0.144 50.389 0.168 50.579 ;
     RECT  7.296 50.437 8.52 50.771 ;
     RECT  10.5 49.717 11.16 51.395 ;
     RECT  18.144 48.083 20.328 52.069 ;
     RECT  2.4 48.275 2.712 52.261 ;
     RECT  7.8 50.771 8.52 52.357 ;
     RECT  2.304 52.261 2.712 52.403 ;
     RECT  13.2 50.195 16.92 53.027 ;
     RECT  7.68 52.357 8.52 53.075 ;
     RECT  13.2 53.027 13.944 53.075 ;
     RECT  5.1 40.691 5.412 53.269 ;
     RECT  17.952 52.069 20.328 53.603 ;
     RECT  13.2 53.075 13.512 53.749 ;
     RECT  5.1 53.269 5.544 53.987 ;
     RECT  7.68 53.075 8.232 54.181 ;
     RECT  13.104 53.749 13.512 54.565 ;
     RECT  12.24 54.565 13.512 54.613 ;
     RECT  14.928 53.027 16.92 54.613 ;
     RECT  18.144 53.603 20.328 54.613 ;
     RECT  10.5 51.395 10.812 54.661 ;
     RECT  12.24 54.613 20.328 54.661 ;
     RECT  6.864 54.181 8.232 54.899 ;
     RECT  10.5 54.661 20.328 55.331 ;
     RECT  10.5 55.331 13.512 55.813 ;
     RECT  10.272 55.813 13.512 55.859 ;
     RECT  6.864 54.899 8.112 55.907 ;
     RECT  15.168 55.331 20.328 56.195 ;
     RECT  0.144 56.053 0.168 56.339 ;
     RECT  12.24 55.859 13.512 56.483 ;
     RECT  10.272 55.859 10.812 56.819 ;
     RECT  12.528 56.483 13.512 57.059 ;
     RECT  14.88 57.253 14.904 57.443 ;
     RECT  15.9 56.195 20.328 57.491 ;
     RECT  9.12 57.925 9.144 58.451 ;
     RECT  15.9 57.491 17.16 59.029 ;
     RECT  18.144 57.491 20.328 59.029 ;
     RECT  10.5 56.819 10.812 59.221 ;
     RECT  13.2 57.059 13.512 59.797 ;
     RECT  7.008 55.907 8.112 60.131 ;
     RECT  15.9 59.029 20.328 60.325 ;
     RECT  15.792 60.325 20.328 60.371 ;
     RECT  9.12 60.277 9.144 60.419 ;
     RECT  13.2 59.797 14.232 60.467 ;
     RECT  17.568 60.371 20.328 60.611 ;
     RECT  13.2 60.467 13.512 60.709 ;
     RECT  10.368 59.221 10.812 60.851 ;
     RECT  15.792 60.371 16.212 61.331 ;
     RECT  18 60.611 20.328 61.715 ;
     RECT  12.432 60.709 13.512 61.763 ;
     RECT  18.144 61.715 20.232 61.955 ;
     RECT  18.144 61.955 18.912 62.003 ;
     RECT  20.208 61.955 20.232 62.099 ;
     RECT  2.4 52.403 2.712 62.649 ;
     RECT  5.1 53.987 5.412 62.649 ;
     RECT  7.8 60.131 8.112 62.649 ;
     RECT  10.5 60.851 10.812 62.649 ;
     RECT  13.2 61.763 13.512 62.649 ;
     RECT  15.9 61.331 16.212 62.649 ;
     RECT  18.6 62.003 18.912 62.649 ;
     RECT  2.4 62.649 2.52 62.663 ;
     RECT  5.1 62.649 5.22 62.663 ;
     RECT  7.8 62.649 7.92 62.663 ;
     RECT  10.5 62.649 10.62 62.663 ;
     RECT  13.2 62.649 13.32 62.663 ;
     RECT  15.9 62.649 16.02 62.663 ;
     RECT  18.6 62.649 18.72 62.663 ;
     RECT  0.144 2.867 0.168 4.213 ;
     RECT  15.792 2.915 15.9 3.109 ;
     RECT  13.512 3.109 14.784 4.019 ;
     RECT  14.808 3.109 15.9 4.019 ;
     RECT  16.212 4.453 17.184 9.109 ;
     RECT  8.112 6.229 9.504 6.803 ;
     RECT  15.792 8.723 15.9 9.349 ;
     RECT  5.412 9.061 6.72 9.589 ;
     RECT  6.744 9.061 7.8 9.635 ;
     RECT  13.608 9.349 14.832 10.643 ;
     RECT  14.856 9.349 15.9 10.643 ;
     RECT  6.264 9.635 7.8 10.933 ;
     RECT  8.112 9.637 9.456 12.469 ;
     RECT  12.96 9.683 13.008 11.125 ;
     RECT  13.608 10.643 14.328 11.077 ;
     RECT  6.264 10.933 7.68 11.171 ;
     RECT  13.704 11.077 14.328 12.085 ;
     RECT  10.812 11.125 12.24 12.805 ;
     RECT  5.412 12.227 5.544 13.621 ;
     RECT  19.944 12.229 21.408 12.419 ;
     RECT  8.112 12.469 9.264 14.677 ;
     RECT  11.208 12.805 12.24 13.091 ;
     RECT  10.812 13.091 12.24 17.605 ;
     RECT  5.412 13.621 6.912 14.675 ;
     RECT  19.464 15.829 20.496 16.019 ;
     RECT  9.288 16.115 10.32 16.595 ;
     RECT  9.048 16.595 10.32 17.123 ;
     RECT  8.112 17.123 10.32 18.037 ;
     RECT  10.812 17.605 12.144 18.421 ;
     RECT  12.168 17.651 13.2 19.285 ;
     RECT  8.112 18.037 10.08 18.325 ;
     RECT  8.112 18.325 9.12 18.467 ;
     RECT  8.112 18.467 8.424 19.525 ;
     RECT  10.812 18.563 12.144 19.859 ;
     RECT  8.232 19.525 8.424 19.861 ;
     RECT  7.392 19.571 7.8 20.005 ;
     RECT  13.656 19.813 15.168 19.955 ;
     RECT  10.812 19.859 12.336 21.061 ;
     RECT  6.264 20.005 7.8 20.149 ;
     RECT  6.6 20.149 7.8 21.107 ;
     RECT  5.412 20.579 6.576 21.107 ;
     RECT  7.344 21.107 7.8 22.021 ;
     RECT  10.812 21.683 12.336 22.741 ;
     RECT  8.424 21.781 9.696 22.501 ;
     RECT  15.408 22.499 15.792 23.269 ;
     RECT  5.412 22.741 6.48 25.139 ;
     RECT  8.424 22.787 9.696 22.931 ;
     RECT  8.232 22.931 9.696 23.941 ;
     RECT  14.76 23.269 15.792 23.315 ;
     RECT  14.76 23.315 15.9 24.947 ;
     RECT  13.512 23.555 14.736 24.947 ;
     RECT  9.048 23.987 10.32 24.949 ;
     RECT  10.812 23.987 12.336 26.101 ;
     RECT  9.144 24.949 10.32 25.091 ;
     RECT  5.412 25.139 6.864 25.429 ;
     RECT  5.784 25.429 6.864 25.811 ;
     RECT  10.968 26.101 12.336 27.059 ;
     RECT  10.812 27.059 12.336 28.885 ;
     RECT  5.784 27.637 6.816 27.923 ;
     RECT  8.808 27.829 10.32 29.605 ;
     RECT  10.92 28.885 12.336 29.075 ;
     RECT  10.812 29.075 12.336 30.851 ;
     RECT  9.144 29.605 10.32 29.797 ;
     RECT  8.112 29.699 9.12 29.843 ;
     RECT  9.144 29.797 10.224 29.843 ;
     RECT  10.08 29.843 10.224 31.189 ;
     RECT  5.412 31.955 6.864 32.147 ;
     RECT  11.304 32.917 12.384 34.259 ;
     RECT  11.256 34.259 12.384 37.477 ;
     RECT  14.424 34.741 15.9 35.317 ;
     RECT  14.424 35.317 15.792 36.275 ;
     RECT  14.424 36.275 15.9 38.149 ;
     RECT  11.4 37.477 12.384 38.101 ;
     RECT  14.808 38.149 15.9 39.251 ;
     RECT  6.312 38.725 7.344 40.691 ;
     RECT  13.704 39.011 14.784 39.251 ;
     RECT  17.064 39.587 18.048 40.837 ;
     RECT  13.656 41.075 13.704 42.421 ;
     RECT  8.28 41.365 9.456 41.507 ;
     RECT  9.48 41.365 10.5 41.507 ;
     RECT  8.28 41.507 10.5 41.749 ;
     RECT  9.048 41.749 10.5 46.069 ;
     RECT  11.4 43.187 12.384 43.331 ;
     RECT  12.384 45.059 12.48 45.253 ;
     RECT  16.92 45.059 18.144 46.741 ;
     RECT  11.016 45.253 12.48 45.587 ;
     RECT  9.048 46.069 10.224 46.259 ;
     RECT  16.92 46.741 18.048 47.605 ;
     RECT  8.112 46.835 8.232 47.845 ;
     RECT  17.064 47.605 18.048 47.987 ;
     RECT  10.224 47.795 10.5 47.845 ;
     RECT  9.096 47.845 10.5 49.619 ;
     RECT  16.92 47.987 18.048 48.083 ;
     RECT  16.92 48.083 18.144 48.997 ;
     RECT  17.016 48.997 18.144 50.195 ;
     RECT  7.392 49.091 7.8 50.437 ;
     RECT  16.92 50.195 18.144 52.069 ;
     RECT  16.92 52.069 17.952 53.603 ;
     RECT  13.944 53.027 14.928 53.075 ;
     RECT  13.512 53.075 14.928 54.613 ;
     RECT  16.92 53.603 18.144 54.613 ;
     RECT  5.412 53.987 5.544 54.181 ;
     RECT  5.412 54.181 6.864 55.907 ;
     RECT  10.812 54.565 12.24 54.661 ;
     RECT  10.812 55.859 12.24 56.483 ;
     RECT  15.168 56.195 15.9 57.253 ;
     RECT  10.272 56.819 10.5 57.925 ;
     RECT  13.512 57.253 14.88 57.443 ;
     RECT  14.904 57.253 15.9 57.443 ;
     RECT  17.16 57.491 18.144 59.029 ;
     RECT  8.112 57.925 9.12 58.451 ;
     RECT  9.144 57.925 10.5 58.451 ;
     RECT  10.368 58.451 10.5 59.221 ;
     RECT  8.112 60.277 9.12 60.419 ;
     RECT  9.144 60.277 10.368 60.419 ;
     RECT  16.212 60.371 17.568 60.611 ;
     RECT  18.912 61.955 20.208 62.099 ;
  END
END hbfd_rly_624_EW
END LIBRARY
